# Generated by FakeRAM 2.0
VERSION 5.7 ;
BUSBITCHARS "[]" ;
PROPERTYDEFINITIONS
  MACRO width INTEGER ;
  MACRO depth INTEGER ;
  MACRO banks INTEGER ;
END PROPERTYDEFINITIONS
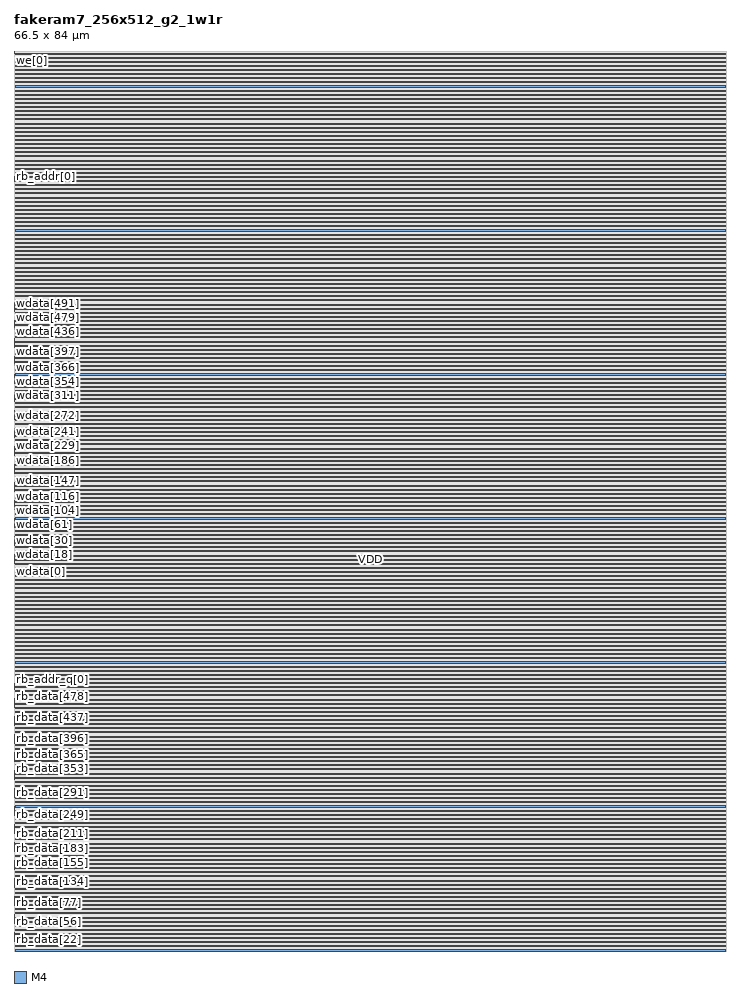
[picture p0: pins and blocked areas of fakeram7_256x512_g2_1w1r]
MACRO fakeram7_256x512_g2_1w1r
  PROPERTY width 512 ;
  PROPERTY depth 256 ;
  PROPERTY banks 1 ;
  FOREIGN fakeram7_256x512_g2_1w1r 0 0 ;
  SYMMETRY X Y R90 ;
  SIZE 66.5000 BY 84.0000 ;
  CLASS BLOCK ;
  PIN wdata[0]
    DIRECTION INPUT ;
    USE SIGNAL ;
    PORT
      LAYER M4 ;
      RECT 0.00000 36.14400 0.03600 36.16800 ;
    END
  END wdata[0]
  PIN wdata[1]
    DIRECTION INPUT ;
    USE SIGNAL ;
    PORT
      LAYER M4 ;
      RECT 0.00000 36.19200 0.03600 36.21600 ;
    END
  END wdata[1]
  PIN wdata[2]
    DIRECTION INPUT ;
    USE SIGNAL ;
    PORT
      LAYER M4 ;
      RECT 0.00000 36.24000 0.03600 36.26400 ;
    END
  END wdata[2]
  PIN wdata[3]
    DIRECTION INPUT ;
    USE SIGNAL ;
    PORT
      LAYER M4 ;
      RECT 0.00000 36.28800 0.03600 36.31200 ;
    END
  END wdata[3]
  PIN wdata[4]
    DIRECTION INPUT ;
    USE SIGNAL ;
    PORT
      LAYER M4 ;
      RECT 0.00000 36.33600 0.03600 36.36000 ;
    END
  END wdata[4]
  PIN wdata[5]
    DIRECTION INPUT ;
    USE SIGNAL ;
    PORT
      LAYER M4 ;
      RECT 0.00000 36.38400 0.03600 36.40800 ;
    END
  END wdata[5]
  PIN wdata[6]
    DIRECTION INPUT ;
    USE SIGNAL ;
    PORT
      LAYER M4 ;
      RECT 0.00000 36.43200 0.03600 36.45600 ;
    END
  END wdata[6]
  PIN wdata[7]
    DIRECTION INPUT ;
    USE SIGNAL ;
    PORT
      LAYER M4 ;
      RECT 0.00000 36.48000 0.03600 36.50400 ;
    END
  END wdata[7]
  PIN wdata[8]
    DIRECTION INPUT ;
    USE SIGNAL ;
    PORT
      LAYER M4 ;
      RECT 0.00000 36.52800 0.03600 36.55200 ;
    END
  END wdata[8]
  PIN wdata[9]
    DIRECTION INPUT ;
    USE SIGNAL ;
    PORT
      LAYER M4 ;
      RECT 0.00000 36.57600 0.03600 36.60000 ;
    END
  END wdata[9]
  PIN wdata[10]
    DIRECTION INPUT ;
    USE SIGNAL ;
    PORT
      LAYER M4 ;
      RECT 0.00000 36.62400 0.03600 36.64800 ;
    END
  END wdata[10]
  PIN wdata[11]
    DIRECTION INPUT ;
    USE SIGNAL ;
    PORT
      LAYER M4 ;
      RECT 0.00000 36.67200 0.03600 36.69600 ;
    END
  END wdata[11]
  PIN wdata[12]
    DIRECTION INPUT ;
    USE SIGNAL ;
    PORT
      LAYER M4 ;
      RECT 0.00000 36.72000 0.03600 36.74400 ;
    END
  END wdata[12]
  PIN wdata[13]
    DIRECTION INPUT ;
    USE SIGNAL ;
    PORT
      LAYER M4 ;
      RECT 0.00000 36.76800 0.03600 36.79200 ;
    END
  END wdata[13]
  PIN wdata[14]
    DIRECTION INPUT ;
    USE SIGNAL ;
    PORT
      LAYER M4 ;
      RECT 0.00000 36.81600 0.03600 36.84000 ;
    END
  END wdata[14]
  PIN wdata[15]
    DIRECTION INPUT ;
    USE SIGNAL ;
    PORT
      LAYER M4 ;
      RECT 0.00000 36.86400 0.03600 36.88800 ;
    END
  END wdata[15]
  PIN wdata[16]
    DIRECTION INPUT ;
    USE SIGNAL ;
    PORT
      LAYER M4 ;
      RECT 0.00000 36.91200 0.03600 36.93600 ;
    END
  END wdata[16]
  PIN wdata[17]
    DIRECTION INPUT ;
    USE SIGNAL ;
    PORT
      LAYER M4 ;
      RECT 0.00000 36.96000 0.03600 36.98400 ;
    END
  END wdata[17]
  PIN wdata[18]
    DIRECTION INPUT ;
    USE SIGNAL ;
    PORT
      LAYER M4 ;
      RECT 0.00000 37.00800 0.03600 37.03200 ;
    END
  END wdata[18]
  PIN wdata[19]
    DIRECTION INPUT ;
    USE SIGNAL ;
    PORT
      LAYER M4 ;
      RECT 0.00000 37.05600 0.03600 37.08000 ;
    END
  END wdata[19]
  PIN wdata[20]
    DIRECTION INPUT ;
    USE SIGNAL ;
    PORT
      LAYER M4 ;
      RECT 0.00000 37.10400 0.03600 37.12800 ;
    END
  END wdata[20]
  PIN wdata[21]
    DIRECTION INPUT ;
    USE SIGNAL ;
    PORT
      LAYER M4 ;
      RECT 0.00000 37.15200 0.03600 37.17600 ;
    END
  END wdata[21]
  PIN wdata[22]
    DIRECTION INPUT ;
    USE SIGNAL ;
    PORT
      LAYER M4 ;
      RECT 0.00000 37.20000 0.03600 37.22400 ;
    END
  END wdata[22]
  PIN wdata[23]
    DIRECTION INPUT ;
    USE SIGNAL ;
    PORT
      LAYER M4 ;
      RECT 0.00000 37.24800 0.03600 37.27200 ;
    END
  END wdata[23]
  PIN wdata[24]
    DIRECTION INPUT ;
    USE SIGNAL ;
    PORT
      LAYER M4 ;
      RECT 0.00000 37.29600 0.03600 37.32000 ;
    END
  END wdata[24]
  PIN wdata[25]
    DIRECTION INPUT ;
    USE SIGNAL ;
    PORT
      LAYER M4 ;
      RECT 0.00000 37.34400 0.03600 37.36800 ;
    END
  END wdata[25]
  PIN wdata[26]
    DIRECTION INPUT ;
    USE SIGNAL ;
    PORT
      LAYER M4 ;
      RECT 0.00000 37.39200 0.03600 37.41600 ;
    END
  END wdata[26]
  PIN wdata[27]
    DIRECTION INPUT ;
    USE SIGNAL ;
    PORT
      LAYER M4 ;
      RECT 0.00000 37.44000 0.03600 37.46400 ;
    END
  END wdata[27]
  PIN wdata[28]
    DIRECTION INPUT ;
    USE SIGNAL ;
    PORT
      LAYER M4 ;
      RECT 0.00000 37.48800 0.03600 37.51200 ;
    END
  END wdata[28]
  PIN wdata[29]
    DIRECTION INPUT ;
    USE SIGNAL ;
    PORT
      LAYER M4 ;
      RECT 0.00000 37.53600 0.03600 37.56000 ;
    END
  END wdata[29]
  PIN wdata[30]
    DIRECTION INPUT ;
    USE SIGNAL ;
    PORT
      LAYER M4 ;
      RECT 0.00000 37.58400 0.03600 37.60800 ;
    END
  END wdata[30]
  PIN wdata[31]
    DIRECTION INPUT ;
    USE SIGNAL ;
    PORT
      LAYER M4 ;
      RECT 0.00000 37.63200 0.03600 37.65600 ;
    END
  END wdata[31]
  PIN wdata[32]
    DIRECTION INPUT ;
    USE SIGNAL ;
    PORT
      LAYER M4 ;
      RECT 0.00000 37.68000 0.03600 37.70400 ;
    END
  END wdata[32]
  PIN wdata[33]
    DIRECTION INPUT ;
    USE SIGNAL ;
    PORT
      LAYER M4 ;
      RECT 0.00000 37.72800 0.03600 37.75200 ;
    END
  END wdata[33]
  PIN wdata[34]
    DIRECTION INPUT ;
    USE SIGNAL ;
    PORT
      LAYER M4 ;
      RECT 0.00000 37.77600 0.03600 37.80000 ;
    END
  END wdata[34]
  PIN wdata[35]
    DIRECTION INPUT ;
    USE SIGNAL ;
    PORT
      LAYER M4 ;
      RECT 0.00000 37.82400 0.03600 37.84800 ;
    END
  END wdata[35]
  PIN wdata[36]
    DIRECTION INPUT ;
    USE SIGNAL ;
    PORT
      LAYER M4 ;
      RECT 0.00000 37.87200 0.03600 37.89600 ;
    END
  END wdata[36]
  PIN wdata[37]
    DIRECTION INPUT ;
    USE SIGNAL ;
    PORT
      LAYER M4 ;
      RECT 0.00000 37.92000 0.03600 37.94400 ;
    END
  END wdata[37]
  PIN wdata[38]
    DIRECTION INPUT ;
    USE SIGNAL ;
    PORT
      LAYER M4 ;
      RECT 0.00000 37.96800 0.03600 37.99200 ;
    END
  END wdata[38]
  PIN wdata[39]
    DIRECTION INPUT ;
    USE SIGNAL ;
    PORT
      LAYER M4 ;
      RECT 0.00000 38.01600 0.03600 38.04000 ;
    END
  END wdata[39]
  PIN wdata[40]
    DIRECTION INPUT ;
    USE SIGNAL ;
    PORT
      LAYER M4 ;
      RECT 0.00000 38.06400 0.03600 38.08800 ;
    END
  END wdata[40]
  PIN wdata[41]
    DIRECTION INPUT ;
    USE SIGNAL ;
    PORT
      LAYER M4 ;
      RECT 0.00000 38.11200 0.03600 38.13600 ;
    END
  END wdata[41]
  PIN wdata[42]
    DIRECTION INPUT ;
    USE SIGNAL ;
    PORT
      LAYER M4 ;
      RECT 0.00000 38.16000 0.03600 38.18400 ;
    END
  END wdata[42]
  PIN wdata[43]
    DIRECTION INPUT ;
    USE SIGNAL ;
    PORT
      LAYER M4 ;
      RECT 0.00000 38.20800 0.03600 38.23200 ;
    END
  END wdata[43]
  PIN wdata[44]
    DIRECTION INPUT ;
    USE SIGNAL ;
    PORT
      LAYER M4 ;
      RECT 0.00000 38.25600 0.03600 38.28000 ;
    END
  END wdata[44]
  PIN wdata[45]
    DIRECTION INPUT ;
    USE SIGNAL ;
    PORT
      LAYER M4 ;
      RECT 0.00000 38.30400 0.03600 38.32800 ;
    END
  END wdata[45]
  PIN wdata[46]
    DIRECTION INPUT ;
    USE SIGNAL ;
    PORT
      LAYER M4 ;
      RECT 0.00000 38.35200 0.03600 38.37600 ;
    END
  END wdata[46]
  PIN wdata[47]
    DIRECTION INPUT ;
    USE SIGNAL ;
    PORT
      LAYER M4 ;
      RECT 0.00000 38.40000 0.03600 38.42400 ;
    END
  END wdata[47]
  PIN wdata[48]
    DIRECTION INPUT ;
    USE SIGNAL ;
    PORT
      LAYER M4 ;
      RECT 0.00000 38.44800 0.03600 38.47200 ;
    END
  END wdata[48]
  PIN wdata[49]
    DIRECTION INPUT ;
    USE SIGNAL ;
    PORT
      LAYER M4 ;
      RECT 0.00000 38.49600 0.03600 38.52000 ;
    END
  END wdata[49]
  PIN wdata[50]
    DIRECTION INPUT ;
    USE SIGNAL ;
    PORT
      LAYER M4 ;
      RECT 0.00000 38.54400 0.03600 38.56800 ;
    END
  END wdata[50]
  PIN wdata[51]
    DIRECTION INPUT ;
    USE SIGNAL ;
    PORT
      LAYER M4 ;
      RECT 0.00000 38.59200 0.03600 38.61600 ;
    END
  END wdata[51]
  PIN wdata[52]
    DIRECTION INPUT ;
    USE SIGNAL ;
    PORT
      LAYER M4 ;
      RECT 0.00000 38.64000 0.03600 38.66400 ;
    END
  END wdata[52]
  PIN wdata[53]
    DIRECTION INPUT ;
    USE SIGNAL ;
    PORT
      LAYER M4 ;
      RECT 0.00000 38.68800 0.03600 38.71200 ;
    END
  END wdata[53]
  PIN wdata[54]
    DIRECTION INPUT ;
    USE SIGNAL ;
    PORT
      LAYER M4 ;
      RECT 0.00000 38.73600 0.03600 38.76000 ;
    END
  END wdata[54]
  PIN wdata[55]
    DIRECTION INPUT ;
    USE SIGNAL ;
    PORT
      LAYER M4 ;
      RECT 0.00000 38.78400 0.03600 38.80800 ;
    END
  END wdata[55]
  PIN wdata[56]
    DIRECTION INPUT ;
    USE SIGNAL ;
    PORT
      LAYER M4 ;
      RECT 0.00000 38.83200 0.03600 38.85600 ;
    END
  END wdata[56]
  PIN wdata[57]
    DIRECTION INPUT ;
    USE SIGNAL ;
    PORT
      LAYER M4 ;
      RECT 0.00000 38.88000 0.03600 38.90400 ;
    END
  END wdata[57]
  PIN wdata[58]
    DIRECTION INPUT ;
    USE SIGNAL ;
    PORT
      LAYER M4 ;
      RECT 0.00000 38.92800 0.03600 38.95200 ;
    END
  END wdata[58]
  PIN wdata[59]
    DIRECTION INPUT ;
    USE SIGNAL ;
    PORT
      LAYER M4 ;
      RECT 0.00000 38.97600 0.03600 39.00000 ;
    END
  END wdata[59]
  PIN wdata[60]
    DIRECTION INPUT ;
    USE SIGNAL ;
    PORT
      LAYER M4 ;
      RECT 0.00000 39.02400 0.03600 39.04800 ;
    END
  END wdata[60]
  PIN wdata[61]
    DIRECTION INPUT ;
    USE SIGNAL ;
    PORT
      LAYER M4 ;
      RECT 0.00000 39.07200 0.03600 39.09600 ;
    END
  END wdata[61]
  PIN wdata[62]
    DIRECTION INPUT ;
    USE SIGNAL ;
    PORT
      LAYER M4 ;
      RECT 0.00000 39.12000 0.03600 39.14400 ;
    END
  END wdata[62]
  PIN wdata[63]
    DIRECTION INPUT ;
    USE SIGNAL ;
    PORT
      LAYER M4 ;
      RECT 0.00000 39.16800 0.03600 39.19200 ;
    END
  END wdata[63]
  PIN wdata[64]
    DIRECTION INPUT ;
    USE SIGNAL ;
    PORT
      LAYER M4 ;
      RECT 0.00000 39.21600 0.03600 39.24000 ;
    END
  END wdata[64]
  PIN wdata[65]
    DIRECTION INPUT ;
    USE SIGNAL ;
    PORT
      LAYER M4 ;
      RECT 0.00000 39.26400 0.03600 39.28800 ;
    END
  END wdata[65]
  PIN wdata[66]
    DIRECTION INPUT ;
    USE SIGNAL ;
    PORT
      LAYER M4 ;
      RECT 0.00000 39.31200 0.03600 39.33600 ;
    END
  END wdata[66]
  PIN wdata[67]
    DIRECTION INPUT ;
    USE SIGNAL ;
    PORT
      LAYER M4 ;
      RECT 0.00000 39.36000 0.03600 39.38400 ;
    END
  END wdata[67]
  PIN wdata[68]
    DIRECTION INPUT ;
    USE SIGNAL ;
    PORT
      LAYER M4 ;
      RECT 0.00000 39.40800 0.03600 39.43200 ;
    END
  END wdata[68]
  PIN wdata[69]
    DIRECTION INPUT ;
    USE SIGNAL ;
    PORT
      LAYER M4 ;
      RECT 0.00000 39.45600 0.03600 39.48000 ;
    END
  END wdata[69]
  PIN wdata[70]
    DIRECTION INPUT ;
    USE SIGNAL ;
    PORT
      LAYER M4 ;
      RECT 0.00000 39.50400 0.03600 39.52800 ;
    END
  END wdata[70]
  PIN wdata[71]
    DIRECTION INPUT ;
    USE SIGNAL ;
    PORT
      LAYER M4 ;
      RECT 0.00000 39.55200 0.03600 39.57600 ;
    END
  END wdata[71]
  PIN wdata[72]
    DIRECTION INPUT ;
    USE SIGNAL ;
    PORT
      LAYER M4 ;
      RECT 0.00000 39.60000 0.03600 39.62400 ;
    END
  END wdata[72]
  PIN wdata[73]
    DIRECTION INPUT ;
    USE SIGNAL ;
    PORT
      LAYER M4 ;
      RECT 0.00000 39.64800 0.03600 39.67200 ;
    END
  END wdata[73]
  PIN wdata[74]
    DIRECTION INPUT ;
    USE SIGNAL ;
    PORT
      LAYER M4 ;
      RECT 0.00000 39.69600 0.03600 39.72000 ;
    END
  END wdata[74]
  PIN wdata[75]
    DIRECTION INPUT ;
    USE SIGNAL ;
    PORT
      LAYER M4 ;
      RECT 0.00000 39.74400 0.03600 39.76800 ;
    END
  END wdata[75]
  PIN wdata[76]
    DIRECTION INPUT ;
    USE SIGNAL ;
    PORT
      LAYER M4 ;
      RECT 0.00000 39.79200 0.03600 39.81600 ;
    END
  END wdata[76]
  PIN wdata[77]
    DIRECTION INPUT ;
    USE SIGNAL ;
    PORT
      LAYER M4 ;
      RECT 0.00000 39.84000 0.03600 39.86400 ;
    END
  END wdata[77]
  PIN wdata[78]
    DIRECTION INPUT ;
    USE SIGNAL ;
    PORT
      LAYER M4 ;
      RECT 0.00000 39.88800 0.03600 39.91200 ;
    END
  END wdata[78]
  PIN wdata[79]
    DIRECTION INPUT ;
    USE SIGNAL ;
    PORT
      LAYER M4 ;
      RECT 0.00000 39.93600 0.03600 39.96000 ;
    END
  END wdata[79]
  PIN wdata[80]
    DIRECTION INPUT ;
    USE SIGNAL ;
    PORT
      LAYER M4 ;
      RECT 0.00000 39.98400 0.03600 40.00800 ;
    END
  END wdata[80]
  PIN wdata[81]
    DIRECTION INPUT ;
    USE SIGNAL ;
    PORT
      LAYER M4 ;
      RECT 0.00000 40.03200 0.03600 40.05600 ;
    END
  END wdata[81]
  PIN wdata[82]
    DIRECTION INPUT ;
    USE SIGNAL ;
    PORT
      LAYER M4 ;
      RECT 0.00000 40.08000 0.03600 40.10400 ;
    END
  END wdata[82]
  PIN wdata[83]
    DIRECTION INPUT ;
    USE SIGNAL ;
    PORT
      LAYER M4 ;
      RECT 0.00000 40.12800 0.03600 40.15200 ;
    END
  END wdata[83]
  PIN wdata[84]
    DIRECTION INPUT ;
    USE SIGNAL ;
    PORT
      LAYER M4 ;
      RECT 0.00000 40.17600 0.03600 40.20000 ;
    END
  END wdata[84]
  PIN wdata[85]
    DIRECTION INPUT ;
    USE SIGNAL ;
    PORT
      LAYER M4 ;
      RECT 0.00000 40.22400 0.03600 40.24800 ;
    END
  END wdata[85]
  PIN wdata[86]
    DIRECTION INPUT ;
    USE SIGNAL ;
    PORT
      LAYER M4 ;
      RECT 0.00000 40.27200 0.03600 40.29600 ;
    END
  END wdata[86]
  PIN wdata[87]
    DIRECTION INPUT ;
    USE SIGNAL ;
    PORT
      LAYER M4 ;
      RECT 0.00000 40.32000 0.03600 40.34400 ;
    END
  END wdata[87]
  PIN wdata[88]
    DIRECTION INPUT ;
    USE SIGNAL ;
    PORT
      LAYER M4 ;
      RECT 0.00000 40.36800 0.03600 40.39200 ;
    END
  END wdata[88]
  PIN wdata[89]
    DIRECTION INPUT ;
    USE SIGNAL ;
    PORT
      LAYER M4 ;
      RECT 0.00000 40.41600 0.03600 40.44000 ;
    END
  END wdata[89]
  PIN wdata[90]
    DIRECTION INPUT ;
    USE SIGNAL ;
    PORT
      LAYER M4 ;
      RECT 0.00000 40.46400 0.03600 40.48800 ;
    END
  END wdata[90]
  PIN wdata[91]
    DIRECTION INPUT ;
    USE SIGNAL ;
    PORT
      LAYER M4 ;
      RECT 0.00000 40.51200 0.03600 40.53600 ;
    END
  END wdata[91]
  PIN wdata[92]
    DIRECTION INPUT ;
    USE SIGNAL ;
    PORT
      LAYER M4 ;
      RECT 0.00000 40.56000 0.03600 40.58400 ;
    END
  END wdata[92]
  PIN wdata[93]
    DIRECTION INPUT ;
    USE SIGNAL ;
    PORT
      LAYER M4 ;
      RECT 0.00000 40.60800 0.03600 40.63200 ;
    END
  END wdata[93]
  PIN wdata[94]
    DIRECTION INPUT ;
    USE SIGNAL ;
    PORT
      LAYER M4 ;
      RECT 0.00000 40.65600 0.03600 40.68000 ;
    END
  END wdata[94]
  PIN wdata[95]
    DIRECTION INPUT ;
    USE SIGNAL ;
    PORT
      LAYER M4 ;
      RECT 0.00000 40.70400 0.03600 40.72800 ;
    END
  END wdata[95]
  PIN wdata[96]
    DIRECTION INPUT ;
    USE SIGNAL ;
    PORT
      LAYER M4 ;
      RECT 0.00000 40.75200 0.03600 40.77600 ;
    END
  END wdata[96]
  PIN wdata[97]
    DIRECTION INPUT ;
    USE SIGNAL ;
    PORT
      LAYER M4 ;
      RECT 0.00000 40.80000 0.03600 40.82400 ;
    END
  END wdata[97]
  PIN wdata[98]
    DIRECTION INPUT ;
    USE SIGNAL ;
    PORT
      LAYER M4 ;
      RECT 0.00000 40.84800 0.03600 40.87200 ;
    END
  END wdata[98]
  PIN wdata[99]
    DIRECTION INPUT ;
    USE SIGNAL ;
    PORT
      LAYER M4 ;
      RECT 0.00000 40.89600 0.03600 40.92000 ;
    END
  END wdata[99]
  PIN wdata[100]
    DIRECTION INPUT ;
    USE SIGNAL ;
    PORT
      LAYER M4 ;
      RECT 0.00000 40.94400 0.03600 40.96800 ;
    END
  END wdata[100]
  PIN wdata[101]
    DIRECTION INPUT ;
    USE SIGNAL ;
    PORT
      LAYER M4 ;
      RECT 0.00000 40.99200 0.03600 41.01600 ;
    END
  END wdata[101]
  PIN wdata[102]
    DIRECTION INPUT ;
    USE SIGNAL ;
    PORT
      LAYER M4 ;
      RECT 0.00000 41.04000 0.03600 41.06400 ;
    END
  END wdata[102]
  PIN wdata[103]
    DIRECTION INPUT ;
    USE SIGNAL ;
    PORT
      LAYER M4 ;
      RECT 0.00000 41.08800 0.03600 41.11200 ;
    END
  END wdata[103]
  PIN wdata[104]
    DIRECTION INPUT ;
    USE SIGNAL ;
    PORT
      LAYER M4 ;
      RECT 0.00000 41.13600 0.03600 41.16000 ;
    END
  END wdata[104]
  PIN wdata[105]
    DIRECTION INPUT ;
    USE SIGNAL ;
    PORT
      LAYER M4 ;
      RECT 0.00000 41.18400 0.03600 41.20800 ;
    END
  END wdata[105]
  PIN wdata[106]
    DIRECTION INPUT ;
    USE SIGNAL ;
    PORT
      LAYER M4 ;
      RECT 0.00000 41.23200 0.03600 41.25600 ;
    END
  END wdata[106]
  PIN wdata[107]
    DIRECTION INPUT ;
    USE SIGNAL ;
    PORT
      LAYER M4 ;
      RECT 0.00000 41.28000 0.03600 41.30400 ;
    END
  END wdata[107]
  PIN wdata[108]
    DIRECTION INPUT ;
    USE SIGNAL ;
    PORT
      LAYER M4 ;
      RECT 0.00000 41.32800 0.03600 41.35200 ;
    END
  END wdata[108]
  PIN wdata[109]
    DIRECTION INPUT ;
    USE SIGNAL ;
    PORT
      LAYER M4 ;
      RECT 0.00000 41.37600 0.03600 41.40000 ;
    END
  END wdata[109]
  PIN wdata[110]
    DIRECTION INPUT ;
    USE SIGNAL ;
    PORT
      LAYER M4 ;
      RECT 0.00000 41.42400 0.03600 41.44800 ;
    END
  END wdata[110]
  PIN wdata[111]
    DIRECTION INPUT ;
    USE SIGNAL ;
    PORT
      LAYER M4 ;
      RECT 0.00000 41.47200 0.03600 41.49600 ;
    END
  END wdata[111]
  PIN wdata[112]
    DIRECTION INPUT ;
    USE SIGNAL ;
    PORT
      LAYER M4 ;
      RECT 0.00000 41.52000 0.03600 41.54400 ;
    END
  END wdata[112]
  PIN wdata[113]
    DIRECTION INPUT ;
    USE SIGNAL ;
    PORT
      LAYER M4 ;
      RECT 0.00000 41.56800 0.03600 41.59200 ;
    END
  END wdata[113]
  PIN wdata[114]
    DIRECTION INPUT ;
    USE SIGNAL ;
    PORT
      LAYER M4 ;
      RECT 0.00000 41.61600 0.03600 41.64000 ;
    END
  END wdata[114]
  PIN wdata[115]
    DIRECTION INPUT ;
    USE SIGNAL ;
    PORT
      LAYER M4 ;
      RECT 0.00000 41.66400 0.03600 41.68800 ;
    END
  END wdata[115]
  PIN wdata[116]
    DIRECTION INPUT ;
    USE SIGNAL ;
    PORT
      LAYER M4 ;
      RECT 0.00000 41.71200 0.03600 41.73600 ;
    END
  END wdata[116]
  PIN wdata[117]
    DIRECTION INPUT ;
    USE SIGNAL ;
    PORT
      LAYER M4 ;
      RECT 0.00000 41.76000 0.03600 41.78400 ;
    END
  END wdata[117]
  PIN wdata[118]
    DIRECTION INPUT ;
    USE SIGNAL ;
    PORT
      LAYER M4 ;
      RECT 0.00000 41.80800 0.03600 41.83200 ;
    END
  END wdata[118]
  PIN wdata[119]
    DIRECTION INPUT ;
    USE SIGNAL ;
    PORT
      LAYER M4 ;
      RECT 0.00000 41.85600 0.03600 41.88000 ;
    END
  END wdata[119]
  PIN wdata[120]
    DIRECTION INPUT ;
    USE SIGNAL ;
    PORT
      LAYER M4 ;
      RECT 0.00000 41.90400 0.03600 41.92800 ;
    END
  END wdata[120]
  PIN wdata[121]
    DIRECTION INPUT ;
    USE SIGNAL ;
    PORT
      LAYER M4 ;
      RECT 0.00000 41.95200 0.03600 41.97600 ;
    END
  END wdata[121]
  PIN wdata[122]
    DIRECTION INPUT ;
    USE SIGNAL ;
    PORT
      LAYER M4 ;
      RECT 0.00000 42.00000 0.03600 42.02400 ;
    END
  END wdata[122]
  PIN wdata[123]
    DIRECTION INPUT ;
    USE SIGNAL ;
    PORT
      LAYER M4 ;
      RECT 0.00000 42.04800 0.03600 42.07200 ;
    END
  END wdata[123]
  PIN wdata[124]
    DIRECTION INPUT ;
    USE SIGNAL ;
    PORT
      LAYER M4 ;
      RECT 0.00000 42.09600 0.03600 42.12000 ;
    END
  END wdata[124]
  PIN wdata[125]
    DIRECTION INPUT ;
    USE SIGNAL ;
    PORT
      LAYER M4 ;
      RECT 0.00000 42.14400 0.03600 42.16800 ;
    END
  END wdata[125]
  PIN wdata[126]
    DIRECTION INPUT ;
    USE SIGNAL ;
    PORT
      LAYER M4 ;
      RECT 0.00000 42.19200 0.03600 42.21600 ;
    END
  END wdata[126]
  PIN wdata[127]
    DIRECTION INPUT ;
    USE SIGNAL ;
    PORT
      LAYER M4 ;
      RECT 0.00000 42.24000 0.03600 42.26400 ;
    END
  END wdata[127]
  PIN wdata[128]
    DIRECTION INPUT ;
    USE SIGNAL ;
    PORT
      LAYER M4 ;
      RECT 0.00000 42.28800 0.03600 42.31200 ;
    END
  END wdata[128]
  PIN wdata[129]
    DIRECTION INPUT ;
    USE SIGNAL ;
    PORT
      LAYER M4 ;
      RECT 0.00000 42.33600 0.03600 42.36000 ;
    END
  END wdata[129]
  PIN wdata[130]
    DIRECTION INPUT ;
    USE SIGNAL ;
    PORT
      LAYER M4 ;
      RECT 0.00000 42.38400 0.03600 42.40800 ;
    END
  END wdata[130]
  PIN wdata[131]
    DIRECTION INPUT ;
    USE SIGNAL ;
    PORT
      LAYER M4 ;
      RECT 0.00000 42.43200 0.03600 42.45600 ;
    END
  END wdata[131]
  PIN wdata[132]
    DIRECTION INPUT ;
    USE SIGNAL ;
    PORT
      LAYER M4 ;
      RECT 0.00000 42.48000 0.03600 42.50400 ;
    END
  END wdata[132]
  PIN wdata[133]
    DIRECTION INPUT ;
    USE SIGNAL ;
    PORT
      LAYER M4 ;
      RECT 0.00000 42.52800 0.03600 42.55200 ;
    END
  END wdata[133]
  PIN wdata[134]
    DIRECTION INPUT ;
    USE SIGNAL ;
    PORT
      LAYER M4 ;
      RECT 0.00000 42.57600 0.03600 42.60000 ;
    END
  END wdata[134]
  PIN wdata[135]
    DIRECTION INPUT ;
    USE SIGNAL ;
    PORT
      LAYER M4 ;
      RECT 0.00000 42.62400 0.03600 42.64800 ;
    END
  END wdata[135]
  PIN wdata[136]
    DIRECTION INPUT ;
    USE SIGNAL ;
    PORT
      LAYER M4 ;
      RECT 0.00000 42.67200 0.03600 42.69600 ;
    END
  END wdata[136]
  PIN wdata[137]
    DIRECTION INPUT ;
    USE SIGNAL ;
    PORT
      LAYER M4 ;
      RECT 0.00000 42.72000 0.03600 42.74400 ;
    END
  END wdata[137]
  PIN wdata[138]
    DIRECTION INPUT ;
    USE SIGNAL ;
    PORT
      LAYER M4 ;
      RECT 0.00000 42.76800 0.03600 42.79200 ;
    END
  END wdata[138]
  PIN wdata[139]
    DIRECTION INPUT ;
    USE SIGNAL ;
    PORT
      LAYER M4 ;
      RECT 0.00000 42.81600 0.03600 42.84000 ;
    END
  END wdata[139]
  PIN wdata[140]
    DIRECTION INPUT ;
    USE SIGNAL ;
    PORT
      LAYER M4 ;
      RECT 0.00000 42.86400 0.03600 42.88800 ;
    END
  END wdata[140]
  PIN wdata[141]
    DIRECTION INPUT ;
    USE SIGNAL ;
    PORT
      LAYER M4 ;
      RECT 0.00000 42.91200 0.03600 42.93600 ;
    END
  END wdata[141]
  PIN wdata[142]
    DIRECTION INPUT ;
    USE SIGNAL ;
    PORT
      LAYER M4 ;
      RECT 0.00000 42.96000 0.03600 42.98400 ;
    END
  END wdata[142]
  PIN wdata[143]
    DIRECTION INPUT ;
    USE SIGNAL ;
    PORT
      LAYER M4 ;
      RECT 0.00000 43.00800 0.03600 43.03200 ;
    END
  END wdata[143]
  PIN wdata[144]
    DIRECTION INPUT ;
    USE SIGNAL ;
    PORT
      LAYER M4 ;
      RECT 0.00000 43.05600 0.03600 43.08000 ;
    END
  END wdata[144]
  PIN wdata[145]
    DIRECTION INPUT ;
    USE SIGNAL ;
    PORT
      LAYER M4 ;
      RECT 0.00000 43.10400 0.03600 43.12800 ;
    END
  END wdata[145]
  PIN wdata[146]
    DIRECTION INPUT ;
    USE SIGNAL ;
    PORT
      LAYER M4 ;
      RECT 0.00000 43.15200 0.03600 43.17600 ;
    END
  END wdata[146]
  PIN wdata[147]
    DIRECTION INPUT ;
    USE SIGNAL ;
    PORT
      LAYER M4 ;
      RECT 0.00000 43.20000 0.03600 43.22400 ;
    END
  END wdata[147]
  PIN wdata[148]
    DIRECTION INPUT ;
    USE SIGNAL ;
    PORT
      LAYER M4 ;
      RECT 0.00000 43.24800 0.03600 43.27200 ;
    END
  END wdata[148]
  PIN wdata[149]
    DIRECTION INPUT ;
    USE SIGNAL ;
    PORT
      LAYER M4 ;
      RECT 0.00000 43.29600 0.03600 43.32000 ;
    END
  END wdata[149]
  PIN wdata[150]
    DIRECTION INPUT ;
    USE SIGNAL ;
    PORT
      LAYER M4 ;
      RECT 0.00000 43.34400 0.03600 43.36800 ;
    END
  END wdata[150]
  PIN wdata[151]
    DIRECTION INPUT ;
    USE SIGNAL ;
    PORT
      LAYER M4 ;
      RECT 0.00000 43.39200 0.03600 43.41600 ;
    END
  END wdata[151]
  PIN wdata[152]
    DIRECTION INPUT ;
    USE SIGNAL ;
    PORT
      LAYER M4 ;
      RECT 0.00000 43.44000 0.03600 43.46400 ;
    END
  END wdata[152]
  PIN wdata[153]
    DIRECTION INPUT ;
    USE SIGNAL ;
    PORT
      LAYER M4 ;
      RECT 0.00000 43.48800 0.03600 43.51200 ;
    END
  END wdata[153]
  PIN wdata[154]
    DIRECTION INPUT ;
    USE SIGNAL ;
    PORT
      LAYER M4 ;
      RECT 0.00000 43.53600 0.03600 43.56000 ;
    END
  END wdata[154]
  PIN wdata[155]
    DIRECTION INPUT ;
    USE SIGNAL ;
    PORT
      LAYER M4 ;
      RECT 0.00000 43.58400 0.03600 43.60800 ;
    END
  END wdata[155]
  PIN wdata[156]
    DIRECTION INPUT ;
    USE SIGNAL ;
    PORT
      LAYER M4 ;
      RECT 0.00000 43.63200 0.03600 43.65600 ;
    END
  END wdata[156]
  PIN wdata[157]
    DIRECTION INPUT ;
    USE SIGNAL ;
    PORT
      LAYER M4 ;
      RECT 0.00000 43.68000 0.03600 43.70400 ;
    END
  END wdata[157]
  PIN wdata[158]
    DIRECTION INPUT ;
    USE SIGNAL ;
    PORT
      LAYER M4 ;
      RECT 0.00000 43.72800 0.03600 43.75200 ;
    END
  END wdata[158]
  PIN wdata[159]
    DIRECTION INPUT ;
    USE SIGNAL ;
    PORT
      LAYER M4 ;
      RECT 0.00000 43.77600 0.03600 43.80000 ;
    END
  END wdata[159]
  PIN wdata[160]
    DIRECTION INPUT ;
    USE SIGNAL ;
    PORT
      LAYER M4 ;
      RECT 0.00000 43.82400 0.03600 43.84800 ;
    END
  END wdata[160]
  PIN wdata[161]
    DIRECTION INPUT ;
    USE SIGNAL ;
    PORT
      LAYER M4 ;
      RECT 0.00000 43.87200 0.03600 43.89600 ;
    END
  END wdata[161]
  PIN wdata[162]
    DIRECTION INPUT ;
    USE SIGNAL ;
    PORT
      LAYER M4 ;
      RECT 0.00000 43.92000 0.03600 43.94400 ;
    END
  END wdata[162]
  PIN wdata[163]
    DIRECTION INPUT ;
    USE SIGNAL ;
    PORT
      LAYER M4 ;
      RECT 0.00000 43.96800 0.03600 43.99200 ;
    END
  END wdata[163]
  PIN wdata[164]
    DIRECTION INPUT ;
    USE SIGNAL ;
    PORT
      LAYER M4 ;
      RECT 0.00000 44.01600 0.03600 44.04000 ;
    END
  END wdata[164]
  PIN wdata[165]
    DIRECTION INPUT ;
    USE SIGNAL ;
    PORT
      LAYER M4 ;
      RECT 0.00000 44.06400 0.03600 44.08800 ;
    END
  END wdata[165]
  PIN wdata[166]
    DIRECTION INPUT ;
    USE SIGNAL ;
    PORT
      LAYER M4 ;
      RECT 0.00000 44.11200 0.03600 44.13600 ;
    END
  END wdata[166]
  PIN wdata[167]
    DIRECTION INPUT ;
    USE SIGNAL ;
    PORT
      LAYER M4 ;
      RECT 0.00000 44.16000 0.03600 44.18400 ;
    END
  END wdata[167]
  PIN wdata[168]
    DIRECTION INPUT ;
    USE SIGNAL ;
    PORT
      LAYER M4 ;
      RECT 0.00000 44.20800 0.03600 44.23200 ;
    END
  END wdata[168]
  PIN wdata[169]
    DIRECTION INPUT ;
    USE SIGNAL ;
    PORT
      LAYER M4 ;
      RECT 0.00000 44.25600 0.03600 44.28000 ;
    END
  END wdata[169]
  PIN wdata[170]
    DIRECTION INPUT ;
    USE SIGNAL ;
    PORT
      LAYER M4 ;
      RECT 0.00000 44.30400 0.03600 44.32800 ;
    END
  END wdata[170]
  PIN wdata[171]
    DIRECTION INPUT ;
    USE SIGNAL ;
    PORT
      LAYER M4 ;
      RECT 0.00000 44.35200 0.03600 44.37600 ;
    END
  END wdata[171]
  PIN wdata[172]
    DIRECTION INPUT ;
    USE SIGNAL ;
    PORT
      LAYER M4 ;
      RECT 0.00000 44.40000 0.03600 44.42400 ;
    END
  END wdata[172]
  PIN wdata[173]
    DIRECTION INPUT ;
    USE SIGNAL ;
    PORT
      LAYER M4 ;
      RECT 0.00000 44.44800 0.03600 44.47200 ;
    END
  END wdata[173]
  PIN wdata[174]
    DIRECTION INPUT ;
    USE SIGNAL ;
    PORT
      LAYER M4 ;
      RECT 0.00000 44.49600 0.03600 44.52000 ;
    END
  END wdata[174]
  PIN wdata[175]
    DIRECTION INPUT ;
    USE SIGNAL ;
    PORT
      LAYER M4 ;
      RECT 0.00000 44.54400 0.03600 44.56800 ;
    END
  END wdata[175]
  PIN wdata[176]
    DIRECTION INPUT ;
    USE SIGNAL ;
    PORT
      LAYER M4 ;
      RECT 0.00000 44.59200 0.03600 44.61600 ;
    END
  END wdata[176]
  PIN wdata[177]
    DIRECTION INPUT ;
    USE SIGNAL ;
    PORT
      LAYER M4 ;
      RECT 0.00000 44.64000 0.03600 44.66400 ;
    END
  END wdata[177]
  PIN wdata[178]
    DIRECTION INPUT ;
    USE SIGNAL ;
    PORT
      LAYER M4 ;
      RECT 0.00000 44.68800 0.03600 44.71200 ;
    END
  END wdata[178]
  PIN wdata[179]
    DIRECTION INPUT ;
    USE SIGNAL ;
    PORT
      LAYER M4 ;
      RECT 0.00000 44.73600 0.03600 44.76000 ;
    END
  END wdata[179]
  PIN wdata[180]
    DIRECTION INPUT ;
    USE SIGNAL ;
    PORT
      LAYER M4 ;
      RECT 0.00000 44.78400 0.03600 44.80800 ;
    END
  END wdata[180]
  PIN wdata[181]
    DIRECTION INPUT ;
    USE SIGNAL ;
    PORT
      LAYER M4 ;
      RECT 0.00000 44.83200 0.03600 44.85600 ;
    END
  END wdata[181]
  PIN wdata[182]
    DIRECTION INPUT ;
    USE SIGNAL ;
    PORT
      LAYER M4 ;
      RECT 0.00000 44.88000 0.03600 44.90400 ;
    END
  END wdata[182]
  PIN wdata[183]
    DIRECTION INPUT ;
    USE SIGNAL ;
    PORT
      LAYER M4 ;
      RECT 0.00000 44.92800 0.03600 44.95200 ;
    END
  END wdata[183]
  PIN wdata[184]
    DIRECTION INPUT ;
    USE SIGNAL ;
    PORT
      LAYER M4 ;
      RECT 0.00000 44.97600 0.03600 45.00000 ;
    END
  END wdata[184]
  PIN wdata[185]
    DIRECTION INPUT ;
    USE SIGNAL ;
    PORT
      LAYER M4 ;
      RECT 0.00000 45.02400 0.03600 45.04800 ;
    END
  END wdata[185]
  PIN wdata[186]
    DIRECTION INPUT ;
    USE SIGNAL ;
    PORT
      LAYER M4 ;
      RECT 0.00000 45.07200 0.03600 45.09600 ;
    END
  END wdata[186]
  PIN wdata[187]
    DIRECTION INPUT ;
    USE SIGNAL ;
    PORT
      LAYER M4 ;
      RECT 0.00000 45.12000 0.03600 45.14400 ;
    END
  END wdata[187]
  PIN wdata[188]
    DIRECTION INPUT ;
    USE SIGNAL ;
    PORT
      LAYER M4 ;
      RECT 0.00000 45.16800 0.03600 45.19200 ;
    END
  END wdata[188]
  PIN wdata[189]
    DIRECTION INPUT ;
    USE SIGNAL ;
    PORT
      LAYER M4 ;
      RECT 0.00000 45.21600 0.03600 45.24000 ;
    END
  END wdata[189]
  PIN wdata[190]
    DIRECTION INPUT ;
    USE SIGNAL ;
    PORT
      LAYER M4 ;
      RECT 0.00000 45.26400 0.03600 45.28800 ;
    END
  END wdata[190]
  PIN wdata[191]
    DIRECTION INPUT ;
    USE SIGNAL ;
    PORT
      LAYER M4 ;
      RECT 0.00000 45.31200 0.03600 45.33600 ;
    END
  END wdata[191]
  PIN wdata[192]
    DIRECTION INPUT ;
    USE SIGNAL ;
    PORT
      LAYER M4 ;
      RECT 0.00000 45.36000 0.03600 45.38400 ;
    END
  END wdata[192]
  PIN wdata[193]
    DIRECTION INPUT ;
    USE SIGNAL ;
    PORT
      LAYER M4 ;
      RECT 0.00000 45.40800 0.03600 45.43200 ;
    END
  END wdata[193]
  PIN wdata[194]
    DIRECTION INPUT ;
    USE SIGNAL ;
    PORT
      LAYER M4 ;
      RECT 0.00000 45.45600 0.03600 45.48000 ;
    END
  END wdata[194]
  PIN wdata[195]
    DIRECTION INPUT ;
    USE SIGNAL ;
    PORT
      LAYER M4 ;
      RECT 0.00000 45.50400 0.03600 45.52800 ;
    END
  END wdata[195]
  PIN wdata[196]
    DIRECTION INPUT ;
    USE SIGNAL ;
    PORT
      LAYER M4 ;
      RECT 0.00000 45.55200 0.03600 45.57600 ;
    END
  END wdata[196]
  PIN wdata[197]
    DIRECTION INPUT ;
    USE SIGNAL ;
    PORT
      LAYER M4 ;
      RECT 0.00000 45.60000 0.03600 45.62400 ;
    END
  END wdata[197]
  PIN wdata[198]
    DIRECTION INPUT ;
    USE SIGNAL ;
    PORT
      LAYER M4 ;
      RECT 0.00000 45.64800 0.03600 45.67200 ;
    END
  END wdata[198]
  PIN wdata[199]
    DIRECTION INPUT ;
    USE SIGNAL ;
    PORT
      LAYER M4 ;
      RECT 0.00000 45.69600 0.03600 45.72000 ;
    END
  END wdata[199]
  PIN wdata[200]
    DIRECTION INPUT ;
    USE SIGNAL ;
    PORT
      LAYER M4 ;
      RECT 0.00000 45.74400 0.03600 45.76800 ;
    END
  END wdata[200]
  PIN wdata[201]
    DIRECTION INPUT ;
    USE SIGNAL ;
    PORT
      LAYER M4 ;
      RECT 0.00000 45.79200 0.03600 45.81600 ;
    END
  END wdata[201]
  PIN wdata[202]
    DIRECTION INPUT ;
    USE SIGNAL ;
    PORT
      LAYER M4 ;
      RECT 0.00000 45.84000 0.03600 45.86400 ;
    END
  END wdata[202]
  PIN wdata[203]
    DIRECTION INPUT ;
    USE SIGNAL ;
    PORT
      LAYER M4 ;
      RECT 0.00000 45.88800 0.03600 45.91200 ;
    END
  END wdata[203]
  PIN wdata[204]
    DIRECTION INPUT ;
    USE SIGNAL ;
    PORT
      LAYER M4 ;
      RECT 0.00000 45.93600 0.03600 45.96000 ;
    END
  END wdata[204]
  PIN wdata[205]
    DIRECTION INPUT ;
    USE SIGNAL ;
    PORT
      LAYER M4 ;
      RECT 0.00000 45.98400 0.03600 46.00800 ;
    END
  END wdata[205]
  PIN wdata[206]
    DIRECTION INPUT ;
    USE SIGNAL ;
    PORT
      LAYER M4 ;
      RECT 0.00000 46.03200 0.03600 46.05600 ;
    END
  END wdata[206]
  PIN wdata[207]
    DIRECTION INPUT ;
    USE SIGNAL ;
    PORT
      LAYER M4 ;
      RECT 0.00000 46.08000 0.03600 46.10400 ;
    END
  END wdata[207]
  PIN wdata[208]
    DIRECTION INPUT ;
    USE SIGNAL ;
    PORT
      LAYER M4 ;
      RECT 0.00000 46.12800 0.03600 46.15200 ;
    END
  END wdata[208]
  PIN wdata[209]
    DIRECTION INPUT ;
    USE SIGNAL ;
    PORT
      LAYER M4 ;
      RECT 0.00000 46.17600 0.03600 46.20000 ;
    END
  END wdata[209]
  PIN wdata[210]
    DIRECTION INPUT ;
    USE SIGNAL ;
    PORT
      LAYER M4 ;
      RECT 0.00000 46.22400 0.03600 46.24800 ;
    END
  END wdata[210]
  PIN wdata[211]
    DIRECTION INPUT ;
    USE SIGNAL ;
    PORT
      LAYER M4 ;
      RECT 0.00000 46.27200 0.03600 46.29600 ;
    END
  END wdata[211]
  PIN wdata[212]
    DIRECTION INPUT ;
    USE SIGNAL ;
    PORT
      LAYER M4 ;
      RECT 0.00000 46.32000 0.03600 46.34400 ;
    END
  END wdata[212]
  PIN wdata[213]
    DIRECTION INPUT ;
    USE SIGNAL ;
    PORT
      LAYER M4 ;
      RECT 0.00000 46.36800 0.03600 46.39200 ;
    END
  END wdata[213]
  PIN wdata[214]
    DIRECTION INPUT ;
    USE SIGNAL ;
    PORT
      LAYER M4 ;
      RECT 0.00000 46.41600 0.03600 46.44000 ;
    END
  END wdata[214]
  PIN wdata[215]
    DIRECTION INPUT ;
    USE SIGNAL ;
    PORT
      LAYER M4 ;
      RECT 0.00000 46.46400 0.03600 46.48800 ;
    END
  END wdata[215]
  PIN wdata[216]
    DIRECTION INPUT ;
    USE SIGNAL ;
    PORT
      LAYER M4 ;
      RECT 0.00000 46.51200 0.03600 46.53600 ;
    END
  END wdata[216]
  PIN wdata[217]
    DIRECTION INPUT ;
    USE SIGNAL ;
    PORT
      LAYER M4 ;
      RECT 0.00000 46.56000 0.03600 46.58400 ;
    END
  END wdata[217]
  PIN wdata[218]
    DIRECTION INPUT ;
    USE SIGNAL ;
    PORT
      LAYER M4 ;
      RECT 0.00000 46.60800 0.03600 46.63200 ;
    END
  END wdata[218]
  PIN wdata[219]
    DIRECTION INPUT ;
    USE SIGNAL ;
    PORT
      LAYER M4 ;
      RECT 0.00000 46.65600 0.03600 46.68000 ;
    END
  END wdata[219]
  PIN wdata[220]
    DIRECTION INPUT ;
    USE SIGNAL ;
    PORT
      LAYER M4 ;
      RECT 0.00000 46.70400 0.03600 46.72800 ;
    END
  END wdata[220]
  PIN wdata[221]
    DIRECTION INPUT ;
    USE SIGNAL ;
    PORT
      LAYER M4 ;
      RECT 0.00000 46.75200 0.03600 46.77600 ;
    END
  END wdata[221]
  PIN wdata[222]
    DIRECTION INPUT ;
    USE SIGNAL ;
    PORT
      LAYER M4 ;
      RECT 0.00000 46.80000 0.03600 46.82400 ;
    END
  END wdata[222]
  PIN wdata[223]
    DIRECTION INPUT ;
    USE SIGNAL ;
    PORT
      LAYER M4 ;
      RECT 0.00000 46.84800 0.03600 46.87200 ;
    END
  END wdata[223]
  PIN wdata[224]
    DIRECTION INPUT ;
    USE SIGNAL ;
    PORT
      LAYER M4 ;
      RECT 0.00000 46.89600 0.03600 46.92000 ;
    END
  END wdata[224]
  PIN wdata[225]
    DIRECTION INPUT ;
    USE SIGNAL ;
    PORT
      LAYER M4 ;
      RECT 0.00000 46.94400 0.03600 46.96800 ;
    END
  END wdata[225]
  PIN wdata[226]
    DIRECTION INPUT ;
    USE SIGNAL ;
    PORT
      LAYER M4 ;
      RECT 0.00000 46.99200 0.03600 47.01600 ;
    END
  END wdata[226]
  PIN wdata[227]
    DIRECTION INPUT ;
    USE SIGNAL ;
    PORT
      LAYER M4 ;
      RECT 0.00000 47.04000 0.03600 47.06400 ;
    END
  END wdata[227]
  PIN wdata[228]
    DIRECTION INPUT ;
    USE SIGNAL ;
    PORT
      LAYER M4 ;
      RECT 0.00000 47.08800 0.03600 47.11200 ;
    END
  END wdata[228]
  PIN wdata[229]
    DIRECTION INPUT ;
    USE SIGNAL ;
    PORT
      LAYER M4 ;
      RECT 0.00000 47.13600 0.03600 47.16000 ;
    END
  END wdata[229]
  PIN wdata[230]
    DIRECTION INPUT ;
    USE SIGNAL ;
    PORT
      LAYER M4 ;
      RECT 0.00000 47.18400 0.03600 47.20800 ;
    END
  END wdata[230]
  PIN wdata[231]
    DIRECTION INPUT ;
    USE SIGNAL ;
    PORT
      LAYER M4 ;
      RECT 0.00000 47.23200 0.03600 47.25600 ;
    END
  END wdata[231]
  PIN wdata[232]
    DIRECTION INPUT ;
    USE SIGNAL ;
    PORT
      LAYER M4 ;
      RECT 0.00000 47.28000 0.03600 47.30400 ;
    END
  END wdata[232]
  PIN wdata[233]
    DIRECTION INPUT ;
    USE SIGNAL ;
    PORT
      LAYER M4 ;
      RECT 0.00000 47.32800 0.03600 47.35200 ;
    END
  END wdata[233]
  PIN wdata[234]
    DIRECTION INPUT ;
    USE SIGNAL ;
    PORT
      LAYER M4 ;
      RECT 0.00000 47.37600 0.03600 47.40000 ;
    END
  END wdata[234]
  PIN wdata[235]
    DIRECTION INPUT ;
    USE SIGNAL ;
    PORT
      LAYER M4 ;
      RECT 0.00000 47.42400 0.03600 47.44800 ;
    END
  END wdata[235]
  PIN wdata[236]
    DIRECTION INPUT ;
    USE SIGNAL ;
    PORT
      LAYER M4 ;
      RECT 0.00000 47.47200 0.03600 47.49600 ;
    END
  END wdata[236]
  PIN wdata[237]
    DIRECTION INPUT ;
    USE SIGNAL ;
    PORT
      LAYER M4 ;
      RECT 0.00000 47.52000 0.03600 47.54400 ;
    END
  END wdata[237]
  PIN wdata[238]
    DIRECTION INPUT ;
    USE SIGNAL ;
    PORT
      LAYER M4 ;
      RECT 0.00000 47.56800 0.03600 47.59200 ;
    END
  END wdata[238]
  PIN wdata[239]
    DIRECTION INPUT ;
    USE SIGNAL ;
    PORT
      LAYER M4 ;
      RECT 0.00000 47.61600 0.03600 47.64000 ;
    END
  END wdata[239]
  PIN wdata[240]
    DIRECTION INPUT ;
    USE SIGNAL ;
    PORT
      LAYER M4 ;
      RECT 0.00000 47.66400 0.03600 47.68800 ;
    END
  END wdata[240]
  PIN wdata[241]
    DIRECTION INPUT ;
    USE SIGNAL ;
    PORT
      LAYER M4 ;
      RECT 0.00000 47.71200 0.03600 47.73600 ;
    END
  END wdata[241]
  PIN wdata[242]
    DIRECTION INPUT ;
    USE SIGNAL ;
    PORT
      LAYER M4 ;
      RECT 0.00000 47.76000 0.03600 47.78400 ;
    END
  END wdata[242]
  PIN wdata[243]
    DIRECTION INPUT ;
    USE SIGNAL ;
    PORT
      LAYER M4 ;
      RECT 0.00000 47.80800 0.03600 47.83200 ;
    END
  END wdata[243]
  PIN wdata[244]
    DIRECTION INPUT ;
    USE SIGNAL ;
    PORT
      LAYER M4 ;
      RECT 0.00000 47.85600 0.03600 47.88000 ;
    END
  END wdata[244]
  PIN wdata[245]
    DIRECTION INPUT ;
    USE SIGNAL ;
    PORT
      LAYER M4 ;
      RECT 0.00000 47.90400 0.03600 47.92800 ;
    END
  END wdata[245]
  PIN wdata[246]
    DIRECTION INPUT ;
    USE SIGNAL ;
    PORT
      LAYER M4 ;
      RECT 0.00000 47.95200 0.03600 47.97600 ;
    END
  END wdata[246]
  PIN wdata[247]
    DIRECTION INPUT ;
    USE SIGNAL ;
    PORT
      LAYER M4 ;
      RECT 0.00000 48.00000 0.03600 48.02400 ;
    END
  END wdata[247]
  PIN wdata[248]
    DIRECTION INPUT ;
    USE SIGNAL ;
    PORT
      LAYER M4 ;
      RECT 0.00000 48.04800 0.03600 48.07200 ;
    END
  END wdata[248]
  PIN wdata[249]
    DIRECTION INPUT ;
    USE SIGNAL ;
    PORT
      LAYER M4 ;
      RECT 0.00000 48.09600 0.03600 48.12000 ;
    END
  END wdata[249]
  PIN wdata[250]
    DIRECTION INPUT ;
    USE SIGNAL ;
    PORT
      LAYER M4 ;
      RECT 0.00000 48.14400 0.03600 48.16800 ;
    END
  END wdata[250]
  PIN wdata[251]
    DIRECTION INPUT ;
    USE SIGNAL ;
    PORT
      LAYER M4 ;
      RECT 0.00000 48.19200 0.03600 48.21600 ;
    END
  END wdata[251]
  PIN wdata[252]
    DIRECTION INPUT ;
    USE SIGNAL ;
    PORT
      LAYER M4 ;
      RECT 0.00000 48.24000 0.03600 48.26400 ;
    END
  END wdata[252]
  PIN wdata[253]
    DIRECTION INPUT ;
    USE SIGNAL ;
    PORT
      LAYER M4 ;
      RECT 0.00000 48.28800 0.03600 48.31200 ;
    END
  END wdata[253]
  PIN wdata[254]
    DIRECTION INPUT ;
    USE SIGNAL ;
    PORT
      LAYER M4 ;
      RECT 0.00000 48.33600 0.03600 48.36000 ;
    END
  END wdata[254]
  PIN wdata[255]
    DIRECTION INPUT ;
    USE SIGNAL ;
    PORT
      LAYER M4 ;
      RECT 0.00000 48.38400 0.03600 48.40800 ;
    END
  END wdata[255]
  PIN wdata[256]
    DIRECTION INPUT ;
    USE SIGNAL ;
    PORT
      LAYER M4 ;
      RECT 0.00000 48.43200 0.03600 48.45600 ;
    END
  END wdata[256]
  PIN wdata[257]
    DIRECTION INPUT ;
    USE SIGNAL ;
    PORT
      LAYER M4 ;
      RECT 0.00000 48.48000 0.03600 48.50400 ;
    END
  END wdata[257]
  PIN wdata[258]
    DIRECTION INPUT ;
    USE SIGNAL ;
    PORT
      LAYER M4 ;
      RECT 0.00000 48.52800 0.03600 48.55200 ;
    END
  END wdata[258]
  PIN wdata[259]
    DIRECTION INPUT ;
    USE SIGNAL ;
    PORT
      LAYER M4 ;
      RECT 0.00000 48.57600 0.03600 48.60000 ;
    END
  END wdata[259]
  PIN wdata[260]
    DIRECTION INPUT ;
    USE SIGNAL ;
    PORT
      LAYER M4 ;
      RECT 0.00000 48.62400 0.03600 48.64800 ;
    END
  END wdata[260]
  PIN wdata[261]
    DIRECTION INPUT ;
    USE SIGNAL ;
    PORT
      LAYER M4 ;
      RECT 0.00000 48.67200 0.03600 48.69600 ;
    END
  END wdata[261]
  PIN wdata[262]
    DIRECTION INPUT ;
    USE SIGNAL ;
    PORT
      LAYER M4 ;
      RECT 0.00000 48.72000 0.03600 48.74400 ;
    END
  END wdata[262]
  PIN wdata[263]
    DIRECTION INPUT ;
    USE SIGNAL ;
    PORT
      LAYER M4 ;
      RECT 0.00000 48.76800 0.03600 48.79200 ;
    END
  END wdata[263]
  PIN wdata[264]
    DIRECTION INPUT ;
    USE SIGNAL ;
    PORT
      LAYER M4 ;
      RECT 0.00000 48.81600 0.03600 48.84000 ;
    END
  END wdata[264]
  PIN wdata[265]
    DIRECTION INPUT ;
    USE SIGNAL ;
    PORT
      LAYER M4 ;
      RECT 0.00000 48.86400 0.03600 48.88800 ;
    END
  END wdata[265]
  PIN wdata[266]
    DIRECTION INPUT ;
    USE SIGNAL ;
    PORT
      LAYER M4 ;
      RECT 0.00000 48.91200 0.03600 48.93600 ;
    END
  END wdata[266]
  PIN wdata[267]
    DIRECTION INPUT ;
    USE SIGNAL ;
    PORT
      LAYER M4 ;
      RECT 0.00000 48.96000 0.03600 48.98400 ;
    END
  END wdata[267]
  PIN wdata[268]
    DIRECTION INPUT ;
    USE SIGNAL ;
    PORT
      LAYER M4 ;
      RECT 0.00000 49.00800 0.03600 49.03200 ;
    END
  END wdata[268]
  PIN wdata[269]
    DIRECTION INPUT ;
    USE SIGNAL ;
    PORT
      LAYER M4 ;
      RECT 0.00000 49.05600 0.03600 49.08000 ;
    END
  END wdata[269]
  PIN wdata[270]
    DIRECTION INPUT ;
    USE SIGNAL ;
    PORT
      LAYER M4 ;
      RECT 0.00000 49.10400 0.03600 49.12800 ;
    END
  END wdata[270]
  PIN wdata[271]
    DIRECTION INPUT ;
    USE SIGNAL ;
    PORT
      LAYER M4 ;
      RECT 0.00000 49.15200 0.03600 49.17600 ;
    END
  END wdata[271]
  PIN wdata[272]
    DIRECTION INPUT ;
    USE SIGNAL ;
    PORT
      LAYER M4 ;
      RECT 0.00000 49.20000 0.03600 49.22400 ;
    END
  END wdata[272]
  PIN wdata[273]
    DIRECTION INPUT ;
    USE SIGNAL ;
    PORT
      LAYER M4 ;
      RECT 0.00000 49.24800 0.03600 49.27200 ;
    END
  END wdata[273]
  PIN wdata[274]
    DIRECTION INPUT ;
    USE SIGNAL ;
    PORT
      LAYER M4 ;
      RECT 0.00000 49.29600 0.03600 49.32000 ;
    END
  END wdata[274]
  PIN wdata[275]
    DIRECTION INPUT ;
    USE SIGNAL ;
    PORT
      LAYER M4 ;
      RECT 0.00000 49.34400 0.03600 49.36800 ;
    END
  END wdata[275]
  PIN wdata[276]
    DIRECTION INPUT ;
    USE SIGNAL ;
    PORT
      LAYER M4 ;
      RECT 0.00000 49.39200 0.03600 49.41600 ;
    END
  END wdata[276]
  PIN wdata[277]
    DIRECTION INPUT ;
    USE SIGNAL ;
    PORT
      LAYER M4 ;
      RECT 0.00000 49.44000 0.03600 49.46400 ;
    END
  END wdata[277]
  PIN wdata[278]
    DIRECTION INPUT ;
    USE SIGNAL ;
    PORT
      LAYER M4 ;
      RECT 0.00000 49.48800 0.03600 49.51200 ;
    END
  END wdata[278]
  PIN wdata[279]
    DIRECTION INPUT ;
    USE SIGNAL ;
    PORT
      LAYER M4 ;
      RECT 0.00000 49.53600 0.03600 49.56000 ;
    END
  END wdata[279]
  PIN wdata[280]
    DIRECTION INPUT ;
    USE SIGNAL ;
    PORT
      LAYER M4 ;
      RECT 0.00000 49.58400 0.03600 49.60800 ;
    END
  END wdata[280]
  PIN wdata[281]
    DIRECTION INPUT ;
    USE SIGNAL ;
    PORT
      LAYER M4 ;
      RECT 0.00000 49.63200 0.03600 49.65600 ;
    END
  END wdata[281]
  PIN wdata[282]
    DIRECTION INPUT ;
    USE SIGNAL ;
    PORT
      LAYER M4 ;
      RECT 0.00000 49.68000 0.03600 49.70400 ;
    END
  END wdata[282]
  PIN wdata[283]
    DIRECTION INPUT ;
    USE SIGNAL ;
    PORT
      LAYER M4 ;
      RECT 0.00000 49.72800 0.03600 49.75200 ;
    END
  END wdata[283]
  PIN wdata[284]
    DIRECTION INPUT ;
    USE SIGNAL ;
    PORT
      LAYER M4 ;
      RECT 0.00000 49.77600 0.03600 49.80000 ;
    END
  END wdata[284]
  PIN wdata[285]
    DIRECTION INPUT ;
    USE SIGNAL ;
    PORT
      LAYER M4 ;
      RECT 0.00000 49.82400 0.03600 49.84800 ;
    END
  END wdata[285]
  PIN wdata[286]
    DIRECTION INPUT ;
    USE SIGNAL ;
    PORT
      LAYER M4 ;
      RECT 0.00000 49.87200 0.03600 49.89600 ;
    END
  END wdata[286]
  PIN wdata[287]
    DIRECTION INPUT ;
    USE SIGNAL ;
    PORT
      LAYER M4 ;
      RECT 0.00000 49.92000 0.03600 49.94400 ;
    END
  END wdata[287]
  PIN wdata[288]
    DIRECTION INPUT ;
    USE SIGNAL ;
    PORT
      LAYER M4 ;
      RECT 0.00000 49.96800 0.03600 49.99200 ;
    END
  END wdata[288]
  PIN wdata[289]
    DIRECTION INPUT ;
    USE SIGNAL ;
    PORT
      LAYER M4 ;
      RECT 0.00000 50.01600 0.03600 50.04000 ;
    END
  END wdata[289]
  PIN wdata[290]
    DIRECTION INPUT ;
    USE SIGNAL ;
    PORT
      LAYER M4 ;
      RECT 0.00000 50.06400 0.03600 50.08800 ;
    END
  END wdata[290]
  PIN wdata[291]
    DIRECTION INPUT ;
    USE SIGNAL ;
    PORT
      LAYER M4 ;
      RECT 0.00000 50.11200 0.03600 50.13600 ;
    END
  END wdata[291]
  PIN wdata[292]
    DIRECTION INPUT ;
    USE SIGNAL ;
    PORT
      LAYER M4 ;
      RECT 0.00000 50.16000 0.03600 50.18400 ;
    END
  END wdata[292]
  PIN wdata[293]
    DIRECTION INPUT ;
    USE SIGNAL ;
    PORT
      LAYER M4 ;
      RECT 0.00000 50.20800 0.03600 50.23200 ;
    END
  END wdata[293]
  PIN wdata[294]
    DIRECTION INPUT ;
    USE SIGNAL ;
    PORT
      LAYER M4 ;
      RECT 0.00000 50.25600 0.03600 50.28000 ;
    END
  END wdata[294]
  PIN wdata[295]
    DIRECTION INPUT ;
    USE SIGNAL ;
    PORT
      LAYER M4 ;
      RECT 0.00000 50.30400 0.03600 50.32800 ;
    END
  END wdata[295]
  PIN wdata[296]
    DIRECTION INPUT ;
    USE SIGNAL ;
    PORT
      LAYER M4 ;
      RECT 0.00000 50.35200 0.03600 50.37600 ;
    END
  END wdata[296]
  PIN wdata[297]
    DIRECTION INPUT ;
    USE SIGNAL ;
    PORT
      LAYER M4 ;
      RECT 0.00000 50.40000 0.03600 50.42400 ;
    END
  END wdata[297]
  PIN wdata[298]
    DIRECTION INPUT ;
    USE SIGNAL ;
    PORT
      LAYER M4 ;
      RECT 0.00000 50.44800 0.03600 50.47200 ;
    END
  END wdata[298]
  PIN wdata[299]
    DIRECTION INPUT ;
    USE SIGNAL ;
    PORT
      LAYER M4 ;
      RECT 0.00000 50.49600 0.03600 50.52000 ;
    END
  END wdata[299]
  PIN wdata[300]
    DIRECTION INPUT ;
    USE SIGNAL ;
    PORT
      LAYER M4 ;
      RECT 0.00000 50.54400 0.03600 50.56800 ;
    END
  END wdata[300]
  PIN wdata[301]
    DIRECTION INPUT ;
    USE SIGNAL ;
    PORT
      LAYER M4 ;
      RECT 0.00000 50.59200 0.03600 50.61600 ;
    END
  END wdata[301]
  PIN wdata[302]
    DIRECTION INPUT ;
    USE SIGNAL ;
    PORT
      LAYER M4 ;
      RECT 0.00000 50.64000 0.03600 50.66400 ;
    END
  END wdata[302]
  PIN wdata[303]
    DIRECTION INPUT ;
    USE SIGNAL ;
    PORT
      LAYER M4 ;
      RECT 0.00000 50.68800 0.03600 50.71200 ;
    END
  END wdata[303]
  PIN wdata[304]
    DIRECTION INPUT ;
    USE SIGNAL ;
    PORT
      LAYER M4 ;
      RECT 0.00000 50.73600 0.03600 50.76000 ;
    END
  END wdata[304]
  PIN wdata[305]
    DIRECTION INPUT ;
    USE SIGNAL ;
    PORT
      LAYER M4 ;
      RECT 0.00000 50.78400 0.03600 50.80800 ;
    END
  END wdata[305]
  PIN wdata[306]
    DIRECTION INPUT ;
    USE SIGNAL ;
    PORT
      LAYER M4 ;
      RECT 0.00000 50.83200 0.03600 50.85600 ;
    END
  END wdata[306]
  PIN wdata[307]
    DIRECTION INPUT ;
    USE SIGNAL ;
    PORT
      LAYER M4 ;
      RECT 0.00000 50.88000 0.03600 50.90400 ;
    END
  END wdata[307]
  PIN wdata[308]
    DIRECTION INPUT ;
    USE SIGNAL ;
    PORT
      LAYER M4 ;
      RECT 0.00000 50.92800 0.03600 50.95200 ;
    END
  END wdata[308]
  PIN wdata[309]
    DIRECTION INPUT ;
    USE SIGNAL ;
    PORT
      LAYER M4 ;
      RECT 0.00000 50.97600 0.03600 51.00000 ;
    END
  END wdata[309]
  PIN wdata[310]
    DIRECTION INPUT ;
    USE SIGNAL ;
    PORT
      LAYER M4 ;
      RECT 0.00000 51.02400 0.03600 51.04800 ;
    END
  END wdata[310]
  PIN wdata[311]
    DIRECTION INPUT ;
    USE SIGNAL ;
    PORT
      LAYER M4 ;
      RECT 0.00000 51.07200 0.03600 51.09600 ;
    END
  END wdata[311]
  PIN wdata[312]
    DIRECTION INPUT ;
    USE SIGNAL ;
    PORT
      LAYER M4 ;
      RECT 0.00000 51.12000 0.03600 51.14400 ;
    END
  END wdata[312]
  PIN wdata[313]
    DIRECTION INPUT ;
    USE SIGNAL ;
    PORT
      LAYER M4 ;
      RECT 0.00000 51.16800 0.03600 51.19200 ;
    END
  END wdata[313]
  PIN wdata[314]
    DIRECTION INPUT ;
    USE SIGNAL ;
    PORT
      LAYER M4 ;
      RECT 0.00000 51.21600 0.03600 51.24000 ;
    END
  END wdata[314]
  PIN wdata[315]
    DIRECTION INPUT ;
    USE SIGNAL ;
    PORT
      LAYER M4 ;
      RECT 0.00000 51.26400 0.03600 51.28800 ;
    END
  END wdata[315]
  PIN wdata[316]
    DIRECTION INPUT ;
    USE SIGNAL ;
    PORT
      LAYER M4 ;
      RECT 0.00000 51.31200 0.03600 51.33600 ;
    END
  END wdata[316]
  PIN wdata[317]
    DIRECTION INPUT ;
    USE SIGNAL ;
    PORT
      LAYER M4 ;
      RECT 0.00000 51.36000 0.03600 51.38400 ;
    END
  END wdata[317]
  PIN wdata[318]
    DIRECTION INPUT ;
    USE SIGNAL ;
    PORT
      LAYER M4 ;
      RECT 0.00000 51.40800 0.03600 51.43200 ;
    END
  END wdata[318]
  PIN wdata[319]
    DIRECTION INPUT ;
    USE SIGNAL ;
    PORT
      LAYER M4 ;
      RECT 0.00000 51.45600 0.03600 51.48000 ;
    END
  END wdata[319]
  PIN wdata[320]
    DIRECTION INPUT ;
    USE SIGNAL ;
    PORT
      LAYER M4 ;
      RECT 0.00000 51.50400 0.03600 51.52800 ;
    END
  END wdata[320]
  PIN wdata[321]
    DIRECTION INPUT ;
    USE SIGNAL ;
    PORT
      LAYER M4 ;
      RECT 0.00000 51.55200 0.03600 51.57600 ;
    END
  END wdata[321]
  PIN wdata[322]
    DIRECTION INPUT ;
    USE SIGNAL ;
    PORT
      LAYER M4 ;
      RECT 0.00000 51.60000 0.03600 51.62400 ;
    END
  END wdata[322]
  PIN wdata[323]
    DIRECTION INPUT ;
    USE SIGNAL ;
    PORT
      LAYER M4 ;
      RECT 0.00000 51.64800 0.03600 51.67200 ;
    END
  END wdata[323]
  PIN wdata[324]
    DIRECTION INPUT ;
    USE SIGNAL ;
    PORT
      LAYER M4 ;
      RECT 0.00000 51.69600 0.03600 51.72000 ;
    END
  END wdata[324]
  PIN wdata[325]
    DIRECTION INPUT ;
    USE SIGNAL ;
    PORT
      LAYER M4 ;
      RECT 0.00000 51.74400 0.03600 51.76800 ;
    END
  END wdata[325]
  PIN wdata[326]
    DIRECTION INPUT ;
    USE SIGNAL ;
    PORT
      LAYER M4 ;
      RECT 0.00000 51.79200 0.03600 51.81600 ;
    END
  END wdata[326]
  PIN wdata[327]
    DIRECTION INPUT ;
    USE SIGNAL ;
    PORT
      LAYER M4 ;
      RECT 0.00000 51.84000 0.03600 51.86400 ;
    END
  END wdata[327]
  PIN wdata[328]
    DIRECTION INPUT ;
    USE SIGNAL ;
    PORT
      LAYER M4 ;
      RECT 0.00000 51.88800 0.03600 51.91200 ;
    END
  END wdata[328]
  PIN wdata[329]
    DIRECTION INPUT ;
    USE SIGNAL ;
    PORT
      LAYER M4 ;
      RECT 0.00000 51.93600 0.03600 51.96000 ;
    END
  END wdata[329]
  PIN wdata[330]
    DIRECTION INPUT ;
    USE SIGNAL ;
    PORT
      LAYER M4 ;
      RECT 0.00000 51.98400 0.03600 52.00800 ;
    END
  END wdata[330]
  PIN wdata[331]
    DIRECTION INPUT ;
    USE SIGNAL ;
    PORT
      LAYER M4 ;
      RECT 0.00000 52.03200 0.03600 52.05600 ;
    END
  END wdata[331]
  PIN wdata[332]
    DIRECTION INPUT ;
    USE SIGNAL ;
    PORT
      LAYER M4 ;
      RECT 0.00000 52.08000 0.03600 52.10400 ;
    END
  END wdata[332]
  PIN wdata[333]
    DIRECTION INPUT ;
    USE SIGNAL ;
    PORT
      LAYER M4 ;
      RECT 0.00000 52.12800 0.03600 52.15200 ;
    END
  END wdata[333]
  PIN wdata[334]
    DIRECTION INPUT ;
    USE SIGNAL ;
    PORT
      LAYER M4 ;
      RECT 0.00000 52.17600 0.03600 52.20000 ;
    END
  END wdata[334]
  PIN wdata[335]
    DIRECTION INPUT ;
    USE SIGNAL ;
    PORT
      LAYER M4 ;
      RECT 0.00000 52.22400 0.03600 52.24800 ;
    END
  END wdata[335]
  PIN wdata[336]
    DIRECTION INPUT ;
    USE SIGNAL ;
    PORT
      LAYER M4 ;
      RECT 0.00000 52.27200 0.03600 52.29600 ;
    END
  END wdata[336]
  PIN wdata[337]
    DIRECTION INPUT ;
    USE SIGNAL ;
    PORT
      LAYER M4 ;
      RECT 0.00000 52.32000 0.03600 52.34400 ;
    END
  END wdata[337]
  PIN wdata[338]
    DIRECTION INPUT ;
    USE SIGNAL ;
    PORT
      LAYER M4 ;
      RECT 0.00000 52.36800 0.03600 52.39200 ;
    END
  END wdata[338]
  PIN wdata[339]
    DIRECTION INPUT ;
    USE SIGNAL ;
    PORT
      LAYER M4 ;
      RECT 0.00000 52.41600 0.03600 52.44000 ;
    END
  END wdata[339]
  PIN wdata[340]
    DIRECTION INPUT ;
    USE SIGNAL ;
    PORT
      LAYER M4 ;
      RECT 0.00000 52.46400 0.03600 52.48800 ;
    END
  END wdata[340]
  PIN wdata[341]
    DIRECTION INPUT ;
    USE SIGNAL ;
    PORT
      LAYER M4 ;
      RECT 0.00000 52.51200 0.03600 52.53600 ;
    END
  END wdata[341]
  PIN wdata[342]
    DIRECTION INPUT ;
    USE SIGNAL ;
    PORT
      LAYER M4 ;
      RECT 0.00000 52.56000 0.03600 52.58400 ;
    END
  END wdata[342]
  PIN wdata[343]
    DIRECTION INPUT ;
    USE SIGNAL ;
    PORT
      LAYER M4 ;
      RECT 0.00000 52.60800 0.03600 52.63200 ;
    END
  END wdata[343]
  PIN wdata[344]
    DIRECTION INPUT ;
    USE SIGNAL ;
    PORT
      LAYER M4 ;
      RECT 0.00000 52.65600 0.03600 52.68000 ;
    END
  END wdata[344]
  PIN wdata[345]
    DIRECTION INPUT ;
    USE SIGNAL ;
    PORT
      LAYER M4 ;
      RECT 0.00000 52.70400 0.03600 52.72800 ;
    END
  END wdata[345]
  PIN wdata[346]
    DIRECTION INPUT ;
    USE SIGNAL ;
    PORT
      LAYER M4 ;
      RECT 0.00000 52.75200 0.03600 52.77600 ;
    END
  END wdata[346]
  PIN wdata[347]
    DIRECTION INPUT ;
    USE SIGNAL ;
    PORT
      LAYER M4 ;
      RECT 0.00000 52.80000 0.03600 52.82400 ;
    END
  END wdata[347]
  PIN wdata[348]
    DIRECTION INPUT ;
    USE SIGNAL ;
    PORT
      LAYER M4 ;
      RECT 0.00000 52.84800 0.03600 52.87200 ;
    END
  END wdata[348]
  PIN wdata[349]
    DIRECTION INPUT ;
    USE SIGNAL ;
    PORT
      LAYER M4 ;
      RECT 0.00000 52.89600 0.03600 52.92000 ;
    END
  END wdata[349]
  PIN wdata[350]
    DIRECTION INPUT ;
    USE SIGNAL ;
    PORT
      LAYER M4 ;
      RECT 0.00000 52.94400 0.03600 52.96800 ;
    END
  END wdata[350]
  PIN wdata[351]
    DIRECTION INPUT ;
    USE SIGNAL ;
    PORT
      LAYER M4 ;
      RECT 0.00000 52.99200 0.03600 53.01600 ;
    END
  END wdata[351]
  PIN wdata[352]
    DIRECTION INPUT ;
    USE SIGNAL ;
    PORT
      LAYER M4 ;
      RECT 0.00000 53.04000 0.03600 53.06400 ;
    END
  END wdata[352]
  PIN wdata[353]
    DIRECTION INPUT ;
    USE SIGNAL ;
    PORT
      LAYER M4 ;
      RECT 0.00000 53.08800 0.03600 53.11200 ;
    END
  END wdata[353]
  PIN wdata[354]
    DIRECTION INPUT ;
    USE SIGNAL ;
    PORT
      LAYER M4 ;
      RECT 0.00000 53.13600 0.03600 53.16000 ;
    END
  END wdata[354]
  PIN wdata[355]
    DIRECTION INPUT ;
    USE SIGNAL ;
    PORT
      LAYER M4 ;
      RECT 0.00000 53.18400 0.03600 53.20800 ;
    END
  END wdata[355]
  PIN wdata[356]
    DIRECTION INPUT ;
    USE SIGNAL ;
    PORT
      LAYER M4 ;
      RECT 0.00000 53.23200 0.03600 53.25600 ;
    END
  END wdata[356]
  PIN wdata[357]
    DIRECTION INPUT ;
    USE SIGNAL ;
    PORT
      LAYER M4 ;
      RECT 0.00000 53.28000 0.03600 53.30400 ;
    END
  END wdata[357]
  PIN wdata[358]
    DIRECTION INPUT ;
    USE SIGNAL ;
    PORT
      LAYER M4 ;
      RECT 0.00000 53.32800 0.03600 53.35200 ;
    END
  END wdata[358]
  PIN wdata[359]
    DIRECTION INPUT ;
    USE SIGNAL ;
    PORT
      LAYER M4 ;
      RECT 0.00000 53.37600 0.03600 53.40000 ;
    END
  END wdata[359]
  PIN wdata[360]
    DIRECTION INPUT ;
    USE SIGNAL ;
    PORT
      LAYER M4 ;
      RECT 0.00000 53.42400 0.03600 53.44800 ;
    END
  END wdata[360]
  PIN wdata[361]
    DIRECTION INPUT ;
    USE SIGNAL ;
    PORT
      LAYER M4 ;
      RECT 0.00000 53.47200 0.03600 53.49600 ;
    END
  END wdata[361]
  PIN wdata[362]
    DIRECTION INPUT ;
    USE SIGNAL ;
    PORT
      LAYER M4 ;
      RECT 0.00000 53.52000 0.03600 53.54400 ;
    END
  END wdata[362]
  PIN wdata[363]
    DIRECTION INPUT ;
    USE SIGNAL ;
    PORT
      LAYER M4 ;
      RECT 0.00000 53.56800 0.03600 53.59200 ;
    END
  END wdata[363]
  PIN wdata[364]
    DIRECTION INPUT ;
    USE SIGNAL ;
    PORT
      LAYER M4 ;
      RECT 0.00000 53.61600 0.03600 53.64000 ;
    END
  END wdata[364]
  PIN wdata[365]
    DIRECTION INPUT ;
    USE SIGNAL ;
    PORT
      LAYER M4 ;
      RECT 0.00000 53.66400 0.03600 53.68800 ;
    END
  END wdata[365]
  PIN wdata[366]
    DIRECTION INPUT ;
    USE SIGNAL ;
    PORT
      LAYER M4 ;
      RECT 0.00000 53.71200 0.03600 53.73600 ;
    END
  END wdata[366]
  PIN wdata[367]
    DIRECTION INPUT ;
    USE SIGNAL ;
    PORT
      LAYER M4 ;
      RECT 0.00000 53.76000 0.03600 53.78400 ;
    END
  END wdata[367]
  PIN wdata[368]
    DIRECTION INPUT ;
    USE SIGNAL ;
    PORT
      LAYER M4 ;
      RECT 0.00000 53.80800 0.03600 53.83200 ;
    END
  END wdata[368]
  PIN wdata[369]
    DIRECTION INPUT ;
    USE SIGNAL ;
    PORT
      LAYER M4 ;
      RECT 0.00000 53.85600 0.03600 53.88000 ;
    END
  END wdata[369]
  PIN wdata[370]
    DIRECTION INPUT ;
    USE SIGNAL ;
    PORT
      LAYER M4 ;
      RECT 0.00000 53.90400 0.03600 53.92800 ;
    END
  END wdata[370]
  PIN wdata[371]
    DIRECTION INPUT ;
    USE SIGNAL ;
    PORT
      LAYER M4 ;
      RECT 0.00000 53.95200 0.03600 53.97600 ;
    END
  END wdata[371]
  PIN wdata[372]
    DIRECTION INPUT ;
    USE SIGNAL ;
    PORT
      LAYER M4 ;
      RECT 0.00000 54.00000 0.03600 54.02400 ;
    END
  END wdata[372]
  PIN wdata[373]
    DIRECTION INPUT ;
    USE SIGNAL ;
    PORT
      LAYER M4 ;
      RECT 0.00000 54.04800 0.03600 54.07200 ;
    END
  END wdata[373]
  PIN wdata[374]
    DIRECTION INPUT ;
    USE SIGNAL ;
    PORT
      LAYER M4 ;
      RECT 0.00000 54.09600 0.03600 54.12000 ;
    END
  END wdata[374]
  PIN wdata[375]
    DIRECTION INPUT ;
    USE SIGNAL ;
    PORT
      LAYER M4 ;
      RECT 0.00000 54.14400 0.03600 54.16800 ;
    END
  END wdata[375]
  PIN wdata[376]
    DIRECTION INPUT ;
    USE SIGNAL ;
    PORT
      LAYER M4 ;
      RECT 0.00000 54.19200 0.03600 54.21600 ;
    END
  END wdata[376]
  PIN wdata[377]
    DIRECTION INPUT ;
    USE SIGNAL ;
    PORT
      LAYER M4 ;
      RECT 0.00000 54.24000 0.03600 54.26400 ;
    END
  END wdata[377]
  PIN wdata[378]
    DIRECTION INPUT ;
    USE SIGNAL ;
    PORT
      LAYER M4 ;
      RECT 0.00000 54.28800 0.03600 54.31200 ;
    END
  END wdata[378]
  PIN wdata[379]
    DIRECTION INPUT ;
    USE SIGNAL ;
    PORT
      LAYER M4 ;
      RECT 0.00000 54.33600 0.03600 54.36000 ;
    END
  END wdata[379]
  PIN wdata[380]
    DIRECTION INPUT ;
    USE SIGNAL ;
    PORT
      LAYER M4 ;
      RECT 0.00000 54.38400 0.03600 54.40800 ;
    END
  END wdata[380]
  PIN wdata[381]
    DIRECTION INPUT ;
    USE SIGNAL ;
    PORT
      LAYER M4 ;
      RECT 0.00000 54.43200 0.03600 54.45600 ;
    END
  END wdata[381]
  PIN wdata[382]
    DIRECTION INPUT ;
    USE SIGNAL ;
    PORT
      LAYER M4 ;
      RECT 0.00000 54.48000 0.03600 54.50400 ;
    END
  END wdata[382]
  PIN wdata[383]
    DIRECTION INPUT ;
    USE SIGNAL ;
    PORT
      LAYER M4 ;
      RECT 0.00000 54.52800 0.03600 54.55200 ;
    END
  END wdata[383]
  PIN wdata[384]
    DIRECTION INPUT ;
    USE SIGNAL ;
    PORT
      LAYER M4 ;
      RECT 0.00000 54.57600 0.03600 54.60000 ;
    END
  END wdata[384]
  PIN wdata[385]
    DIRECTION INPUT ;
    USE SIGNAL ;
    PORT
      LAYER M4 ;
      RECT 0.00000 54.62400 0.03600 54.64800 ;
    END
  END wdata[385]
  PIN wdata[386]
    DIRECTION INPUT ;
    USE SIGNAL ;
    PORT
      LAYER M4 ;
      RECT 0.00000 54.67200 0.03600 54.69600 ;
    END
  END wdata[386]
  PIN wdata[387]
    DIRECTION INPUT ;
    USE SIGNAL ;
    PORT
      LAYER M4 ;
      RECT 0.00000 54.72000 0.03600 54.74400 ;
    END
  END wdata[387]
  PIN wdata[388]
    DIRECTION INPUT ;
    USE SIGNAL ;
    PORT
      LAYER M4 ;
      RECT 0.00000 54.76800 0.03600 54.79200 ;
    END
  END wdata[388]
  PIN wdata[389]
    DIRECTION INPUT ;
    USE SIGNAL ;
    PORT
      LAYER M4 ;
      RECT 0.00000 54.81600 0.03600 54.84000 ;
    END
  END wdata[389]
  PIN wdata[390]
    DIRECTION INPUT ;
    USE SIGNAL ;
    PORT
      LAYER M4 ;
      RECT 0.00000 54.86400 0.03600 54.88800 ;
    END
  END wdata[390]
  PIN wdata[391]
    DIRECTION INPUT ;
    USE SIGNAL ;
    PORT
      LAYER M4 ;
      RECT 0.00000 54.91200 0.03600 54.93600 ;
    END
  END wdata[391]
  PIN wdata[392]
    DIRECTION INPUT ;
    USE SIGNAL ;
    PORT
      LAYER M4 ;
      RECT 0.00000 54.96000 0.03600 54.98400 ;
    END
  END wdata[392]
  PIN wdata[393]
    DIRECTION INPUT ;
    USE SIGNAL ;
    PORT
      LAYER M4 ;
      RECT 0.00000 55.00800 0.03600 55.03200 ;
    END
  END wdata[393]
  PIN wdata[394]
    DIRECTION INPUT ;
    USE SIGNAL ;
    PORT
      LAYER M4 ;
      RECT 0.00000 55.05600 0.03600 55.08000 ;
    END
  END wdata[394]
  PIN wdata[395]
    DIRECTION INPUT ;
    USE SIGNAL ;
    PORT
      LAYER M4 ;
      RECT 0.00000 55.10400 0.03600 55.12800 ;
    END
  END wdata[395]
  PIN wdata[396]
    DIRECTION INPUT ;
    USE SIGNAL ;
    PORT
      LAYER M4 ;
      RECT 0.00000 55.15200 0.03600 55.17600 ;
    END
  END wdata[396]
  PIN wdata[397]
    DIRECTION INPUT ;
    USE SIGNAL ;
    PORT
      LAYER M4 ;
      RECT 0.00000 55.20000 0.03600 55.22400 ;
    END
  END wdata[397]
  PIN wdata[398]
    DIRECTION INPUT ;
    USE SIGNAL ;
    PORT
      LAYER M4 ;
      RECT 0.00000 55.24800 0.03600 55.27200 ;
    END
  END wdata[398]
  PIN wdata[399]
    DIRECTION INPUT ;
    USE SIGNAL ;
    PORT
      LAYER M4 ;
      RECT 0.00000 55.29600 0.03600 55.32000 ;
    END
  END wdata[399]
  PIN wdata[400]
    DIRECTION INPUT ;
    USE SIGNAL ;
    PORT
      LAYER M4 ;
      RECT 0.00000 55.34400 0.03600 55.36800 ;
    END
  END wdata[400]
  PIN wdata[401]
    DIRECTION INPUT ;
    USE SIGNAL ;
    PORT
      LAYER M4 ;
      RECT 0.00000 55.39200 0.03600 55.41600 ;
    END
  END wdata[401]
  PIN wdata[402]
    DIRECTION INPUT ;
    USE SIGNAL ;
    PORT
      LAYER M4 ;
      RECT 0.00000 55.44000 0.03600 55.46400 ;
    END
  END wdata[402]
  PIN wdata[403]
    DIRECTION INPUT ;
    USE SIGNAL ;
    PORT
      LAYER M4 ;
      RECT 0.00000 55.48800 0.03600 55.51200 ;
    END
  END wdata[403]
  PIN wdata[404]
    DIRECTION INPUT ;
    USE SIGNAL ;
    PORT
      LAYER M4 ;
      RECT 0.00000 55.53600 0.03600 55.56000 ;
    END
  END wdata[404]
  PIN wdata[405]
    DIRECTION INPUT ;
    USE SIGNAL ;
    PORT
      LAYER M4 ;
      RECT 0.00000 55.58400 0.03600 55.60800 ;
    END
  END wdata[405]
  PIN wdata[406]
    DIRECTION INPUT ;
    USE SIGNAL ;
    PORT
      LAYER M4 ;
      RECT 0.00000 55.63200 0.03600 55.65600 ;
    END
  END wdata[406]
  PIN wdata[407]
    DIRECTION INPUT ;
    USE SIGNAL ;
    PORT
      LAYER M4 ;
      RECT 0.00000 55.68000 0.03600 55.70400 ;
    END
  END wdata[407]
  PIN wdata[408]
    DIRECTION INPUT ;
    USE SIGNAL ;
    PORT
      LAYER M4 ;
      RECT 0.00000 55.72800 0.03600 55.75200 ;
    END
  END wdata[408]
  PIN wdata[409]
    DIRECTION INPUT ;
    USE SIGNAL ;
    PORT
      LAYER M4 ;
      RECT 0.00000 55.77600 0.03600 55.80000 ;
    END
  END wdata[409]
  PIN wdata[410]
    DIRECTION INPUT ;
    USE SIGNAL ;
    PORT
      LAYER M4 ;
      RECT 0.00000 55.82400 0.03600 55.84800 ;
    END
  END wdata[410]
  PIN wdata[411]
    DIRECTION INPUT ;
    USE SIGNAL ;
    PORT
      LAYER M4 ;
      RECT 0.00000 55.87200 0.03600 55.89600 ;
    END
  END wdata[411]
  PIN wdata[412]
    DIRECTION INPUT ;
    USE SIGNAL ;
    PORT
      LAYER M4 ;
      RECT 0.00000 55.92000 0.03600 55.94400 ;
    END
  END wdata[412]
  PIN wdata[413]
    DIRECTION INPUT ;
    USE SIGNAL ;
    PORT
      LAYER M4 ;
      RECT 0.00000 55.96800 0.03600 55.99200 ;
    END
  END wdata[413]
  PIN wdata[414]
    DIRECTION INPUT ;
    USE SIGNAL ;
    PORT
      LAYER M4 ;
      RECT 0.00000 56.01600 0.03600 56.04000 ;
    END
  END wdata[414]
  PIN wdata[415]
    DIRECTION INPUT ;
    USE SIGNAL ;
    PORT
      LAYER M4 ;
      RECT 0.00000 56.06400 0.03600 56.08800 ;
    END
  END wdata[415]
  PIN wdata[416]
    DIRECTION INPUT ;
    USE SIGNAL ;
    PORT
      LAYER M4 ;
      RECT 0.00000 56.11200 0.03600 56.13600 ;
    END
  END wdata[416]
  PIN wdata[417]
    DIRECTION INPUT ;
    USE SIGNAL ;
    PORT
      LAYER M4 ;
      RECT 0.00000 56.16000 0.03600 56.18400 ;
    END
  END wdata[417]
  PIN wdata[418]
    DIRECTION INPUT ;
    USE SIGNAL ;
    PORT
      LAYER M4 ;
      RECT 0.00000 56.20800 0.03600 56.23200 ;
    END
  END wdata[418]
  PIN wdata[419]
    DIRECTION INPUT ;
    USE SIGNAL ;
    PORT
      LAYER M4 ;
      RECT 0.00000 56.25600 0.03600 56.28000 ;
    END
  END wdata[419]
  PIN wdata[420]
    DIRECTION INPUT ;
    USE SIGNAL ;
    PORT
      LAYER M4 ;
      RECT 0.00000 56.30400 0.03600 56.32800 ;
    END
  END wdata[420]
  PIN wdata[421]
    DIRECTION INPUT ;
    USE SIGNAL ;
    PORT
      LAYER M4 ;
      RECT 0.00000 56.35200 0.03600 56.37600 ;
    END
  END wdata[421]
  PIN wdata[422]
    DIRECTION INPUT ;
    USE SIGNAL ;
    PORT
      LAYER M4 ;
      RECT 0.00000 56.40000 0.03600 56.42400 ;
    END
  END wdata[422]
  PIN wdata[423]
    DIRECTION INPUT ;
    USE SIGNAL ;
    PORT
      LAYER M4 ;
      RECT 0.00000 56.44800 0.03600 56.47200 ;
    END
  END wdata[423]
  PIN wdata[424]
    DIRECTION INPUT ;
    USE SIGNAL ;
    PORT
      LAYER M4 ;
      RECT 0.00000 56.49600 0.03600 56.52000 ;
    END
  END wdata[424]
  PIN wdata[425]
    DIRECTION INPUT ;
    USE SIGNAL ;
    PORT
      LAYER M4 ;
      RECT 0.00000 56.54400 0.03600 56.56800 ;
    END
  END wdata[425]
  PIN wdata[426]
    DIRECTION INPUT ;
    USE SIGNAL ;
    PORT
      LAYER M4 ;
      RECT 0.00000 56.59200 0.03600 56.61600 ;
    END
  END wdata[426]
  PIN wdata[427]
    DIRECTION INPUT ;
    USE SIGNAL ;
    PORT
      LAYER M4 ;
      RECT 0.00000 56.64000 0.03600 56.66400 ;
    END
  END wdata[427]
  PIN wdata[428]
    DIRECTION INPUT ;
    USE SIGNAL ;
    PORT
      LAYER M4 ;
      RECT 0.00000 56.68800 0.03600 56.71200 ;
    END
  END wdata[428]
  PIN wdata[429]
    DIRECTION INPUT ;
    USE SIGNAL ;
    PORT
      LAYER M4 ;
      RECT 0.00000 56.73600 0.03600 56.76000 ;
    END
  END wdata[429]
  PIN wdata[430]
    DIRECTION INPUT ;
    USE SIGNAL ;
    PORT
      LAYER M4 ;
      RECT 0.00000 56.78400 0.03600 56.80800 ;
    END
  END wdata[430]
  PIN wdata[431]
    DIRECTION INPUT ;
    USE SIGNAL ;
    PORT
      LAYER M4 ;
      RECT 0.00000 56.83200 0.03600 56.85600 ;
    END
  END wdata[431]
  PIN wdata[432]
    DIRECTION INPUT ;
    USE SIGNAL ;
    PORT
      LAYER M4 ;
      RECT 0.00000 56.88000 0.03600 56.90400 ;
    END
  END wdata[432]
  PIN wdata[433]
    DIRECTION INPUT ;
    USE SIGNAL ;
    PORT
      LAYER M4 ;
      RECT 0.00000 56.92800 0.03600 56.95200 ;
    END
  END wdata[433]
  PIN wdata[434]
    DIRECTION INPUT ;
    USE SIGNAL ;
    PORT
      LAYER M4 ;
      RECT 0.00000 56.97600 0.03600 57.00000 ;
    END
  END wdata[434]
  PIN wdata[435]
    DIRECTION INPUT ;
    USE SIGNAL ;
    PORT
      LAYER M4 ;
      RECT 0.00000 57.02400 0.03600 57.04800 ;
    END
  END wdata[435]
  PIN wdata[436]
    DIRECTION INPUT ;
    USE SIGNAL ;
    PORT
      LAYER M4 ;
      RECT 0.00000 57.07200 0.03600 57.09600 ;
    END
  END wdata[436]
  PIN wdata[437]
    DIRECTION INPUT ;
    USE SIGNAL ;
    PORT
      LAYER M4 ;
      RECT 0.00000 57.12000 0.03600 57.14400 ;
    END
  END wdata[437]
  PIN wdata[438]
    DIRECTION INPUT ;
    USE SIGNAL ;
    PORT
      LAYER M4 ;
      RECT 0.00000 57.16800 0.03600 57.19200 ;
    END
  END wdata[438]
  PIN wdata[439]
    DIRECTION INPUT ;
    USE SIGNAL ;
    PORT
      LAYER M4 ;
      RECT 0.00000 57.21600 0.03600 57.24000 ;
    END
  END wdata[439]
  PIN wdata[440]
    DIRECTION INPUT ;
    USE SIGNAL ;
    PORT
      LAYER M4 ;
      RECT 0.00000 57.26400 0.03600 57.28800 ;
    END
  END wdata[440]
  PIN wdata[441]
    DIRECTION INPUT ;
    USE SIGNAL ;
    PORT
      LAYER M4 ;
      RECT 0.00000 57.31200 0.03600 57.33600 ;
    END
  END wdata[441]
  PIN wdata[442]
    DIRECTION INPUT ;
    USE SIGNAL ;
    PORT
      LAYER M4 ;
      RECT 0.00000 57.36000 0.03600 57.38400 ;
    END
  END wdata[442]
  PIN wdata[443]
    DIRECTION INPUT ;
    USE SIGNAL ;
    PORT
      LAYER M4 ;
      RECT 0.00000 57.40800 0.03600 57.43200 ;
    END
  END wdata[443]
  PIN wdata[444]
    DIRECTION INPUT ;
    USE SIGNAL ;
    PORT
      LAYER M4 ;
      RECT 0.00000 57.45600 0.03600 57.48000 ;
    END
  END wdata[444]
  PIN wdata[445]
    DIRECTION INPUT ;
    USE SIGNAL ;
    PORT
      LAYER M4 ;
      RECT 0.00000 57.50400 0.03600 57.52800 ;
    END
  END wdata[445]
  PIN wdata[446]
    DIRECTION INPUT ;
    USE SIGNAL ;
    PORT
      LAYER M4 ;
      RECT 0.00000 57.55200 0.03600 57.57600 ;
    END
  END wdata[446]
  PIN wdata[447]
    DIRECTION INPUT ;
    USE SIGNAL ;
    PORT
      LAYER M4 ;
      RECT 0.00000 57.60000 0.03600 57.62400 ;
    END
  END wdata[447]
  PIN wdata[448]
    DIRECTION INPUT ;
    USE SIGNAL ;
    PORT
      LAYER M4 ;
      RECT 0.00000 57.64800 0.03600 57.67200 ;
    END
  END wdata[448]
  PIN wdata[449]
    DIRECTION INPUT ;
    USE SIGNAL ;
    PORT
      LAYER M4 ;
      RECT 0.00000 57.69600 0.03600 57.72000 ;
    END
  END wdata[449]
  PIN wdata[450]
    DIRECTION INPUT ;
    USE SIGNAL ;
    PORT
      LAYER M4 ;
      RECT 0.00000 57.74400 0.03600 57.76800 ;
    END
  END wdata[450]
  PIN wdata[451]
    DIRECTION INPUT ;
    USE SIGNAL ;
    PORT
      LAYER M4 ;
      RECT 0.00000 57.79200 0.03600 57.81600 ;
    END
  END wdata[451]
  PIN wdata[452]
    DIRECTION INPUT ;
    USE SIGNAL ;
    PORT
      LAYER M4 ;
      RECT 0.00000 57.84000 0.03600 57.86400 ;
    END
  END wdata[452]
  PIN wdata[453]
    DIRECTION INPUT ;
    USE SIGNAL ;
    PORT
      LAYER M4 ;
      RECT 0.00000 57.88800 0.03600 57.91200 ;
    END
  END wdata[453]
  PIN wdata[454]
    DIRECTION INPUT ;
    USE SIGNAL ;
    PORT
      LAYER M4 ;
      RECT 0.00000 57.93600 0.03600 57.96000 ;
    END
  END wdata[454]
  PIN wdata[455]
    DIRECTION INPUT ;
    USE SIGNAL ;
    PORT
      LAYER M4 ;
      RECT 0.00000 57.98400 0.03600 58.00800 ;
    END
  END wdata[455]
  PIN wdata[456]
    DIRECTION INPUT ;
    USE SIGNAL ;
    PORT
      LAYER M4 ;
      RECT 0.00000 58.03200 0.03600 58.05600 ;
    END
  END wdata[456]
  PIN wdata[457]
    DIRECTION INPUT ;
    USE SIGNAL ;
    PORT
      LAYER M4 ;
      RECT 0.00000 58.08000 0.03600 58.10400 ;
    END
  END wdata[457]
  PIN wdata[458]
    DIRECTION INPUT ;
    USE SIGNAL ;
    PORT
      LAYER M4 ;
      RECT 0.00000 58.12800 0.03600 58.15200 ;
    END
  END wdata[458]
  PIN wdata[459]
    DIRECTION INPUT ;
    USE SIGNAL ;
    PORT
      LAYER M4 ;
      RECT 0.00000 58.17600 0.03600 58.20000 ;
    END
  END wdata[459]
  PIN wdata[460]
    DIRECTION INPUT ;
    USE SIGNAL ;
    PORT
      LAYER M4 ;
      RECT 0.00000 58.22400 0.03600 58.24800 ;
    END
  END wdata[460]
  PIN wdata[461]
    DIRECTION INPUT ;
    USE SIGNAL ;
    PORT
      LAYER M4 ;
      RECT 0.00000 58.27200 0.03600 58.29600 ;
    END
  END wdata[461]
  PIN wdata[462]
    DIRECTION INPUT ;
    USE SIGNAL ;
    PORT
      LAYER M4 ;
      RECT 0.00000 58.32000 0.03600 58.34400 ;
    END
  END wdata[462]
  PIN wdata[463]
    DIRECTION INPUT ;
    USE SIGNAL ;
    PORT
      LAYER M4 ;
      RECT 0.00000 58.36800 0.03600 58.39200 ;
    END
  END wdata[463]
  PIN wdata[464]
    DIRECTION INPUT ;
    USE SIGNAL ;
    PORT
      LAYER M4 ;
      RECT 0.00000 58.41600 0.03600 58.44000 ;
    END
  END wdata[464]
  PIN wdata[465]
    DIRECTION INPUT ;
    USE SIGNAL ;
    PORT
      LAYER M4 ;
      RECT 0.00000 58.46400 0.03600 58.48800 ;
    END
  END wdata[465]
  PIN wdata[466]
    DIRECTION INPUT ;
    USE SIGNAL ;
    PORT
      LAYER M4 ;
      RECT 0.00000 58.51200 0.03600 58.53600 ;
    END
  END wdata[466]
  PIN wdata[467]
    DIRECTION INPUT ;
    USE SIGNAL ;
    PORT
      LAYER M4 ;
      RECT 0.00000 58.56000 0.03600 58.58400 ;
    END
  END wdata[467]
  PIN wdata[468]
    DIRECTION INPUT ;
    USE SIGNAL ;
    PORT
      LAYER M4 ;
      RECT 0.00000 58.60800 0.03600 58.63200 ;
    END
  END wdata[468]
  PIN wdata[469]
    DIRECTION INPUT ;
    USE SIGNAL ;
    PORT
      LAYER M4 ;
      RECT 0.00000 58.65600 0.03600 58.68000 ;
    END
  END wdata[469]
  PIN wdata[470]
    DIRECTION INPUT ;
    USE SIGNAL ;
    PORT
      LAYER M4 ;
      RECT 0.00000 58.70400 0.03600 58.72800 ;
    END
  END wdata[470]
  PIN wdata[471]
    DIRECTION INPUT ;
    USE SIGNAL ;
    PORT
      LAYER M4 ;
      RECT 0.00000 58.75200 0.03600 58.77600 ;
    END
  END wdata[471]
  PIN wdata[472]
    DIRECTION INPUT ;
    USE SIGNAL ;
    PORT
      LAYER M4 ;
      RECT 0.00000 58.80000 0.03600 58.82400 ;
    END
  END wdata[472]
  PIN wdata[473]
    DIRECTION INPUT ;
    USE SIGNAL ;
    PORT
      LAYER M4 ;
      RECT 0.00000 58.84800 0.03600 58.87200 ;
    END
  END wdata[473]
  PIN wdata[474]
    DIRECTION INPUT ;
    USE SIGNAL ;
    PORT
      LAYER M4 ;
      RECT 0.00000 58.89600 0.03600 58.92000 ;
    END
  END wdata[474]
  PIN wdata[475]
    DIRECTION INPUT ;
    USE SIGNAL ;
    PORT
      LAYER M4 ;
      RECT 0.00000 58.94400 0.03600 58.96800 ;
    END
  END wdata[475]
  PIN wdata[476]
    DIRECTION INPUT ;
    USE SIGNAL ;
    PORT
      LAYER M4 ;
      RECT 0.00000 58.99200 0.03600 59.01600 ;
    END
  END wdata[476]
  PIN wdata[477]
    DIRECTION INPUT ;
    USE SIGNAL ;
    PORT
      LAYER M4 ;
      RECT 0.00000 59.04000 0.03600 59.06400 ;
    END
  END wdata[477]
  PIN wdata[478]
    DIRECTION INPUT ;
    USE SIGNAL ;
    PORT
      LAYER M4 ;
      RECT 0.00000 59.08800 0.03600 59.11200 ;
    END
  END wdata[478]
  PIN wdata[479]
    DIRECTION INPUT ;
    USE SIGNAL ;
    PORT
      LAYER M4 ;
      RECT 0.00000 59.13600 0.03600 59.16000 ;
    END
  END wdata[479]
  PIN wdata[480]
    DIRECTION INPUT ;
    USE SIGNAL ;
    PORT
      LAYER M4 ;
      RECT 0.00000 59.18400 0.03600 59.20800 ;
    END
  END wdata[480]
  PIN wdata[481]
    DIRECTION INPUT ;
    USE SIGNAL ;
    PORT
      LAYER M4 ;
      RECT 0.00000 59.23200 0.03600 59.25600 ;
    END
  END wdata[481]
  PIN wdata[482]
    DIRECTION INPUT ;
    USE SIGNAL ;
    PORT
      LAYER M4 ;
      RECT 0.00000 59.28000 0.03600 59.30400 ;
    END
  END wdata[482]
  PIN wdata[483]
    DIRECTION INPUT ;
    USE SIGNAL ;
    PORT
      LAYER M4 ;
      RECT 0.00000 59.32800 0.03600 59.35200 ;
    END
  END wdata[483]
  PIN wdata[484]
    DIRECTION INPUT ;
    USE SIGNAL ;
    PORT
      LAYER M4 ;
      RECT 0.00000 59.37600 0.03600 59.40000 ;
    END
  END wdata[484]
  PIN wdata[485]
    DIRECTION INPUT ;
    USE SIGNAL ;
    PORT
      LAYER M4 ;
      RECT 0.00000 59.42400 0.03600 59.44800 ;
    END
  END wdata[485]
  PIN wdata[486]
    DIRECTION INPUT ;
    USE SIGNAL ;
    PORT
      LAYER M4 ;
      RECT 0.00000 59.47200 0.03600 59.49600 ;
    END
  END wdata[486]
  PIN wdata[487]
    DIRECTION INPUT ;
    USE SIGNAL ;
    PORT
      LAYER M4 ;
      RECT 0.00000 59.52000 0.03600 59.54400 ;
    END
  END wdata[487]
  PIN wdata[488]
    DIRECTION INPUT ;
    USE SIGNAL ;
    PORT
      LAYER M4 ;
      RECT 0.00000 59.56800 0.03600 59.59200 ;
    END
  END wdata[488]
  PIN wdata[489]
    DIRECTION INPUT ;
    USE SIGNAL ;
    PORT
      LAYER M4 ;
      RECT 0.00000 59.61600 0.03600 59.64000 ;
    END
  END wdata[489]
  PIN wdata[490]
    DIRECTION INPUT ;
    USE SIGNAL ;
    PORT
      LAYER M4 ;
      RECT 0.00000 59.66400 0.03600 59.68800 ;
    END
  END wdata[490]
  PIN wdata[491]
    DIRECTION INPUT ;
    USE SIGNAL ;
    PORT
      LAYER M4 ;
      RECT 0.00000 59.71200 0.03600 59.73600 ;
    END
  END wdata[491]
  PIN wdata[492]
    DIRECTION INPUT ;
    USE SIGNAL ;
    PORT
      LAYER M4 ;
      RECT 0.00000 59.76000 0.03600 59.78400 ;
    END
  END wdata[492]
  PIN wdata[493]
    DIRECTION INPUT ;
    USE SIGNAL ;
    PORT
      LAYER M4 ;
      RECT 0.00000 59.80800 0.03600 59.83200 ;
    END
  END wdata[493]
  PIN wdata[494]
    DIRECTION INPUT ;
    USE SIGNAL ;
    PORT
      LAYER M4 ;
      RECT 0.00000 59.85600 0.03600 59.88000 ;
    END
  END wdata[494]
  PIN wdata[495]
    DIRECTION INPUT ;
    USE SIGNAL ;
    PORT
      LAYER M4 ;
      RECT 0.00000 59.90400 0.03600 59.92800 ;
    END
  END wdata[495]
  PIN wdata[496]
    DIRECTION INPUT ;
    USE SIGNAL ;
    PORT
      LAYER M4 ;
      RECT 0.00000 59.95200 0.03600 59.97600 ;
    END
  END wdata[496]
  PIN wdata[497]
    DIRECTION INPUT ;
    USE SIGNAL ;
    PORT
      LAYER M4 ;
      RECT 0.00000 60.00000 0.03600 60.02400 ;
    END
  END wdata[497]
  PIN wdata[498]
    DIRECTION INPUT ;
    USE SIGNAL ;
    PORT
      LAYER M4 ;
      RECT 0.00000 60.04800 0.03600 60.07200 ;
    END
  END wdata[498]
  PIN wdata[499]
    DIRECTION INPUT ;
    USE SIGNAL ;
    PORT
      LAYER M4 ;
      RECT 0.00000 60.09600 0.03600 60.12000 ;
    END
  END wdata[499]
  PIN wdata[500]
    DIRECTION INPUT ;
    USE SIGNAL ;
    PORT
      LAYER M4 ;
      RECT 0.00000 60.14400 0.03600 60.16800 ;
    END
  END wdata[500]
  PIN wdata[501]
    DIRECTION INPUT ;
    USE SIGNAL ;
    PORT
      LAYER M4 ;
      RECT 0.00000 60.19200 0.03600 60.21600 ;
    END
  END wdata[501]
  PIN wdata[502]
    DIRECTION INPUT ;
    USE SIGNAL ;
    PORT
      LAYER M4 ;
      RECT 0.00000 60.24000 0.03600 60.26400 ;
    END
  END wdata[502]
  PIN wdata[503]
    DIRECTION INPUT ;
    USE SIGNAL ;
    PORT
      LAYER M4 ;
      RECT 0.00000 60.28800 0.03600 60.31200 ;
    END
  END wdata[503]
  PIN wdata[504]
    DIRECTION INPUT ;
    USE SIGNAL ;
    PORT
      LAYER M4 ;
      RECT 0.00000 60.33600 0.03600 60.36000 ;
    END
  END wdata[504]
  PIN wdata[505]
    DIRECTION INPUT ;
    USE SIGNAL ;
    PORT
      LAYER M4 ;
      RECT 0.00000 60.38400 0.03600 60.40800 ;
    END
  END wdata[505]
  PIN wdata[506]
    DIRECTION INPUT ;
    USE SIGNAL ;
    PORT
      LAYER M4 ;
      RECT 0.00000 60.43200 0.03600 60.45600 ;
    END
  END wdata[506]
  PIN wdata[507]
    DIRECTION INPUT ;
    USE SIGNAL ;
    PORT
      LAYER M4 ;
      RECT 0.00000 60.48000 0.03600 60.50400 ;
    END
  END wdata[507]
  PIN wdata[508]
    DIRECTION INPUT ;
    USE SIGNAL ;
    PORT
      LAYER M4 ;
      RECT 0.00000 60.52800 0.03600 60.55200 ;
    END
  END wdata[508]
  PIN wdata[509]
    DIRECTION INPUT ;
    USE SIGNAL ;
    PORT
      LAYER M4 ;
      RECT 0.00000 60.57600 0.03600 60.60000 ;
    END
  END wdata[509]
  PIN wdata[510]
    DIRECTION INPUT ;
    USE SIGNAL ;
    PORT
      LAYER M4 ;
      RECT 0.00000 60.62400 0.03600 60.64800 ;
    END
  END wdata[510]
  PIN wdata[511]
    DIRECTION INPUT ;
    USE SIGNAL ;
    PORT
      LAYER M4 ;
      RECT 0.00000 60.67200 0.03600 60.69600 ;
    END
  END wdata[511]
  PIN waddr[0]
    DIRECTION INPUT ;
    USE SIGNAL ;
    PORT
      LAYER M4 ;
      RECT 0.00000 71.85600 0.03600 71.88000 ;
    END
  END waddr[0]
  PIN waddr[1]
    DIRECTION INPUT ;
    USE SIGNAL ;
    PORT
      LAYER M4 ;
      RECT 0.00000 71.90400 0.03600 71.92800 ;
    END
  END waddr[1]
  PIN waddr[2]
    DIRECTION INPUT ;
    USE SIGNAL ;
    PORT
      LAYER M4 ;
      RECT 0.00000 71.95200 0.03600 71.97600 ;
    END
  END waddr[2]
  PIN waddr[3]
    DIRECTION INPUT ;
    USE SIGNAL ;
    PORT
      LAYER M4 ;
      RECT 0.00000 72.00000 0.03600 72.02400 ;
    END
  END waddr[3]
  PIN waddr[4]
    DIRECTION INPUT ;
    USE SIGNAL ;
    PORT
      LAYER M4 ;
      RECT 0.00000 72.04800 0.03600 72.07200 ;
    END
  END waddr[4]
  PIN waddr[5]
    DIRECTION INPUT ;
    USE SIGNAL ;
    PORT
      LAYER M4 ;
      RECT 0.00000 72.09600 0.03600 72.12000 ;
    END
  END waddr[5]
  PIN waddr[6]
    DIRECTION INPUT ;
    USE SIGNAL ;
    PORT
      LAYER M4 ;
      RECT 0.00000 72.14400 0.03600 72.16800 ;
    END
  END waddr[6]
  PIN waddr[7]
    DIRECTION INPUT ;
    USE SIGNAL ;
    PORT
      LAYER M4 ;
      RECT 0.00000 72.19200 0.03600 72.21600 ;
    END
  END waddr[7]
  PIN rb_data[0]
    DIRECTION OUTPUT ;
    USE SIGNAL ;
    PORT
      LAYER M4 ;
      RECT 0.00000 0.04800 0.03600 0.07200 ;
    END
  END rb_data[0]
  PIN rb_data[1]
    DIRECTION OUTPUT ;
    USE SIGNAL ;
    PORT
      LAYER M4 ;
      RECT 0.00000 0.09600 0.03600 0.12000 ;
    END
  END rb_data[1]
  PIN rb_data[2]
    DIRECTION OUTPUT ;
    USE SIGNAL ;
    PORT
      LAYER M4 ;
      RECT 0.00000 0.14400 0.03600 0.16800 ;
    END
  END rb_data[2]
  PIN rb_data[3]
    DIRECTION OUTPUT ;
    USE SIGNAL ;
    PORT
      LAYER M4 ;
      RECT 0.00000 0.19200 0.03600 0.21600 ;
    END
  END rb_data[3]
  PIN rb_data[4]
    DIRECTION OUTPUT ;
    USE SIGNAL ;
    PORT
      LAYER M4 ;
      RECT 0.00000 0.24000 0.03600 0.26400 ;
    END
  END rb_data[4]
  PIN rb_data[5]
    DIRECTION OUTPUT ;
    USE SIGNAL ;
    PORT
      LAYER M4 ;
      RECT 0.00000 0.28800 0.03600 0.31200 ;
    END
  END rb_data[5]
  PIN rb_data[6]
    DIRECTION OUTPUT ;
    USE SIGNAL ;
    PORT
      LAYER M4 ;
      RECT 0.00000 0.33600 0.03600 0.36000 ;
    END
  END rb_data[6]
  PIN rb_data[7]
    DIRECTION OUTPUT ;
    USE SIGNAL ;
    PORT
      LAYER M4 ;
      RECT 0.00000 0.38400 0.03600 0.40800 ;
    END
  END rb_data[7]
  PIN rb_data[8]
    DIRECTION OUTPUT ;
    USE SIGNAL ;
    PORT
      LAYER M4 ;
      RECT 0.00000 0.43200 0.03600 0.45600 ;
    END
  END rb_data[8]
  PIN rb_data[9]
    DIRECTION OUTPUT ;
    USE SIGNAL ;
    PORT
      LAYER M4 ;
      RECT 0.00000 0.48000 0.03600 0.50400 ;
    END
  END rb_data[9]
  PIN rb_data[10]
    DIRECTION OUTPUT ;
    USE SIGNAL ;
    PORT
      LAYER M4 ;
      RECT 0.00000 0.52800 0.03600 0.55200 ;
    END
  END rb_data[10]
  PIN rb_data[11]
    DIRECTION OUTPUT ;
    USE SIGNAL ;
    PORT
      LAYER M4 ;
      RECT 0.00000 0.57600 0.03600 0.60000 ;
    END
  END rb_data[11]
  PIN rb_data[12]
    DIRECTION OUTPUT ;
    USE SIGNAL ;
    PORT
      LAYER M4 ;
      RECT 0.00000 0.62400 0.03600 0.64800 ;
    END
  END rb_data[12]
  PIN rb_data[13]
    DIRECTION OUTPUT ;
    USE SIGNAL ;
    PORT
      LAYER M4 ;
      RECT 0.00000 0.67200 0.03600 0.69600 ;
    END
  END rb_data[13]
  PIN rb_data[14]
    DIRECTION OUTPUT ;
    USE SIGNAL ;
    PORT
      LAYER M4 ;
      RECT 0.00000 0.72000 0.03600 0.74400 ;
    END
  END rb_data[14]
  PIN rb_data[15]
    DIRECTION OUTPUT ;
    USE SIGNAL ;
    PORT
      LAYER M4 ;
      RECT 0.00000 0.76800 0.03600 0.79200 ;
    END
  END rb_data[15]
  PIN rb_data[16]
    DIRECTION OUTPUT ;
    USE SIGNAL ;
    PORT
      LAYER M4 ;
      RECT 0.00000 0.81600 0.03600 0.84000 ;
    END
  END rb_data[16]
  PIN rb_data[17]
    DIRECTION OUTPUT ;
    USE SIGNAL ;
    PORT
      LAYER M4 ;
      RECT 0.00000 0.86400 0.03600 0.88800 ;
    END
  END rb_data[17]
  PIN rb_data[18]
    DIRECTION OUTPUT ;
    USE SIGNAL ;
    PORT
      LAYER M4 ;
      RECT 0.00000 0.91200 0.03600 0.93600 ;
    END
  END rb_data[18]
  PIN rb_data[19]
    DIRECTION OUTPUT ;
    USE SIGNAL ;
    PORT
      LAYER M4 ;
      RECT 0.00000 0.96000 0.03600 0.98400 ;
    END
  END rb_data[19]
  PIN rb_data[20]
    DIRECTION OUTPUT ;
    USE SIGNAL ;
    PORT
      LAYER M4 ;
      RECT 0.00000 1.00800 0.03600 1.03200 ;
    END
  END rb_data[20]
  PIN rb_data[21]
    DIRECTION OUTPUT ;
    USE SIGNAL ;
    PORT
      LAYER M4 ;
      RECT 0.00000 1.05600 0.03600 1.08000 ;
    END
  END rb_data[21]
  PIN rb_data[22]
    DIRECTION OUTPUT ;
    USE SIGNAL ;
    PORT
      LAYER M4 ;
      RECT 0.00000 1.10400 0.03600 1.12800 ;
    END
  END rb_data[22]
  PIN rb_data[23]
    DIRECTION OUTPUT ;
    USE SIGNAL ;
    PORT
      LAYER M4 ;
      RECT 0.00000 1.15200 0.03600 1.17600 ;
    END
  END rb_data[23]
  PIN rb_data[24]
    DIRECTION OUTPUT ;
    USE SIGNAL ;
    PORT
      LAYER M4 ;
      RECT 0.00000 1.20000 0.03600 1.22400 ;
    END
  END rb_data[24]
  PIN rb_data[25]
    DIRECTION OUTPUT ;
    USE SIGNAL ;
    PORT
      LAYER M4 ;
      RECT 0.00000 1.24800 0.03600 1.27200 ;
    END
  END rb_data[25]
  PIN rb_data[26]
    DIRECTION OUTPUT ;
    USE SIGNAL ;
    PORT
      LAYER M4 ;
      RECT 0.00000 1.29600 0.03600 1.32000 ;
    END
  END rb_data[26]
  PIN rb_data[27]
    DIRECTION OUTPUT ;
    USE SIGNAL ;
    PORT
      LAYER M4 ;
      RECT 0.00000 1.34400 0.03600 1.36800 ;
    END
  END rb_data[27]
  PIN rb_data[28]
    DIRECTION OUTPUT ;
    USE SIGNAL ;
    PORT
      LAYER M4 ;
      RECT 0.00000 1.39200 0.03600 1.41600 ;
    END
  END rb_data[28]
  PIN rb_data[29]
    DIRECTION OUTPUT ;
    USE SIGNAL ;
    PORT
      LAYER M4 ;
      RECT 0.00000 1.44000 0.03600 1.46400 ;
    END
  END rb_data[29]
  PIN rb_data[30]
    DIRECTION OUTPUT ;
    USE SIGNAL ;
    PORT
      LAYER M4 ;
      RECT 0.00000 1.48800 0.03600 1.51200 ;
    END
  END rb_data[30]
  PIN rb_data[31]
    DIRECTION OUTPUT ;
    USE SIGNAL ;
    PORT
      LAYER M4 ;
      RECT 0.00000 1.53600 0.03600 1.56000 ;
    END
  END rb_data[31]
  PIN rb_data[32]
    DIRECTION OUTPUT ;
    USE SIGNAL ;
    PORT
      LAYER M4 ;
      RECT 0.00000 1.58400 0.03600 1.60800 ;
    END
  END rb_data[32]
  PIN rb_data[33]
    DIRECTION OUTPUT ;
    USE SIGNAL ;
    PORT
      LAYER M4 ;
      RECT 0.00000 1.63200 0.03600 1.65600 ;
    END
  END rb_data[33]
  PIN rb_data[34]
    DIRECTION OUTPUT ;
    USE SIGNAL ;
    PORT
      LAYER M4 ;
      RECT 0.00000 1.68000 0.03600 1.70400 ;
    END
  END rb_data[34]
  PIN rb_data[35]
    DIRECTION OUTPUT ;
    USE SIGNAL ;
    PORT
      LAYER M4 ;
      RECT 0.00000 1.72800 0.03600 1.75200 ;
    END
  END rb_data[35]
  PIN rb_data[36]
    DIRECTION OUTPUT ;
    USE SIGNAL ;
    PORT
      LAYER M4 ;
      RECT 0.00000 1.77600 0.03600 1.80000 ;
    END
  END rb_data[36]
  PIN rb_data[37]
    DIRECTION OUTPUT ;
    USE SIGNAL ;
    PORT
      LAYER M4 ;
      RECT 0.00000 1.82400 0.03600 1.84800 ;
    END
  END rb_data[37]
  PIN rb_data[38]
    DIRECTION OUTPUT ;
    USE SIGNAL ;
    PORT
      LAYER M4 ;
      RECT 0.00000 1.87200 0.03600 1.89600 ;
    END
  END rb_data[38]
  PIN rb_data[39]
    DIRECTION OUTPUT ;
    USE SIGNAL ;
    PORT
      LAYER M4 ;
      RECT 0.00000 1.92000 0.03600 1.94400 ;
    END
  END rb_data[39]
  PIN rb_data[40]
    DIRECTION OUTPUT ;
    USE SIGNAL ;
    PORT
      LAYER M4 ;
      RECT 0.00000 1.96800 0.03600 1.99200 ;
    END
  END rb_data[40]
  PIN rb_data[41]
    DIRECTION OUTPUT ;
    USE SIGNAL ;
    PORT
      LAYER M4 ;
      RECT 0.00000 2.01600 0.03600 2.04000 ;
    END
  END rb_data[41]
  PIN rb_data[42]
    DIRECTION OUTPUT ;
    USE SIGNAL ;
    PORT
      LAYER M4 ;
      RECT 0.00000 2.06400 0.03600 2.08800 ;
    END
  END rb_data[42]
  PIN rb_data[43]
    DIRECTION OUTPUT ;
    USE SIGNAL ;
    PORT
      LAYER M4 ;
      RECT 0.00000 2.11200 0.03600 2.13600 ;
    END
  END rb_data[43]
  PIN rb_data[44]
    DIRECTION OUTPUT ;
    USE SIGNAL ;
    PORT
      LAYER M4 ;
      RECT 0.00000 2.16000 0.03600 2.18400 ;
    END
  END rb_data[44]
  PIN rb_data[45]
    DIRECTION OUTPUT ;
    USE SIGNAL ;
    PORT
      LAYER M4 ;
      RECT 0.00000 2.20800 0.03600 2.23200 ;
    END
  END rb_data[45]
  PIN rb_data[46]
    DIRECTION OUTPUT ;
    USE SIGNAL ;
    PORT
      LAYER M4 ;
      RECT 0.00000 2.25600 0.03600 2.28000 ;
    END
  END rb_data[46]
  PIN rb_data[47]
    DIRECTION OUTPUT ;
    USE SIGNAL ;
    PORT
      LAYER M4 ;
      RECT 0.00000 2.30400 0.03600 2.32800 ;
    END
  END rb_data[47]
  PIN rb_data[48]
    DIRECTION OUTPUT ;
    USE SIGNAL ;
    PORT
      LAYER M4 ;
      RECT 0.00000 2.35200 0.03600 2.37600 ;
    END
  END rb_data[48]
  PIN rb_data[49]
    DIRECTION OUTPUT ;
    USE SIGNAL ;
    PORT
      LAYER M4 ;
      RECT 0.00000 2.40000 0.03600 2.42400 ;
    END
  END rb_data[49]
  PIN rb_data[50]
    DIRECTION OUTPUT ;
    USE SIGNAL ;
    PORT
      LAYER M4 ;
      RECT 0.00000 2.44800 0.03600 2.47200 ;
    END
  END rb_data[50]
  PIN rb_data[51]
    DIRECTION OUTPUT ;
    USE SIGNAL ;
    PORT
      LAYER M4 ;
      RECT 0.00000 2.49600 0.03600 2.52000 ;
    END
  END rb_data[51]
  PIN rb_data[52]
    DIRECTION OUTPUT ;
    USE SIGNAL ;
    PORT
      LAYER M4 ;
      RECT 0.00000 2.54400 0.03600 2.56800 ;
    END
  END rb_data[52]
  PIN rb_data[53]
    DIRECTION OUTPUT ;
    USE SIGNAL ;
    PORT
      LAYER M4 ;
      RECT 0.00000 2.59200 0.03600 2.61600 ;
    END
  END rb_data[53]
  PIN rb_data[54]
    DIRECTION OUTPUT ;
    USE SIGNAL ;
    PORT
      LAYER M4 ;
      RECT 0.00000 2.64000 0.03600 2.66400 ;
    END
  END rb_data[54]
  PIN rb_data[55]
    DIRECTION OUTPUT ;
    USE SIGNAL ;
    PORT
      LAYER M4 ;
      RECT 0.00000 2.68800 0.03600 2.71200 ;
    END
  END rb_data[55]
  PIN rb_data[56]
    DIRECTION OUTPUT ;
    USE SIGNAL ;
    PORT
      LAYER M4 ;
      RECT 0.00000 2.73600 0.03600 2.76000 ;
    END
  END rb_data[56]
  PIN rb_data[57]
    DIRECTION OUTPUT ;
    USE SIGNAL ;
    PORT
      LAYER M4 ;
      RECT 0.00000 2.78400 0.03600 2.80800 ;
    END
  END rb_data[57]
  PIN rb_data[58]
    DIRECTION OUTPUT ;
    USE SIGNAL ;
    PORT
      LAYER M4 ;
      RECT 0.00000 2.83200 0.03600 2.85600 ;
    END
  END rb_data[58]
  PIN rb_data[59]
    DIRECTION OUTPUT ;
    USE SIGNAL ;
    PORT
      LAYER M4 ;
      RECT 0.00000 2.88000 0.03600 2.90400 ;
    END
  END rb_data[59]
  PIN rb_data[60]
    DIRECTION OUTPUT ;
    USE SIGNAL ;
    PORT
      LAYER M4 ;
      RECT 0.00000 2.92800 0.03600 2.95200 ;
    END
  END rb_data[60]
  PIN rb_data[61]
    DIRECTION OUTPUT ;
    USE SIGNAL ;
    PORT
      LAYER M4 ;
      RECT 0.00000 2.97600 0.03600 3.00000 ;
    END
  END rb_data[61]
  PIN rb_data[62]
    DIRECTION OUTPUT ;
    USE SIGNAL ;
    PORT
      LAYER M4 ;
      RECT 0.00000 3.02400 0.03600 3.04800 ;
    END
  END rb_data[62]
  PIN rb_data[63]
    DIRECTION OUTPUT ;
    USE SIGNAL ;
    PORT
      LAYER M4 ;
      RECT 0.00000 3.07200 0.03600 3.09600 ;
    END
  END rb_data[63]
  PIN rb_data[64]
    DIRECTION OUTPUT ;
    USE SIGNAL ;
    PORT
      LAYER M4 ;
      RECT 0.00000 3.12000 0.03600 3.14400 ;
    END
  END rb_data[64]
  PIN rb_data[65]
    DIRECTION OUTPUT ;
    USE SIGNAL ;
    PORT
      LAYER M4 ;
      RECT 0.00000 3.16800 0.03600 3.19200 ;
    END
  END rb_data[65]
  PIN rb_data[66]
    DIRECTION OUTPUT ;
    USE SIGNAL ;
    PORT
      LAYER M4 ;
      RECT 0.00000 3.21600 0.03600 3.24000 ;
    END
  END rb_data[66]
  PIN rb_data[67]
    DIRECTION OUTPUT ;
    USE SIGNAL ;
    PORT
      LAYER M4 ;
      RECT 0.00000 3.26400 0.03600 3.28800 ;
    END
  END rb_data[67]
  PIN rb_data[68]
    DIRECTION OUTPUT ;
    USE SIGNAL ;
    PORT
      LAYER M4 ;
      RECT 0.00000 3.31200 0.03600 3.33600 ;
    END
  END rb_data[68]
  PIN rb_data[69]
    DIRECTION OUTPUT ;
    USE SIGNAL ;
    PORT
      LAYER M4 ;
      RECT 0.00000 3.36000 0.03600 3.38400 ;
    END
  END rb_data[69]
  PIN rb_data[70]
    DIRECTION OUTPUT ;
    USE SIGNAL ;
    PORT
      LAYER M4 ;
      RECT 0.00000 3.40800 0.03600 3.43200 ;
    END
  END rb_data[70]
  PIN rb_data[71]
    DIRECTION OUTPUT ;
    USE SIGNAL ;
    PORT
      LAYER M4 ;
      RECT 0.00000 3.45600 0.03600 3.48000 ;
    END
  END rb_data[71]
  PIN rb_data[72]
    DIRECTION OUTPUT ;
    USE SIGNAL ;
    PORT
      LAYER M4 ;
      RECT 0.00000 3.50400 0.03600 3.52800 ;
    END
  END rb_data[72]
  PIN rb_data[73]
    DIRECTION OUTPUT ;
    USE SIGNAL ;
    PORT
      LAYER M4 ;
      RECT 0.00000 3.55200 0.03600 3.57600 ;
    END
  END rb_data[73]
  PIN rb_data[74]
    DIRECTION OUTPUT ;
    USE SIGNAL ;
    PORT
      LAYER M4 ;
      RECT 0.00000 3.60000 0.03600 3.62400 ;
    END
  END rb_data[74]
  PIN rb_data[75]
    DIRECTION OUTPUT ;
    USE SIGNAL ;
    PORT
      LAYER M4 ;
      RECT 0.00000 3.64800 0.03600 3.67200 ;
    END
  END rb_data[75]
  PIN rb_data[76]
    DIRECTION OUTPUT ;
    USE SIGNAL ;
    PORT
      LAYER M4 ;
      RECT 0.00000 3.69600 0.03600 3.72000 ;
    END
  END rb_data[76]
  PIN rb_data[77]
    DIRECTION OUTPUT ;
    USE SIGNAL ;
    PORT
      LAYER M4 ;
      RECT 0.00000 3.74400 0.03600 3.76800 ;
    END
  END rb_data[77]
  PIN rb_data[78]
    DIRECTION OUTPUT ;
    USE SIGNAL ;
    PORT
      LAYER M4 ;
      RECT 0.00000 3.79200 0.03600 3.81600 ;
    END
  END rb_data[78]
  PIN rb_data[79]
    DIRECTION OUTPUT ;
    USE SIGNAL ;
    PORT
      LAYER M4 ;
      RECT 0.00000 3.84000 0.03600 3.86400 ;
    END
  END rb_data[79]
  PIN rb_data[80]
    DIRECTION OUTPUT ;
    USE SIGNAL ;
    PORT
      LAYER M4 ;
      RECT 0.00000 3.88800 0.03600 3.91200 ;
    END
  END rb_data[80]
  PIN rb_data[81]
    DIRECTION OUTPUT ;
    USE SIGNAL ;
    PORT
      LAYER M4 ;
      RECT 0.00000 3.93600 0.03600 3.96000 ;
    END
  END rb_data[81]
  PIN rb_data[82]
    DIRECTION OUTPUT ;
    USE SIGNAL ;
    PORT
      LAYER M4 ;
      RECT 0.00000 3.98400 0.03600 4.00800 ;
    END
  END rb_data[82]
  PIN rb_data[83]
    DIRECTION OUTPUT ;
    USE SIGNAL ;
    PORT
      LAYER M4 ;
      RECT 0.00000 4.03200 0.03600 4.05600 ;
    END
  END rb_data[83]
  PIN rb_data[84]
    DIRECTION OUTPUT ;
    USE SIGNAL ;
    PORT
      LAYER M4 ;
      RECT 0.00000 4.08000 0.03600 4.10400 ;
    END
  END rb_data[84]
  PIN rb_data[85]
    DIRECTION OUTPUT ;
    USE SIGNAL ;
    PORT
      LAYER M4 ;
      RECT 0.00000 4.12800 0.03600 4.15200 ;
    END
  END rb_data[85]
  PIN rb_data[86]
    DIRECTION OUTPUT ;
    USE SIGNAL ;
    PORT
      LAYER M4 ;
      RECT 0.00000 4.17600 0.03600 4.20000 ;
    END
  END rb_data[86]
  PIN rb_data[87]
    DIRECTION OUTPUT ;
    USE SIGNAL ;
    PORT
      LAYER M4 ;
      RECT 0.00000 4.22400 0.03600 4.24800 ;
    END
  END rb_data[87]
  PIN rb_data[88]
    DIRECTION OUTPUT ;
    USE SIGNAL ;
    PORT
      LAYER M4 ;
      RECT 0.00000 4.27200 0.03600 4.29600 ;
    END
  END rb_data[88]
  PIN rb_data[89]
    DIRECTION OUTPUT ;
    USE SIGNAL ;
    PORT
      LAYER M4 ;
      RECT 0.00000 4.32000 0.03600 4.34400 ;
    END
  END rb_data[89]
  PIN rb_data[90]
    DIRECTION OUTPUT ;
    USE SIGNAL ;
    PORT
      LAYER M4 ;
      RECT 0.00000 4.36800 0.03600 4.39200 ;
    END
  END rb_data[90]
  PIN rb_data[91]
    DIRECTION OUTPUT ;
    USE SIGNAL ;
    PORT
      LAYER M4 ;
      RECT 0.00000 4.41600 0.03600 4.44000 ;
    END
  END rb_data[91]
  PIN rb_data[92]
    DIRECTION OUTPUT ;
    USE SIGNAL ;
    PORT
      LAYER M4 ;
      RECT 0.00000 4.46400 0.03600 4.48800 ;
    END
  END rb_data[92]
  PIN rb_data[93]
    DIRECTION OUTPUT ;
    USE SIGNAL ;
    PORT
      LAYER M4 ;
      RECT 0.00000 4.51200 0.03600 4.53600 ;
    END
  END rb_data[93]
  PIN rb_data[94]
    DIRECTION OUTPUT ;
    USE SIGNAL ;
    PORT
      LAYER M4 ;
      RECT 0.00000 4.56000 0.03600 4.58400 ;
    END
  END rb_data[94]
  PIN rb_data[95]
    DIRECTION OUTPUT ;
    USE SIGNAL ;
    PORT
      LAYER M4 ;
      RECT 0.00000 4.60800 0.03600 4.63200 ;
    END
  END rb_data[95]
  PIN rb_data[96]
    DIRECTION OUTPUT ;
    USE SIGNAL ;
    PORT
      LAYER M4 ;
      RECT 0.00000 4.65600 0.03600 4.68000 ;
    END
  END rb_data[96]
  PIN rb_data[97]
    DIRECTION OUTPUT ;
    USE SIGNAL ;
    PORT
      LAYER M4 ;
      RECT 0.00000 4.70400 0.03600 4.72800 ;
    END
  END rb_data[97]
  PIN rb_data[98]
    DIRECTION OUTPUT ;
    USE SIGNAL ;
    PORT
      LAYER M4 ;
      RECT 0.00000 4.75200 0.03600 4.77600 ;
    END
  END rb_data[98]
  PIN rb_data[99]
    DIRECTION OUTPUT ;
    USE SIGNAL ;
    PORT
      LAYER M4 ;
      RECT 0.00000 4.80000 0.03600 4.82400 ;
    END
  END rb_data[99]
  PIN rb_data[100]
    DIRECTION OUTPUT ;
    USE SIGNAL ;
    PORT
      LAYER M4 ;
      RECT 0.00000 4.84800 0.03600 4.87200 ;
    END
  END rb_data[100]
  PIN rb_data[101]
    DIRECTION OUTPUT ;
    USE SIGNAL ;
    PORT
      LAYER M4 ;
      RECT 0.00000 4.89600 0.03600 4.92000 ;
    END
  END rb_data[101]
  PIN rb_data[102]
    DIRECTION OUTPUT ;
    USE SIGNAL ;
    PORT
      LAYER M4 ;
      RECT 0.00000 4.94400 0.03600 4.96800 ;
    END
  END rb_data[102]
  PIN rb_data[103]
    DIRECTION OUTPUT ;
    USE SIGNAL ;
    PORT
      LAYER M4 ;
      RECT 0.00000 4.99200 0.03600 5.01600 ;
    END
  END rb_data[103]
  PIN rb_data[104]
    DIRECTION OUTPUT ;
    USE SIGNAL ;
    PORT
      LAYER M4 ;
      RECT 0.00000 5.04000 0.03600 5.06400 ;
    END
  END rb_data[104]
  PIN rb_data[105]
    DIRECTION OUTPUT ;
    USE SIGNAL ;
    PORT
      LAYER M4 ;
      RECT 0.00000 5.08800 0.03600 5.11200 ;
    END
  END rb_data[105]
  PIN rb_data[106]
    DIRECTION OUTPUT ;
    USE SIGNAL ;
    PORT
      LAYER M4 ;
      RECT 0.00000 5.13600 0.03600 5.16000 ;
    END
  END rb_data[106]
  PIN rb_data[107]
    DIRECTION OUTPUT ;
    USE SIGNAL ;
    PORT
      LAYER M4 ;
      RECT 0.00000 5.18400 0.03600 5.20800 ;
    END
  END rb_data[107]
  PIN rb_data[108]
    DIRECTION OUTPUT ;
    USE SIGNAL ;
    PORT
      LAYER M4 ;
      RECT 0.00000 5.23200 0.03600 5.25600 ;
    END
  END rb_data[108]
  PIN rb_data[109]
    DIRECTION OUTPUT ;
    USE SIGNAL ;
    PORT
      LAYER M4 ;
      RECT 0.00000 5.28000 0.03600 5.30400 ;
    END
  END rb_data[109]
  PIN rb_data[110]
    DIRECTION OUTPUT ;
    USE SIGNAL ;
    PORT
      LAYER M4 ;
      RECT 0.00000 5.32800 0.03600 5.35200 ;
    END
  END rb_data[110]
  PIN rb_data[111]
    DIRECTION OUTPUT ;
    USE SIGNAL ;
    PORT
      LAYER M4 ;
      RECT 0.00000 5.37600 0.03600 5.40000 ;
    END
  END rb_data[111]
  PIN rb_data[112]
    DIRECTION OUTPUT ;
    USE SIGNAL ;
    PORT
      LAYER M4 ;
      RECT 0.00000 5.42400 0.03600 5.44800 ;
    END
  END rb_data[112]
  PIN rb_data[113]
    DIRECTION OUTPUT ;
    USE SIGNAL ;
    PORT
      LAYER M4 ;
      RECT 0.00000 5.47200 0.03600 5.49600 ;
    END
  END rb_data[113]
  PIN rb_data[114]
    DIRECTION OUTPUT ;
    USE SIGNAL ;
    PORT
      LAYER M4 ;
      RECT 0.00000 5.52000 0.03600 5.54400 ;
    END
  END rb_data[114]
  PIN rb_data[115]
    DIRECTION OUTPUT ;
    USE SIGNAL ;
    PORT
      LAYER M4 ;
      RECT 0.00000 5.56800 0.03600 5.59200 ;
    END
  END rb_data[115]
  PIN rb_data[116]
    DIRECTION OUTPUT ;
    USE SIGNAL ;
    PORT
      LAYER M4 ;
      RECT 0.00000 5.61600 0.03600 5.64000 ;
    END
  END rb_data[116]
  PIN rb_data[117]
    DIRECTION OUTPUT ;
    USE SIGNAL ;
    PORT
      LAYER M4 ;
      RECT 0.00000 5.66400 0.03600 5.68800 ;
    END
  END rb_data[117]
  PIN rb_data[118]
    DIRECTION OUTPUT ;
    USE SIGNAL ;
    PORT
      LAYER M4 ;
      RECT 0.00000 5.71200 0.03600 5.73600 ;
    END
  END rb_data[118]
  PIN rb_data[119]
    DIRECTION OUTPUT ;
    USE SIGNAL ;
    PORT
      LAYER M4 ;
      RECT 0.00000 5.76000 0.03600 5.78400 ;
    END
  END rb_data[119]
  PIN rb_data[120]
    DIRECTION OUTPUT ;
    USE SIGNAL ;
    PORT
      LAYER M4 ;
      RECT 0.00000 5.80800 0.03600 5.83200 ;
    END
  END rb_data[120]
  PIN rb_data[121]
    DIRECTION OUTPUT ;
    USE SIGNAL ;
    PORT
      LAYER M4 ;
      RECT 0.00000 5.85600 0.03600 5.88000 ;
    END
  END rb_data[121]
  PIN rb_data[122]
    DIRECTION OUTPUT ;
    USE SIGNAL ;
    PORT
      LAYER M4 ;
      RECT 0.00000 5.90400 0.03600 5.92800 ;
    END
  END rb_data[122]
  PIN rb_data[123]
    DIRECTION OUTPUT ;
    USE SIGNAL ;
    PORT
      LAYER M4 ;
      RECT 0.00000 5.95200 0.03600 5.97600 ;
    END
  END rb_data[123]
  PIN rb_data[124]
    DIRECTION OUTPUT ;
    USE SIGNAL ;
    PORT
      LAYER M4 ;
      RECT 0.00000 6.00000 0.03600 6.02400 ;
    END
  END rb_data[124]
  PIN rb_data[125]
    DIRECTION OUTPUT ;
    USE SIGNAL ;
    PORT
      LAYER M4 ;
      RECT 0.00000 6.04800 0.03600 6.07200 ;
    END
  END rb_data[125]
  PIN rb_data[126]
    DIRECTION OUTPUT ;
    USE SIGNAL ;
    PORT
      LAYER M4 ;
      RECT 0.00000 6.09600 0.03600 6.12000 ;
    END
  END rb_data[126]
  PIN rb_data[127]
    DIRECTION OUTPUT ;
    USE SIGNAL ;
    PORT
      LAYER M4 ;
      RECT 0.00000 6.14400 0.03600 6.16800 ;
    END
  END rb_data[127]
  PIN rb_data[128]
    DIRECTION OUTPUT ;
    USE SIGNAL ;
    PORT
      LAYER M4 ;
      RECT 0.00000 6.19200 0.03600 6.21600 ;
    END
  END rb_data[128]
  PIN rb_data[129]
    DIRECTION OUTPUT ;
    USE SIGNAL ;
    PORT
      LAYER M4 ;
      RECT 0.00000 6.24000 0.03600 6.26400 ;
    END
  END rb_data[129]
  PIN rb_data[130]
    DIRECTION OUTPUT ;
    USE SIGNAL ;
    PORT
      LAYER M4 ;
      RECT 0.00000 6.28800 0.03600 6.31200 ;
    END
  END rb_data[130]
  PIN rb_data[131]
    DIRECTION OUTPUT ;
    USE SIGNAL ;
    PORT
      LAYER M4 ;
      RECT 0.00000 6.33600 0.03600 6.36000 ;
    END
  END rb_data[131]
  PIN rb_data[132]
    DIRECTION OUTPUT ;
    USE SIGNAL ;
    PORT
      LAYER M4 ;
      RECT 0.00000 6.38400 0.03600 6.40800 ;
    END
  END rb_data[132]
  PIN rb_data[133]
    DIRECTION OUTPUT ;
    USE SIGNAL ;
    PORT
      LAYER M4 ;
      RECT 0.00000 6.43200 0.03600 6.45600 ;
    END
  END rb_data[133]
  PIN rb_data[134]
    DIRECTION OUTPUT ;
    USE SIGNAL ;
    PORT
      LAYER M4 ;
      RECT 0.00000 6.48000 0.03600 6.50400 ;
    END
  END rb_data[134]
  PIN rb_data[135]
    DIRECTION OUTPUT ;
    USE SIGNAL ;
    PORT
      LAYER M4 ;
      RECT 0.00000 6.52800 0.03600 6.55200 ;
    END
  END rb_data[135]
  PIN rb_data[136]
    DIRECTION OUTPUT ;
    USE SIGNAL ;
    PORT
      LAYER M4 ;
      RECT 0.00000 6.57600 0.03600 6.60000 ;
    END
  END rb_data[136]
  PIN rb_data[137]
    DIRECTION OUTPUT ;
    USE SIGNAL ;
    PORT
      LAYER M4 ;
      RECT 0.00000 6.62400 0.03600 6.64800 ;
    END
  END rb_data[137]
  PIN rb_data[138]
    DIRECTION OUTPUT ;
    USE SIGNAL ;
    PORT
      LAYER M4 ;
      RECT 0.00000 6.67200 0.03600 6.69600 ;
    END
  END rb_data[138]
  PIN rb_data[139]
    DIRECTION OUTPUT ;
    USE SIGNAL ;
    PORT
      LAYER M4 ;
      RECT 0.00000 6.72000 0.03600 6.74400 ;
    END
  END rb_data[139]
  PIN rb_data[140]
    DIRECTION OUTPUT ;
    USE SIGNAL ;
    PORT
      LAYER M4 ;
      RECT 0.00000 6.76800 0.03600 6.79200 ;
    END
  END rb_data[140]
  PIN rb_data[141]
    DIRECTION OUTPUT ;
    USE SIGNAL ;
    PORT
      LAYER M4 ;
      RECT 0.00000 6.81600 0.03600 6.84000 ;
    END
  END rb_data[141]
  PIN rb_data[142]
    DIRECTION OUTPUT ;
    USE SIGNAL ;
    PORT
      LAYER M4 ;
      RECT 0.00000 6.86400 0.03600 6.88800 ;
    END
  END rb_data[142]
  PIN rb_data[143]
    DIRECTION OUTPUT ;
    USE SIGNAL ;
    PORT
      LAYER M4 ;
      RECT 0.00000 6.91200 0.03600 6.93600 ;
    END
  END rb_data[143]
  PIN rb_data[144]
    DIRECTION OUTPUT ;
    USE SIGNAL ;
    PORT
      LAYER M4 ;
      RECT 0.00000 6.96000 0.03600 6.98400 ;
    END
  END rb_data[144]
  PIN rb_data[145]
    DIRECTION OUTPUT ;
    USE SIGNAL ;
    PORT
      LAYER M4 ;
      RECT 0.00000 7.00800 0.03600 7.03200 ;
    END
  END rb_data[145]
  PIN rb_data[146]
    DIRECTION OUTPUT ;
    USE SIGNAL ;
    PORT
      LAYER M4 ;
      RECT 0.00000 7.05600 0.03600 7.08000 ;
    END
  END rb_data[146]
  PIN rb_data[147]
    DIRECTION OUTPUT ;
    USE SIGNAL ;
    PORT
      LAYER M4 ;
      RECT 0.00000 7.10400 0.03600 7.12800 ;
    END
  END rb_data[147]
  PIN rb_data[148]
    DIRECTION OUTPUT ;
    USE SIGNAL ;
    PORT
      LAYER M4 ;
      RECT 0.00000 7.15200 0.03600 7.17600 ;
    END
  END rb_data[148]
  PIN rb_data[149]
    DIRECTION OUTPUT ;
    USE SIGNAL ;
    PORT
      LAYER M4 ;
      RECT 0.00000 7.20000 0.03600 7.22400 ;
    END
  END rb_data[149]
  PIN rb_data[150]
    DIRECTION OUTPUT ;
    USE SIGNAL ;
    PORT
      LAYER M4 ;
      RECT 0.00000 7.24800 0.03600 7.27200 ;
    END
  END rb_data[150]
  PIN rb_data[151]
    DIRECTION OUTPUT ;
    USE SIGNAL ;
    PORT
      LAYER M4 ;
      RECT 0.00000 7.29600 0.03600 7.32000 ;
    END
  END rb_data[151]
  PIN rb_data[152]
    DIRECTION OUTPUT ;
    USE SIGNAL ;
    PORT
      LAYER M4 ;
      RECT 0.00000 7.34400 0.03600 7.36800 ;
    END
  END rb_data[152]
  PIN rb_data[153]
    DIRECTION OUTPUT ;
    USE SIGNAL ;
    PORT
      LAYER M4 ;
      RECT 0.00000 7.39200 0.03600 7.41600 ;
    END
  END rb_data[153]
  PIN rb_data[154]
    DIRECTION OUTPUT ;
    USE SIGNAL ;
    PORT
      LAYER M4 ;
      RECT 0.00000 7.44000 0.03600 7.46400 ;
    END
  END rb_data[154]
  PIN rb_data[155]
    DIRECTION OUTPUT ;
    USE SIGNAL ;
    PORT
      LAYER M4 ;
      RECT 0.00000 7.48800 0.03600 7.51200 ;
    END
  END rb_data[155]
  PIN rb_data[156]
    DIRECTION OUTPUT ;
    USE SIGNAL ;
    PORT
      LAYER M4 ;
      RECT 0.00000 7.53600 0.03600 7.56000 ;
    END
  END rb_data[156]
  PIN rb_data[157]
    DIRECTION OUTPUT ;
    USE SIGNAL ;
    PORT
      LAYER M4 ;
      RECT 0.00000 7.58400 0.03600 7.60800 ;
    END
  END rb_data[157]
  PIN rb_data[158]
    DIRECTION OUTPUT ;
    USE SIGNAL ;
    PORT
      LAYER M4 ;
      RECT 0.00000 7.63200 0.03600 7.65600 ;
    END
  END rb_data[158]
  PIN rb_data[159]
    DIRECTION OUTPUT ;
    USE SIGNAL ;
    PORT
      LAYER M4 ;
      RECT 0.00000 7.68000 0.03600 7.70400 ;
    END
  END rb_data[159]
  PIN rb_data[160]
    DIRECTION OUTPUT ;
    USE SIGNAL ;
    PORT
      LAYER M4 ;
      RECT 0.00000 7.72800 0.03600 7.75200 ;
    END
  END rb_data[160]
  PIN rb_data[161]
    DIRECTION OUTPUT ;
    USE SIGNAL ;
    PORT
      LAYER M4 ;
      RECT 0.00000 7.77600 0.03600 7.80000 ;
    END
  END rb_data[161]
  PIN rb_data[162]
    DIRECTION OUTPUT ;
    USE SIGNAL ;
    PORT
      LAYER M4 ;
      RECT 0.00000 7.82400 0.03600 7.84800 ;
    END
  END rb_data[162]
  PIN rb_data[163]
    DIRECTION OUTPUT ;
    USE SIGNAL ;
    PORT
      LAYER M4 ;
      RECT 0.00000 7.87200 0.03600 7.89600 ;
    END
  END rb_data[163]
  PIN rb_data[164]
    DIRECTION OUTPUT ;
    USE SIGNAL ;
    PORT
      LAYER M4 ;
      RECT 0.00000 7.92000 0.03600 7.94400 ;
    END
  END rb_data[164]
  PIN rb_data[165]
    DIRECTION OUTPUT ;
    USE SIGNAL ;
    PORT
      LAYER M4 ;
      RECT 0.00000 7.96800 0.03600 7.99200 ;
    END
  END rb_data[165]
  PIN rb_data[166]
    DIRECTION OUTPUT ;
    USE SIGNAL ;
    PORT
      LAYER M4 ;
      RECT 0.00000 8.01600 0.03600 8.04000 ;
    END
  END rb_data[166]
  PIN rb_data[167]
    DIRECTION OUTPUT ;
    USE SIGNAL ;
    PORT
      LAYER M4 ;
      RECT 0.00000 8.06400 0.03600 8.08800 ;
    END
  END rb_data[167]
  PIN rb_data[168]
    DIRECTION OUTPUT ;
    USE SIGNAL ;
    PORT
      LAYER M4 ;
      RECT 0.00000 8.11200 0.03600 8.13600 ;
    END
  END rb_data[168]
  PIN rb_data[169]
    DIRECTION OUTPUT ;
    USE SIGNAL ;
    PORT
      LAYER M4 ;
      RECT 0.00000 8.16000 0.03600 8.18400 ;
    END
  END rb_data[169]
  PIN rb_data[170]
    DIRECTION OUTPUT ;
    USE SIGNAL ;
    PORT
      LAYER M4 ;
      RECT 0.00000 8.20800 0.03600 8.23200 ;
    END
  END rb_data[170]
  PIN rb_data[171]
    DIRECTION OUTPUT ;
    USE SIGNAL ;
    PORT
      LAYER M4 ;
      RECT 0.00000 8.25600 0.03600 8.28000 ;
    END
  END rb_data[171]
  PIN rb_data[172]
    DIRECTION OUTPUT ;
    USE SIGNAL ;
    PORT
      LAYER M4 ;
      RECT 0.00000 8.30400 0.03600 8.32800 ;
    END
  END rb_data[172]
  PIN rb_data[173]
    DIRECTION OUTPUT ;
    USE SIGNAL ;
    PORT
      LAYER M4 ;
      RECT 0.00000 8.35200 0.03600 8.37600 ;
    END
  END rb_data[173]
  PIN rb_data[174]
    DIRECTION OUTPUT ;
    USE SIGNAL ;
    PORT
      LAYER M4 ;
      RECT 0.00000 8.40000 0.03600 8.42400 ;
    END
  END rb_data[174]
  PIN rb_data[175]
    DIRECTION OUTPUT ;
    USE SIGNAL ;
    PORT
      LAYER M4 ;
      RECT 0.00000 8.44800 0.03600 8.47200 ;
    END
  END rb_data[175]
  PIN rb_data[176]
    DIRECTION OUTPUT ;
    USE SIGNAL ;
    PORT
      LAYER M4 ;
      RECT 0.00000 8.49600 0.03600 8.52000 ;
    END
  END rb_data[176]
  PIN rb_data[177]
    DIRECTION OUTPUT ;
    USE SIGNAL ;
    PORT
      LAYER M4 ;
      RECT 0.00000 8.54400 0.03600 8.56800 ;
    END
  END rb_data[177]
  PIN rb_data[178]
    DIRECTION OUTPUT ;
    USE SIGNAL ;
    PORT
      LAYER M4 ;
      RECT 0.00000 8.59200 0.03600 8.61600 ;
    END
  END rb_data[178]
  PIN rb_data[179]
    DIRECTION OUTPUT ;
    USE SIGNAL ;
    PORT
      LAYER M4 ;
      RECT 0.00000 8.64000 0.03600 8.66400 ;
    END
  END rb_data[179]
  PIN rb_data[180]
    DIRECTION OUTPUT ;
    USE SIGNAL ;
    PORT
      LAYER M4 ;
      RECT 0.00000 8.68800 0.03600 8.71200 ;
    END
  END rb_data[180]
  PIN rb_data[181]
    DIRECTION OUTPUT ;
    USE SIGNAL ;
    PORT
      LAYER M4 ;
      RECT 0.00000 8.73600 0.03600 8.76000 ;
    END
  END rb_data[181]
  PIN rb_data[182]
    DIRECTION OUTPUT ;
    USE SIGNAL ;
    PORT
      LAYER M4 ;
      RECT 0.00000 8.78400 0.03600 8.80800 ;
    END
  END rb_data[182]
  PIN rb_data[183]
    DIRECTION OUTPUT ;
    USE SIGNAL ;
    PORT
      LAYER M4 ;
      RECT 0.00000 8.83200 0.03600 8.85600 ;
    END
  END rb_data[183]
  PIN rb_data[184]
    DIRECTION OUTPUT ;
    USE SIGNAL ;
    PORT
      LAYER M4 ;
      RECT 0.00000 8.88000 0.03600 8.90400 ;
    END
  END rb_data[184]
  PIN rb_data[185]
    DIRECTION OUTPUT ;
    USE SIGNAL ;
    PORT
      LAYER M4 ;
      RECT 0.00000 8.92800 0.03600 8.95200 ;
    END
  END rb_data[185]
  PIN rb_data[186]
    DIRECTION OUTPUT ;
    USE SIGNAL ;
    PORT
      LAYER M4 ;
      RECT 0.00000 8.97600 0.03600 9.00000 ;
    END
  END rb_data[186]
  PIN rb_data[187]
    DIRECTION OUTPUT ;
    USE SIGNAL ;
    PORT
      LAYER M4 ;
      RECT 0.00000 9.02400 0.03600 9.04800 ;
    END
  END rb_data[187]
  PIN rb_data[188]
    DIRECTION OUTPUT ;
    USE SIGNAL ;
    PORT
      LAYER M4 ;
      RECT 0.00000 9.07200 0.03600 9.09600 ;
    END
  END rb_data[188]
  PIN rb_data[189]
    DIRECTION OUTPUT ;
    USE SIGNAL ;
    PORT
      LAYER M4 ;
      RECT 0.00000 9.12000 0.03600 9.14400 ;
    END
  END rb_data[189]
  PIN rb_data[190]
    DIRECTION OUTPUT ;
    USE SIGNAL ;
    PORT
      LAYER M4 ;
      RECT 0.00000 9.16800 0.03600 9.19200 ;
    END
  END rb_data[190]
  PIN rb_data[191]
    DIRECTION OUTPUT ;
    USE SIGNAL ;
    PORT
      LAYER M4 ;
      RECT 0.00000 9.21600 0.03600 9.24000 ;
    END
  END rb_data[191]
  PIN rb_data[192]
    DIRECTION OUTPUT ;
    USE SIGNAL ;
    PORT
      LAYER M4 ;
      RECT 0.00000 9.26400 0.03600 9.28800 ;
    END
  END rb_data[192]
  PIN rb_data[193]
    DIRECTION OUTPUT ;
    USE SIGNAL ;
    PORT
      LAYER M4 ;
      RECT 0.00000 9.31200 0.03600 9.33600 ;
    END
  END rb_data[193]
  PIN rb_data[194]
    DIRECTION OUTPUT ;
    USE SIGNAL ;
    PORT
      LAYER M4 ;
      RECT 0.00000 9.36000 0.03600 9.38400 ;
    END
  END rb_data[194]
  PIN rb_data[195]
    DIRECTION OUTPUT ;
    USE SIGNAL ;
    PORT
      LAYER M4 ;
      RECT 0.00000 9.40800 0.03600 9.43200 ;
    END
  END rb_data[195]
  PIN rb_data[196]
    DIRECTION OUTPUT ;
    USE SIGNAL ;
    PORT
      LAYER M4 ;
      RECT 0.00000 9.45600 0.03600 9.48000 ;
    END
  END rb_data[196]
  PIN rb_data[197]
    DIRECTION OUTPUT ;
    USE SIGNAL ;
    PORT
      LAYER M4 ;
      RECT 0.00000 9.50400 0.03600 9.52800 ;
    END
  END rb_data[197]
  PIN rb_data[198]
    DIRECTION OUTPUT ;
    USE SIGNAL ;
    PORT
      LAYER M4 ;
      RECT 0.00000 9.55200 0.03600 9.57600 ;
    END
  END rb_data[198]
  PIN rb_data[199]
    DIRECTION OUTPUT ;
    USE SIGNAL ;
    PORT
      LAYER M4 ;
      RECT 0.00000 9.60000 0.03600 9.62400 ;
    END
  END rb_data[199]
  PIN rb_data[200]
    DIRECTION OUTPUT ;
    USE SIGNAL ;
    PORT
      LAYER M4 ;
      RECT 0.00000 9.64800 0.03600 9.67200 ;
    END
  END rb_data[200]
  PIN rb_data[201]
    DIRECTION OUTPUT ;
    USE SIGNAL ;
    PORT
      LAYER M4 ;
      RECT 0.00000 9.69600 0.03600 9.72000 ;
    END
  END rb_data[201]
  PIN rb_data[202]
    DIRECTION OUTPUT ;
    USE SIGNAL ;
    PORT
      LAYER M4 ;
      RECT 0.00000 9.74400 0.03600 9.76800 ;
    END
  END rb_data[202]
  PIN rb_data[203]
    DIRECTION OUTPUT ;
    USE SIGNAL ;
    PORT
      LAYER M4 ;
      RECT 0.00000 9.79200 0.03600 9.81600 ;
    END
  END rb_data[203]
  PIN rb_data[204]
    DIRECTION OUTPUT ;
    USE SIGNAL ;
    PORT
      LAYER M4 ;
      RECT 0.00000 9.84000 0.03600 9.86400 ;
    END
  END rb_data[204]
  PIN rb_data[205]
    DIRECTION OUTPUT ;
    USE SIGNAL ;
    PORT
      LAYER M4 ;
      RECT 0.00000 9.88800 0.03600 9.91200 ;
    END
  END rb_data[205]
  PIN rb_data[206]
    DIRECTION OUTPUT ;
    USE SIGNAL ;
    PORT
      LAYER M4 ;
      RECT 0.00000 9.93600 0.03600 9.96000 ;
    END
  END rb_data[206]
  PIN rb_data[207]
    DIRECTION OUTPUT ;
    USE SIGNAL ;
    PORT
      LAYER M4 ;
      RECT 0.00000 9.98400 0.03600 10.00800 ;
    END
  END rb_data[207]
  PIN rb_data[208]
    DIRECTION OUTPUT ;
    USE SIGNAL ;
    PORT
      LAYER M4 ;
      RECT 0.00000 10.03200 0.03600 10.05600 ;
    END
  END rb_data[208]
  PIN rb_data[209]
    DIRECTION OUTPUT ;
    USE SIGNAL ;
    PORT
      LAYER M4 ;
      RECT 0.00000 10.08000 0.03600 10.10400 ;
    END
  END rb_data[209]
  PIN rb_data[210]
    DIRECTION OUTPUT ;
    USE SIGNAL ;
    PORT
      LAYER M4 ;
      RECT 0.00000 10.12800 0.03600 10.15200 ;
    END
  END rb_data[210]
  PIN rb_data[211]
    DIRECTION OUTPUT ;
    USE SIGNAL ;
    PORT
      LAYER M4 ;
      RECT 0.00000 10.17600 0.03600 10.20000 ;
    END
  END rb_data[211]
  PIN rb_data[212]
    DIRECTION OUTPUT ;
    USE SIGNAL ;
    PORT
      LAYER M4 ;
      RECT 0.00000 10.22400 0.03600 10.24800 ;
    END
  END rb_data[212]
  PIN rb_data[213]
    DIRECTION OUTPUT ;
    USE SIGNAL ;
    PORT
      LAYER M4 ;
      RECT 0.00000 10.27200 0.03600 10.29600 ;
    END
  END rb_data[213]
  PIN rb_data[214]
    DIRECTION OUTPUT ;
    USE SIGNAL ;
    PORT
      LAYER M4 ;
      RECT 0.00000 10.32000 0.03600 10.34400 ;
    END
  END rb_data[214]
  PIN rb_data[215]
    DIRECTION OUTPUT ;
    USE SIGNAL ;
    PORT
      LAYER M4 ;
      RECT 0.00000 10.36800 0.03600 10.39200 ;
    END
  END rb_data[215]
  PIN rb_data[216]
    DIRECTION OUTPUT ;
    USE SIGNAL ;
    PORT
      LAYER M4 ;
      RECT 0.00000 10.41600 0.03600 10.44000 ;
    END
  END rb_data[216]
  PIN rb_data[217]
    DIRECTION OUTPUT ;
    USE SIGNAL ;
    PORT
      LAYER M4 ;
      RECT 0.00000 10.46400 0.03600 10.48800 ;
    END
  END rb_data[217]
  PIN rb_data[218]
    DIRECTION OUTPUT ;
    USE SIGNAL ;
    PORT
      LAYER M4 ;
      RECT 0.00000 10.51200 0.03600 10.53600 ;
    END
  END rb_data[218]
  PIN rb_data[219]
    DIRECTION OUTPUT ;
    USE SIGNAL ;
    PORT
      LAYER M4 ;
      RECT 0.00000 10.56000 0.03600 10.58400 ;
    END
  END rb_data[219]
  PIN rb_data[220]
    DIRECTION OUTPUT ;
    USE SIGNAL ;
    PORT
      LAYER M4 ;
      RECT 0.00000 10.60800 0.03600 10.63200 ;
    END
  END rb_data[220]
  PIN rb_data[221]
    DIRECTION OUTPUT ;
    USE SIGNAL ;
    PORT
      LAYER M4 ;
      RECT 0.00000 10.65600 0.03600 10.68000 ;
    END
  END rb_data[221]
  PIN rb_data[222]
    DIRECTION OUTPUT ;
    USE SIGNAL ;
    PORT
      LAYER M4 ;
      RECT 0.00000 10.70400 0.03600 10.72800 ;
    END
  END rb_data[222]
  PIN rb_data[223]
    DIRECTION OUTPUT ;
    USE SIGNAL ;
    PORT
      LAYER M4 ;
      RECT 0.00000 10.75200 0.03600 10.77600 ;
    END
  END rb_data[223]
  PIN rb_data[224]
    DIRECTION OUTPUT ;
    USE SIGNAL ;
    PORT
      LAYER M4 ;
      RECT 0.00000 10.80000 0.03600 10.82400 ;
    END
  END rb_data[224]
  PIN rb_data[225]
    DIRECTION OUTPUT ;
    USE SIGNAL ;
    PORT
      LAYER M4 ;
      RECT 0.00000 10.84800 0.03600 10.87200 ;
    END
  END rb_data[225]
  PIN rb_data[226]
    DIRECTION OUTPUT ;
    USE SIGNAL ;
    PORT
      LAYER M4 ;
      RECT 0.00000 10.89600 0.03600 10.92000 ;
    END
  END rb_data[226]
  PIN rb_data[227]
    DIRECTION OUTPUT ;
    USE SIGNAL ;
    PORT
      LAYER M4 ;
      RECT 0.00000 10.94400 0.03600 10.96800 ;
    END
  END rb_data[227]
  PIN rb_data[228]
    DIRECTION OUTPUT ;
    USE SIGNAL ;
    PORT
      LAYER M4 ;
      RECT 0.00000 10.99200 0.03600 11.01600 ;
    END
  END rb_data[228]
  PIN rb_data[229]
    DIRECTION OUTPUT ;
    USE SIGNAL ;
    PORT
      LAYER M4 ;
      RECT 0.00000 11.04000 0.03600 11.06400 ;
    END
  END rb_data[229]
  PIN rb_data[230]
    DIRECTION OUTPUT ;
    USE SIGNAL ;
    PORT
      LAYER M4 ;
      RECT 0.00000 11.08800 0.03600 11.11200 ;
    END
  END rb_data[230]
  PIN rb_data[231]
    DIRECTION OUTPUT ;
    USE SIGNAL ;
    PORT
      LAYER M4 ;
      RECT 0.00000 11.13600 0.03600 11.16000 ;
    END
  END rb_data[231]
  PIN rb_data[232]
    DIRECTION OUTPUT ;
    USE SIGNAL ;
    PORT
      LAYER M4 ;
      RECT 0.00000 11.18400 0.03600 11.20800 ;
    END
  END rb_data[232]
  PIN rb_data[233]
    DIRECTION OUTPUT ;
    USE SIGNAL ;
    PORT
      LAYER M4 ;
      RECT 0.00000 11.23200 0.03600 11.25600 ;
    END
  END rb_data[233]
  PIN rb_data[234]
    DIRECTION OUTPUT ;
    USE SIGNAL ;
    PORT
      LAYER M4 ;
      RECT 0.00000 11.28000 0.03600 11.30400 ;
    END
  END rb_data[234]
  PIN rb_data[235]
    DIRECTION OUTPUT ;
    USE SIGNAL ;
    PORT
      LAYER M4 ;
      RECT 0.00000 11.32800 0.03600 11.35200 ;
    END
  END rb_data[235]
  PIN rb_data[236]
    DIRECTION OUTPUT ;
    USE SIGNAL ;
    PORT
      LAYER M4 ;
      RECT 0.00000 11.37600 0.03600 11.40000 ;
    END
  END rb_data[236]
  PIN rb_data[237]
    DIRECTION OUTPUT ;
    USE SIGNAL ;
    PORT
      LAYER M4 ;
      RECT 0.00000 11.42400 0.03600 11.44800 ;
    END
  END rb_data[237]
  PIN rb_data[238]
    DIRECTION OUTPUT ;
    USE SIGNAL ;
    PORT
      LAYER M4 ;
      RECT 0.00000 11.47200 0.03600 11.49600 ;
    END
  END rb_data[238]
  PIN rb_data[239]
    DIRECTION OUTPUT ;
    USE SIGNAL ;
    PORT
      LAYER M4 ;
      RECT 0.00000 11.52000 0.03600 11.54400 ;
    END
  END rb_data[239]
  PIN rb_data[240]
    DIRECTION OUTPUT ;
    USE SIGNAL ;
    PORT
      LAYER M4 ;
      RECT 0.00000 11.56800 0.03600 11.59200 ;
    END
  END rb_data[240]
  PIN rb_data[241]
    DIRECTION OUTPUT ;
    USE SIGNAL ;
    PORT
      LAYER M4 ;
      RECT 0.00000 11.61600 0.03600 11.64000 ;
    END
  END rb_data[241]
  PIN rb_data[242]
    DIRECTION OUTPUT ;
    USE SIGNAL ;
    PORT
      LAYER M4 ;
      RECT 0.00000 11.66400 0.03600 11.68800 ;
    END
  END rb_data[242]
  PIN rb_data[243]
    DIRECTION OUTPUT ;
    USE SIGNAL ;
    PORT
      LAYER M4 ;
      RECT 0.00000 11.71200 0.03600 11.73600 ;
    END
  END rb_data[243]
  PIN rb_data[244]
    DIRECTION OUTPUT ;
    USE SIGNAL ;
    PORT
      LAYER M4 ;
      RECT 0.00000 11.76000 0.03600 11.78400 ;
    END
  END rb_data[244]
  PIN rb_data[245]
    DIRECTION OUTPUT ;
    USE SIGNAL ;
    PORT
      LAYER M4 ;
      RECT 0.00000 11.80800 0.03600 11.83200 ;
    END
  END rb_data[245]
  PIN rb_data[246]
    DIRECTION OUTPUT ;
    USE SIGNAL ;
    PORT
      LAYER M4 ;
      RECT 0.00000 11.85600 0.03600 11.88000 ;
    END
  END rb_data[246]
  PIN rb_data[247]
    DIRECTION OUTPUT ;
    USE SIGNAL ;
    PORT
      LAYER M4 ;
      RECT 0.00000 11.90400 0.03600 11.92800 ;
    END
  END rb_data[247]
  PIN rb_data[248]
    DIRECTION OUTPUT ;
    USE SIGNAL ;
    PORT
      LAYER M4 ;
      RECT 0.00000 11.95200 0.03600 11.97600 ;
    END
  END rb_data[248]
  PIN rb_data[249]
    DIRECTION OUTPUT ;
    USE SIGNAL ;
    PORT
      LAYER M4 ;
      RECT 0.00000 12.00000 0.03600 12.02400 ;
    END
  END rb_data[249]
  PIN rb_data[250]
    DIRECTION OUTPUT ;
    USE SIGNAL ;
    PORT
      LAYER M4 ;
      RECT 0.00000 12.04800 0.03600 12.07200 ;
    END
  END rb_data[250]
  PIN rb_data[251]
    DIRECTION OUTPUT ;
    USE SIGNAL ;
    PORT
      LAYER M4 ;
      RECT 0.00000 12.09600 0.03600 12.12000 ;
    END
  END rb_data[251]
  PIN rb_data[252]
    DIRECTION OUTPUT ;
    USE SIGNAL ;
    PORT
      LAYER M4 ;
      RECT 0.00000 12.14400 0.03600 12.16800 ;
    END
  END rb_data[252]
  PIN rb_data[253]
    DIRECTION OUTPUT ;
    USE SIGNAL ;
    PORT
      LAYER M4 ;
      RECT 0.00000 12.19200 0.03600 12.21600 ;
    END
  END rb_data[253]
  PIN rb_data[254]
    DIRECTION OUTPUT ;
    USE SIGNAL ;
    PORT
      LAYER M4 ;
      RECT 0.00000 12.24000 0.03600 12.26400 ;
    END
  END rb_data[254]
  PIN rb_data[255]
    DIRECTION OUTPUT ;
    USE SIGNAL ;
    PORT
      LAYER M4 ;
      RECT 0.00000 12.28800 0.03600 12.31200 ;
    END
  END rb_data[255]
  PIN rb_data[256]
    DIRECTION OUTPUT ;
    USE SIGNAL ;
    PORT
      LAYER M4 ;
      RECT 0.00000 12.33600 0.03600 12.36000 ;
    END
  END rb_data[256]
  PIN rb_data[257]
    DIRECTION OUTPUT ;
    USE SIGNAL ;
    PORT
      LAYER M4 ;
      RECT 0.00000 12.38400 0.03600 12.40800 ;
    END
  END rb_data[257]
  PIN rb_data[258]
    DIRECTION OUTPUT ;
    USE SIGNAL ;
    PORT
      LAYER M4 ;
      RECT 0.00000 12.43200 0.03600 12.45600 ;
    END
  END rb_data[258]
  PIN rb_data[259]
    DIRECTION OUTPUT ;
    USE SIGNAL ;
    PORT
      LAYER M4 ;
      RECT 0.00000 12.48000 0.03600 12.50400 ;
    END
  END rb_data[259]
  PIN rb_data[260]
    DIRECTION OUTPUT ;
    USE SIGNAL ;
    PORT
      LAYER M4 ;
      RECT 0.00000 12.52800 0.03600 12.55200 ;
    END
  END rb_data[260]
  PIN rb_data[261]
    DIRECTION OUTPUT ;
    USE SIGNAL ;
    PORT
      LAYER M4 ;
      RECT 0.00000 12.57600 0.03600 12.60000 ;
    END
  END rb_data[261]
  PIN rb_data[262]
    DIRECTION OUTPUT ;
    USE SIGNAL ;
    PORT
      LAYER M4 ;
      RECT 0.00000 12.62400 0.03600 12.64800 ;
    END
  END rb_data[262]
  PIN rb_data[263]
    DIRECTION OUTPUT ;
    USE SIGNAL ;
    PORT
      LAYER M4 ;
      RECT 0.00000 12.67200 0.03600 12.69600 ;
    END
  END rb_data[263]
  PIN rb_data[264]
    DIRECTION OUTPUT ;
    USE SIGNAL ;
    PORT
      LAYER M4 ;
      RECT 0.00000 12.72000 0.03600 12.74400 ;
    END
  END rb_data[264]
  PIN rb_data[265]
    DIRECTION OUTPUT ;
    USE SIGNAL ;
    PORT
      LAYER M4 ;
      RECT 0.00000 12.76800 0.03600 12.79200 ;
    END
  END rb_data[265]
  PIN rb_data[266]
    DIRECTION OUTPUT ;
    USE SIGNAL ;
    PORT
      LAYER M4 ;
      RECT 0.00000 12.81600 0.03600 12.84000 ;
    END
  END rb_data[266]
  PIN rb_data[267]
    DIRECTION OUTPUT ;
    USE SIGNAL ;
    PORT
      LAYER M4 ;
      RECT 0.00000 12.86400 0.03600 12.88800 ;
    END
  END rb_data[267]
  PIN rb_data[268]
    DIRECTION OUTPUT ;
    USE SIGNAL ;
    PORT
      LAYER M4 ;
      RECT 0.00000 12.91200 0.03600 12.93600 ;
    END
  END rb_data[268]
  PIN rb_data[269]
    DIRECTION OUTPUT ;
    USE SIGNAL ;
    PORT
      LAYER M4 ;
      RECT 0.00000 12.96000 0.03600 12.98400 ;
    END
  END rb_data[269]
  PIN rb_data[270]
    DIRECTION OUTPUT ;
    USE SIGNAL ;
    PORT
      LAYER M4 ;
      RECT 0.00000 13.00800 0.03600 13.03200 ;
    END
  END rb_data[270]
  PIN rb_data[271]
    DIRECTION OUTPUT ;
    USE SIGNAL ;
    PORT
      LAYER M4 ;
      RECT 0.00000 13.05600 0.03600 13.08000 ;
    END
  END rb_data[271]
  PIN rb_data[272]
    DIRECTION OUTPUT ;
    USE SIGNAL ;
    PORT
      LAYER M4 ;
      RECT 0.00000 13.10400 0.03600 13.12800 ;
    END
  END rb_data[272]
  PIN rb_data[273]
    DIRECTION OUTPUT ;
    USE SIGNAL ;
    PORT
      LAYER M4 ;
      RECT 0.00000 13.15200 0.03600 13.17600 ;
    END
  END rb_data[273]
  PIN rb_data[274]
    DIRECTION OUTPUT ;
    USE SIGNAL ;
    PORT
      LAYER M4 ;
      RECT 0.00000 13.20000 0.03600 13.22400 ;
    END
  END rb_data[274]
  PIN rb_data[275]
    DIRECTION OUTPUT ;
    USE SIGNAL ;
    PORT
      LAYER M4 ;
      RECT 0.00000 13.24800 0.03600 13.27200 ;
    END
  END rb_data[275]
  PIN rb_data[276]
    DIRECTION OUTPUT ;
    USE SIGNAL ;
    PORT
      LAYER M4 ;
      RECT 0.00000 13.29600 0.03600 13.32000 ;
    END
  END rb_data[276]
  PIN rb_data[277]
    DIRECTION OUTPUT ;
    USE SIGNAL ;
    PORT
      LAYER M4 ;
      RECT 0.00000 13.34400 0.03600 13.36800 ;
    END
  END rb_data[277]
  PIN rb_data[278]
    DIRECTION OUTPUT ;
    USE SIGNAL ;
    PORT
      LAYER M4 ;
      RECT 0.00000 13.39200 0.03600 13.41600 ;
    END
  END rb_data[278]
  PIN rb_data[279]
    DIRECTION OUTPUT ;
    USE SIGNAL ;
    PORT
      LAYER M4 ;
      RECT 0.00000 13.44000 0.03600 13.46400 ;
    END
  END rb_data[279]
  PIN rb_data[280]
    DIRECTION OUTPUT ;
    USE SIGNAL ;
    PORT
      LAYER M4 ;
      RECT 0.00000 13.48800 0.03600 13.51200 ;
    END
  END rb_data[280]
  PIN rb_data[281]
    DIRECTION OUTPUT ;
    USE SIGNAL ;
    PORT
      LAYER M4 ;
      RECT 0.00000 13.53600 0.03600 13.56000 ;
    END
  END rb_data[281]
  PIN rb_data[282]
    DIRECTION OUTPUT ;
    USE SIGNAL ;
    PORT
      LAYER M4 ;
      RECT 0.00000 13.58400 0.03600 13.60800 ;
    END
  END rb_data[282]
  PIN rb_data[283]
    DIRECTION OUTPUT ;
    USE SIGNAL ;
    PORT
      LAYER M4 ;
      RECT 0.00000 13.63200 0.03600 13.65600 ;
    END
  END rb_data[283]
  PIN rb_data[284]
    DIRECTION OUTPUT ;
    USE SIGNAL ;
    PORT
      LAYER M4 ;
      RECT 0.00000 13.68000 0.03600 13.70400 ;
    END
  END rb_data[284]
  PIN rb_data[285]
    DIRECTION OUTPUT ;
    USE SIGNAL ;
    PORT
      LAYER M4 ;
      RECT 0.00000 13.72800 0.03600 13.75200 ;
    END
  END rb_data[285]
  PIN rb_data[286]
    DIRECTION OUTPUT ;
    USE SIGNAL ;
    PORT
      LAYER M4 ;
      RECT 0.00000 13.77600 0.03600 13.80000 ;
    END
  END rb_data[286]
  PIN rb_data[287]
    DIRECTION OUTPUT ;
    USE SIGNAL ;
    PORT
      LAYER M4 ;
      RECT 0.00000 13.82400 0.03600 13.84800 ;
    END
  END rb_data[287]
  PIN rb_data[288]
    DIRECTION OUTPUT ;
    USE SIGNAL ;
    PORT
      LAYER M4 ;
      RECT 0.00000 13.87200 0.03600 13.89600 ;
    END
  END rb_data[288]
  PIN rb_data[289]
    DIRECTION OUTPUT ;
    USE SIGNAL ;
    PORT
      LAYER M4 ;
      RECT 0.00000 13.92000 0.03600 13.94400 ;
    END
  END rb_data[289]
  PIN rb_data[290]
    DIRECTION OUTPUT ;
    USE SIGNAL ;
    PORT
      LAYER M4 ;
      RECT 0.00000 13.96800 0.03600 13.99200 ;
    END
  END rb_data[290]
  PIN rb_data[291]
    DIRECTION OUTPUT ;
    USE SIGNAL ;
    PORT
      LAYER M4 ;
      RECT 0.00000 14.01600 0.03600 14.04000 ;
    END
  END rb_data[291]
  PIN rb_data[292]
    DIRECTION OUTPUT ;
    USE SIGNAL ;
    PORT
      LAYER M4 ;
      RECT 0.00000 14.06400 0.03600 14.08800 ;
    END
  END rb_data[292]
  PIN rb_data[293]
    DIRECTION OUTPUT ;
    USE SIGNAL ;
    PORT
      LAYER M4 ;
      RECT 0.00000 14.11200 0.03600 14.13600 ;
    END
  END rb_data[293]
  PIN rb_data[294]
    DIRECTION OUTPUT ;
    USE SIGNAL ;
    PORT
      LAYER M4 ;
      RECT 0.00000 14.16000 0.03600 14.18400 ;
    END
  END rb_data[294]
  PIN rb_data[295]
    DIRECTION OUTPUT ;
    USE SIGNAL ;
    PORT
      LAYER M4 ;
      RECT 0.00000 14.20800 0.03600 14.23200 ;
    END
  END rb_data[295]
  PIN rb_data[296]
    DIRECTION OUTPUT ;
    USE SIGNAL ;
    PORT
      LAYER M4 ;
      RECT 0.00000 14.25600 0.03600 14.28000 ;
    END
  END rb_data[296]
  PIN rb_data[297]
    DIRECTION OUTPUT ;
    USE SIGNAL ;
    PORT
      LAYER M4 ;
      RECT 0.00000 14.30400 0.03600 14.32800 ;
    END
  END rb_data[297]
  PIN rb_data[298]
    DIRECTION OUTPUT ;
    USE SIGNAL ;
    PORT
      LAYER M4 ;
      RECT 0.00000 14.35200 0.03600 14.37600 ;
    END
  END rb_data[298]
  PIN rb_data[299]
    DIRECTION OUTPUT ;
    USE SIGNAL ;
    PORT
      LAYER M4 ;
      RECT 0.00000 14.40000 0.03600 14.42400 ;
    END
  END rb_data[299]
  PIN rb_data[300]
    DIRECTION OUTPUT ;
    USE SIGNAL ;
    PORT
      LAYER M4 ;
      RECT 0.00000 14.44800 0.03600 14.47200 ;
    END
  END rb_data[300]
  PIN rb_data[301]
    DIRECTION OUTPUT ;
    USE SIGNAL ;
    PORT
      LAYER M4 ;
      RECT 0.00000 14.49600 0.03600 14.52000 ;
    END
  END rb_data[301]
  PIN rb_data[302]
    DIRECTION OUTPUT ;
    USE SIGNAL ;
    PORT
      LAYER M4 ;
      RECT 0.00000 14.54400 0.03600 14.56800 ;
    END
  END rb_data[302]
  PIN rb_data[303]
    DIRECTION OUTPUT ;
    USE SIGNAL ;
    PORT
      LAYER M4 ;
      RECT 0.00000 14.59200 0.03600 14.61600 ;
    END
  END rb_data[303]
  PIN rb_data[304]
    DIRECTION OUTPUT ;
    USE SIGNAL ;
    PORT
      LAYER M4 ;
      RECT 0.00000 14.64000 0.03600 14.66400 ;
    END
  END rb_data[304]
  PIN rb_data[305]
    DIRECTION OUTPUT ;
    USE SIGNAL ;
    PORT
      LAYER M4 ;
      RECT 0.00000 14.68800 0.03600 14.71200 ;
    END
  END rb_data[305]
  PIN rb_data[306]
    DIRECTION OUTPUT ;
    USE SIGNAL ;
    PORT
      LAYER M4 ;
      RECT 0.00000 14.73600 0.03600 14.76000 ;
    END
  END rb_data[306]
  PIN rb_data[307]
    DIRECTION OUTPUT ;
    USE SIGNAL ;
    PORT
      LAYER M4 ;
      RECT 0.00000 14.78400 0.03600 14.80800 ;
    END
  END rb_data[307]
  PIN rb_data[308]
    DIRECTION OUTPUT ;
    USE SIGNAL ;
    PORT
      LAYER M4 ;
      RECT 0.00000 14.83200 0.03600 14.85600 ;
    END
  END rb_data[308]
  PIN rb_data[309]
    DIRECTION OUTPUT ;
    USE SIGNAL ;
    PORT
      LAYER M4 ;
      RECT 0.00000 14.88000 0.03600 14.90400 ;
    END
  END rb_data[309]
  PIN rb_data[310]
    DIRECTION OUTPUT ;
    USE SIGNAL ;
    PORT
      LAYER M4 ;
      RECT 0.00000 14.92800 0.03600 14.95200 ;
    END
  END rb_data[310]
  PIN rb_data[311]
    DIRECTION OUTPUT ;
    USE SIGNAL ;
    PORT
      LAYER M4 ;
      RECT 0.00000 14.97600 0.03600 15.00000 ;
    END
  END rb_data[311]
  PIN rb_data[312]
    DIRECTION OUTPUT ;
    USE SIGNAL ;
    PORT
      LAYER M4 ;
      RECT 0.00000 15.02400 0.03600 15.04800 ;
    END
  END rb_data[312]
  PIN rb_data[313]
    DIRECTION OUTPUT ;
    USE SIGNAL ;
    PORT
      LAYER M4 ;
      RECT 0.00000 15.07200 0.03600 15.09600 ;
    END
  END rb_data[313]
  PIN rb_data[314]
    DIRECTION OUTPUT ;
    USE SIGNAL ;
    PORT
      LAYER M4 ;
      RECT 0.00000 15.12000 0.03600 15.14400 ;
    END
  END rb_data[314]
  PIN rb_data[315]
    DIRECTION OUTPUT ;
    USE SIGNAL ;
    PORT
      LAYER M4 ;
      RECT 0.00000 15.16800 0.03600 15.19200 ;
    END
  END rb_data[315]
  PIN rb_data[316]
    DIRECTION OUTPUT ;
    USE SIGNAL ;
    PORT
      LAYER M4 ;
      RECT 0.00000 15.21600 0.03600 15.24000 ;
    END
  END rb_data[316]
  PIN rb_data[317]
    DIRECTION OUTPUT ;
    USE SIGNAL ;
    PORT
      LAYER M4 ;
      RECT 0.00000 15.26400 0.03600 15.28800 ;
    END
  END rb_data[317]
  PIN rb_data[318]
    DIRECTION OUTPUT ;
    USE SIGNAL ;
    PORT
      LAYER M4 ;
      RECT 0.00000 15.31200 0.03600 15.33600 ;
    END
  END rb_data[318]
  PIN rb_data[319]
    DIRECTION OUTPUT ;
    USE SIGNAL ;
    PORT
      LAYER M4 ;
      RECT 0.00000 15.36000 0.03600 15.38400 ;
    END
  END rb_data[319]
  PIN rb_data[320]
    DIRECTION OUTPUT ;
    USE SIGNAL ;
    PORT
      LAYER M4 ;
      RECT 0.00000 15.40800 0.03600 15.43200 ;
    END
  END rb_data[320]
  PIN rb_data[321]
    DIRECTION OUTPUT ;
    USE SIGNAL ;
    PORT
      LAYER M4 ;
      RECT 0.00000 15.45600 0.03600 15.48000 ;
    END
  END rb_data[321]
  PIN rb_data[322]
    DIRECTION OUTPUT ;
    USE SIGNAL ;
    PORT
      LAYER M4 ;
      RECT 0.00000 15.50400 0.03600 15.52800 ;
    END
  END rb_data[322]
  PIN rb_data[323]
    DIRECTION OUTPUT ;
    USE SIGNAL ;
    PORT
      LAYER M4 ;
      RECT 0.00000 15.55200 0.03600 15.57600 ;
    END
  END rb_data[323]
  PIN rb_data[324]
    DIRECTION OUTPUT ;
    USE SIGNAL ;
    PORT
      LAYER M4 ;
      RECT 0.00000 15.60000 0.03600 15.62400 ;
    END
  END rb_data[324]
  PIN rb_data[325]
    DIRECTION OUTPUT ;
    USE SIGNAL ;
    PORT
      LAYER M4 ;
      RECT 0.00000 15.64800 0.03600 15.67200 ;
    END
  END rb_data[325]
  PIN rb_data[326]
    DIRECTION OUTPUT ;
    USE SIGNAL ;
    PORT
      LAYER M4 ;
      RECT 0.00000 15.69600 0.03600 15.72000 ;
    END
  END rb_data[326]
  PIN rb_data[327]
    DIRECTION OUTPUT ;
    USE SIGNAL ;
    PORT
      LAYER M4 ;
      RECT 0.00000 15.74400 0.03600 15.76800 ;
    END
  END rb_data[327]
  PIN rb_data[328]
    DIRECTION OUTPUT ;
    USE SIGNAL ;
    PORT
      LAYER M4 ;
      RECT 0.00000 15.79200 0.03600 15.81600 ;
    END
  END rb_data[328]
  PIN rb_data[329]
    DIRECTION OUTPUT ;
    USE SIGNAL ;
    PORT
      LAYER M4 ;
      RECT 0.00000 15.84000 0.03600 15.86400 ;
    END
  END rb_data[329]
  PIN rb_data[330]
    DIRECTION OUTPUT ;
    USE SIGNAL ;
    PORT
      LAYER M4 ;
      RECT 0.00000 15.88800 0.03600 15.91200 ;
    END
  END rb_data[330]
  PIN rb_data[331]
    DIRECTION OUTPUT ;
    USE SIGNAL ;
    PORT
      LAYER M4 ;
      RECT 0.00000 15.93600 0.03600 15.96000 ;
    END
  END rb_data[331]
  PIN rb_data[332]
    DIRECTION OUTPUT ;
    USE SIGNAL ;
    PORT
      LAYER M4 ;
      RECT 0.00000 15.98400 0.03600 16.00800 ;
    END
  END rb_data[332]
  PIN rb_data[333]
    DIRECTION OUTPUT ;
    USE SIGNAL ;
    PORT
      LAYER M4 ;
      RECT 0.00000 16.03200 0.03600 16.05600 ;
    END
  END rb_data[333]
  PIN rb_data[334]
    DIRECTION OUTPUT ;
    USE SIGNAL ;
    PORT
      LAYER M4 ;
      RECT 0.00000 16.08000 0.03600 16.10400 ;
    END
  END rb_data[334]
  PIN rb_data[335]
    DIRECTION OUTPUT ;
    USE SIGNAL ;
    PORT
      LAYER M4 ;
      RECT 0.00000 16.12800 0.03600 16.15200 ;
    END
  END rb_data[335]
  PIN rb_data[336]
    DIRECTION OUTPUT ;
    USE SIGNAL ;
    PORT
      LAYER M4 ;
      RECT 0.00000 16.17600 0.03600 16.20000 ;
    END
  END rb_data[336]
  PIN rb_data[337]
    DIRECTION OUTPUT ;
    USE SIGNAL ;
    PORT
      LAYER M4 ;
      RECT 0.00000 16.22400 0.03600 16.24800 ;
    END
  END rb_data[337]
  PIN rb_data[338]
    DIRECTION OUTPUT ;
    USE SIGNAL ;
    PORT
      LAYER M4 ;
      RECT 0.00000 16.27200 0.03600 16.29600 ;
    END
  END rb_data[338]
  PIN rb_data[339]
    DIRECTION OUTPUT ;
    USE SIGNAL ;
    PORT
      LAYER M4 ;
      RECT 0.00000 16.32000 0.03600 16.34400 ;
    END
  END rb_data[339]
  PIN rb_data[340]
    DIRECTION OUTPUT ;
    USE SIGNAL ;
    PORT
      LAYER M4 ;
      RECT 0.00000 16.36800 0.03600 16.39200 ;
    END
  END rb_data[340]
  PIN rb_data[341]
    DIRECTION OUTPUT ;
    USE SIGNAL ;
    PORT
      LAYER M4 ;
      RECT 0.00000 16.41600 0.03600 16.44000 ;
    END
  END rb_data[341]
  PIN rb_data[342]
    DIRECTION OUTPUT ;
    USE SIGNAL ;
    PORT
      LAYER M4 ;
      RECT 0.00000 16.46400 0.03600 16.48800 ;
    END
  END rb_data[342]
  PIN rb_data[343]
    DIRECTION OUTPUT ;
    USE SIGNAL ;
    PORT
      LAYER M4 ;
      RECT 0.00000 16.51200 0.03600 16.53600 ;
    END
  END rb_data[343]
  PIN rb_data[344]
    DIRECTION OUTPUT ;
    USE SIGNAL ;
    PORT
      LAYER M4 ;
      RECT 0.00000 16.56000 0.03600 16.58400 ;
    END
  END rb_data[344]
  PIN rb_data[345]
    DIRECTION OUTPUT ;
    USE SIGNAL ;
    PORT
      LAYER M4 ;
      RECT 0.00000 16.60800 0.03600 16.63200 ;
    END
  END rb_data[345]
  PIN rb_data[346]
    DIRECTION OUTPUT ;
    USE SIGNAL ;
    PORT
      LAYER M4 ;
      RECT 0.00000 16.65600 0.03600 16.68000 ;
    END
  END rb_data[346]
  PIN rb_data[347]
    DIRECTION OUTPUT ;
    USE SIGNAL ;
    PORT
      LAYER M4 ;
      RECT 0.00000 16.70400 0.03600 16.72800 ;
    END
  END rb_data[347]
  PIN rb_data[348]
    DIRECTION OUTPUT ;
    USE SIGNAL ;
    PORT
      LAYER M4 ;
      RECT 0.00000 16.75200 0.03600 16.77600 ;
    END
  END rb_data[348]
  PIN rb_data[349]
    DIRECTION OUTPUT ;
    USE SIGNAL ;
    PORT
      LAYER M4 ;
      RECT 0.00000 16.80000 0.03600 16.82400 ;
    END
  END rb_data[349]
  PIN rb_data[350]
    DIRECTION OUTPUT ;
    USE SIGNAL ;
    PORT
      LAYER M4 ;
      RECT 0.00000 16.84800 0.03600 16.87200 ;
    END
  END rb_data[350]
  PIN rb_data[351]
    DIRECTION OUTPUT ;
    USE SIGNAL ;
    PORT
      LAYER M4 ;
      RECT 0.00000 16.89600 0.03600 16.92000 ;
    END
  END rb_data[351]
  PIN rb_data[352]
    DIRECTION OUTPUT ;
    USE SIGNAL ;
    PORT
      LAYER M4 ;
      RECT 0.00000 16.94400 0.03600 16.96800 ;
    END
  END rb_data[352]
  PIN rb_data[353]
    DIRECTION OUTPUT ;
    USE SIGNAL ;
    PORT
      LAYER M4 ;
      RECT 0.00000 16.99200 0.03600 17.01600 ;
    END
  END rb_data[353]
  PIN rb_data[354]
    DIRECTION OUTPUT ;
    USE SIGNAL ;
    PORT
      LAYER M4 ;
      RECT 0.00000 17.04000 0.03600 17.06400 ;
    END
  END rb_data[354]
  PIN rb_data[355]
    DIRECTION OUTPUT ;
    USE SIGNAL ;
    PORT
      LAYER M4 ;
      RECT 0.00000 17.08800 0.03600 17.11200 ;
    END
  END rb_data[355]
  PIN rb_data[356]
    DIRECTION OUTPUT ;
    USE SIGNAL ;
    PORT
      LAYER M4 ;
      RECT 0.00000 17.13600 0.03600 17.16000 ;
    END
  END rb_data[356]
  PIN rb_data[357]
    DIRECTION OUTPUT ;
    USE SIGNAL ;
    PORT
      LAYER M4 ;
      RECT 0.00000 17.18400 0.03600 17.20800 ;
    END
  END rb_data[357]
  PIN rb_data[358]
    DIRECTION OUTPUT ;
    USE SIGNAL ;
    PORT
      LAYER M4 ;
      RECT 0.00000 17.23200 0.03600 17.25600 ;
    END
  END rb_data[358]
  PIN rb_data[359]
    DIRECTION OUTPUT ;
    USE SIGNAL ;
    PORT
      LAYER M4 ;
      RECT 0.00000 17.28000 0.03600 17.30400 ;
    END
  END rb_data[359]
  PIN rb_data[360]
    DIRECTION OUTPUT ;
    USE SIGNAL ;
    PORT
      LAYER M4 ;
      RECT 0.00000 17.32800 0.03600 17.35200 ;
    END
  END rb_data[360]
  PIN rb_data[361]
    DIRECTION OUTPUT ;
    USE SIGNAL ;
    PORT
      LAYER M4 ;
      RECT 0.00000 17.37600 0.03600 17.40000 ;
    END
  END rb_data[361]
  PIN rb_data[362]
    DIRECTION OUTPUT ;
    USE SIGNAL ;
    PORT
      LAYER M4 ;
      RECT 0.00000 17.42400 0.03600 17.44800 ;
    END
  END rb_data[362]
  PIN rb_data[363]
    DIRECTION OUTPUT ;
    USE SIGNAL ;
    PORT
      LAYER M4 ;
      RECT 0.00000 17.47200 0.03600 17.49600 ;
    END
  END rb_data[363]
  PIN rb_data[364]
    DIRECTION OUTPUT ;
    USE SIGNAL ;
    PORT
      LAYER M4 ;
      RECT 0.00000 17.52000 0.03600 17.54400 ;
    END
  END rb_data[364]
  PIN rb_data[365]
    DIRECTION OUTPUT ;
    USE SIGNAL ;
    PORT
      LAYER M4 ;
      RECT 0.00000 17.56800 0.03600 17.59200 ;
    END
  END rb_data[365]
  PIN rb_data[366]
    DIRECTION OUTPUT ;
    USE SIGNAL ;
    PORT
      LAYER M4 ;
      RECT 0.00000 17.61600 0.03600 17.64000 ;
    END
  END rb_data[366]
  PIN rb_data[367]
    DIRECTION OUTPUT ;
    USE SIGNAL ;
    PORT
      LAYER M4 ;
      RECT 0.00000 17.66400 0.03600 17.68800 ;
    END
  END rb_data[367]
  PIN rb_data[368]
    DIRECTION OUTPUT ;
    USE SIGNAL ;
    PORT
      LAYER M4 ;
      RECT 0.00000 17.71200 0.03600 17.73600 ;
    END
  END rb_data[368]
  PIN rb_data[369]
    DIRECTION OUTPUT ;
    USE SIGNAL ;
    PORT
      LAYER M4 ;
      RECT 0.00000 17.76000 0.03600 17.78400 ;
    END
  END rb_data[369]
  PIN rb_data[370]
    DIRECTION OUTPUT ;
    USE SIGNAL ;
    PORT
      LAYER M4 ;
      RECT 0.00000 17.80800 0.03600 17.83200 ;
    END
  END rb_data[370]
  PIN rb_data[371]
    DIRECTION OUTPUT ;
    USE SIGNAL ;
    PORT
      LAYER M4 ;
      RECT 0.00000 17.85600 0.03600 17.88000 ;
    END
  END rb_data[371]
  PIN rb_data[372]
    DIRECTION OUTPUT ;
    USE SIGNAL ;
    PORT
      LAYER M4 ;
      RECT 0.00000 17.90400 0.03600 17.92800 ;
    END
  END rb_data[372]
  PIN rb_data[373]
    DIRECTION OUTPUT ;
    USE SIGNAL ;
    PORT
      LAYER M4 ;
      RECT 0.00000 17.95200 0.03600 17.97600 ;
    END
  END rb_data[373]
  PIN rb_data[374]
    DIRECTION OUTPUT ;
    USE SIGNAL ;
    PORT
      LAYER M4 ;
      RECT 0.00000 18.00000 0.03600 18.02400 ;
    END
  END rb_data[374]
  PIN rb_data[375]
    DIRECTION OUTPUT ;
    USE SIGNAL ;
    PORT
      LAYER M4 ;
      RECT 0.00000 18.04800 0.03600 18.07200 ;
    END
  END rb_data[375]
  PIN rb_data[376]
    DIRECTION OUTPUT ;
    USE SIGNAL ;
    PORT
      LAYER M4 ;
      RECT 0.00000 18.09600 0.03600 18.12000 ;
    END
  END rb_data[376]
  PIN rb_data[377]
    DIRECTION OUTPUT ;
    USE SIGNAL ;
    PORT
      LAYER M4 ;
      RECT 0.00000 18.14400 0.03600 18.16800 ;
    END
  END rb_data[377]
  PIN rb_data[378]
    DIRECTION OUTPUT ;
    USE SIGNAL ;
    PORT
      LAYER M4 ;
      RECT 0.00000 18.19200 0.03600 18.21600 ;
    END
  END rb_data[378]
  PIN rb_data[379]
    DIRECTION OUTPUT ;
    USE SIGNAL ;
    PORT
      LAYER M4 ;
      RECT 0.00000 18.24000 0.03600 18.26400 ;
    END
  END rb_data[379]
  PIN rb_data[380]
    DIRECTION OUTPUT ;
    USE SIGNAL ;
    PORT
      LAYER M4 ;
      RECT 0.00000 18.28800 0.03600 18.31200 ;
    END
  END rb_data[380]
  PIN rb_data[381]
    DIRECTION OUTPUT ;
    USE SIGNAL ;
    PORT
      LAYER M4 ;
      RECT 0.00000 18.33600 0.03600 18.36000 ;
    END
  END rb_data[381]
  PIN rb_data[382]
    DIRECTION OUTPUT ;
    USE SIGNAL ;
    PORT
      LAYER M4 ;
      RECT 0.00000 18.38400 0.03600 18.40800 ;
    END
  END rb_data[382]
  PIN rb_data[383]
    DIRECTION OUTPUT ;
    USE SIGNAL ;
    PORT
      LAYER M4 ;
      RECT 0.00000 18.43200 0.03600 18.45600 ;
    END
  END rb_data[383]
  PIN rb_data[384]
    DIRECTION OUTPUT ;
    USE SIGNAL ;
    PORT
      LAYER M4 ;
      RECT 0.00000 18.48000 0.03600 18.50400 ;
    END
  END rb_data[384]
  PIN rb_data[385]
    DIRECTION OUTPUT ;
    USE SIGNAL ;
    PORT
      LAYER M4 ;
      RECT 0.00000 18.52800 0.03600 18.55200 ;
    END
  END rb_data[385]
  PIN rb_data[386]
    DIRECTION OUTPUT ;
    USE SIGNAL ;
    PORT
      LAYER M4 ;
      RECT 0.00000 18.57600 0.03600 18.60000 ;
    END
  END rb_data[386]
  PIN rb_data[387]
    DIRECTION OUTPUT ;
    USE SIGNAL ;
    PORT
      LAYER M4 ;
      RECT 0.00000 18.62400 0.03600 18.64800 ;
    END
  END rb_data[387]
  PIN rb_data[388]
    DIRECTION OUTPUT ;
    USE SIGNAL ;
    PORT
      LAYER M4 ;
      RECT 0.00000 18.67200 0.03600 18.69600 ;
    END
  END rb_data[388]
  PIN rb_data[389]
    DIRECTION OUTPUT ;
    USE SIGNAL ;
    PORT
      LAYER M4 ;
      RECT 0.00000 18.72000 0.03600 18.74400 ;
    END
  END rb_data[389]
  PIN rb_data[390]
    DIRECTION OUTPUT ;
    USE SIGNAL ;
    PORT
      LAYER M4 ;
      RECT 0.00000 18.76800 0.03600 18.79200 ;
    END
  END rb_data[390]
  PIN rb_data[391]
    DIRECTION OUTPUT ;
    USE SIGNAL ;
    PORT
      LAYER M4 ;
      RECT 0.00000 18.81600 0.03600 18.84000 ;
    END
  END rb_data[391]
  PIN rb_data[392]
    DIRECTION OUTPUT ;
    USE SIGNAL ;
    PORT
      LAYER M4 ;
      RECT 0.00000 18.86400 0.03600 18.88800 ;
    END
  END rb_data[392]
  PIN rb_data[393]
    DIRECTION OUTPUT ;
    USE SIGNAL ;
    PORT
      LAYER M4 ;
      RECT 0.00000 18.91200 0.03600 18.93600 ;
    END
  END rb_data[393]
  PIN rb_data[394]
    DIRECTION OUTPUT ;
    USE SIGNAL ;
    PORT
      LAYER M4 ;
      RECT 0.00000 18.96000 0.03600 18.98400 ;
    END
  END rb_data[394]
  PIN rb_data[395]
    DIRECTION OUTPUT ;
    USE SIGNAL ;
    PORT
      LAYER M4 ;
      RECT 0.00000 19.00800 0.03600 19.03200 ;
    END
  END rb_data[395]
  PIN rb_data[396]
    DIRECTION OUTPUT ;
    USE SIGNAL ;
    PORT
      LAYER M4 ;
      RECT 0.00000 19.05600 0.03600 19.08000 ;
    END
  END rb_data[396]
  PIN rb_data[397]
    DIRECTION OUTPUT ;
    USE SIGNAL ;
    PORT
      LAYER M4 ;
      RECT 0.00000 19.10400 0.03600 19.12800 ;
    END
  END rb_data[397]
  PIN rb_data[398]
    DIRECTION OUTPUT ;
    USE SIGNAL ;
    PORT
      LAYER M4 ;
      RECT 0.00000 19.15200 0.03600 19.17600 ;
    END
  END rb_data[398]
  PIN rb_data[399]
    DIRECTION OUTPUT ;
    USE SIGNAL ;
    PORT
      LAYER M4 ;
      RECT 0.00000 19.20000 0.03600 19.22400 ;
    END
  END rb_data[399]
  PIN rb_data[400]
    DIRECTION OUTPUT ;
    USE SIGNAL ;
    PORT
      LAYER M4 ;
      RECT 0.00000 19.24800 0.03600 19.27200 ;
    END
  END rb_data[400]
  PIN rb_data[401]
    DIRECTION OUTPUT ;
    USE SIGNAL ;
    PORT
      LAYER M4 ;
      RECT 0.00000 19.29600 0.03600 19.32000 ;
    END
  END rb_data[401]
  PIN rb_data[402]
    DIRECTION OUTPUT ;
    USE SIGNAL ;
    PORT
      LAYER M4 ;
      RECT 0.00000 19.34400 0.03600 19.36800 ;
    END
  END rb_data[402]
  PIN rb_data[403]
    DIRECTION OUTPUT ;
    USE SIGNAL ;
    PORT
      LAYER M4 ;
      RECT 0.00000 19.39200 0.03600 19.41600 ;
    END
  END rb_data[403]
  PIN rb_data[404]
    DIRECTION OUTPUT ;
    USE SIGNAL ;
    PORT
      LAYER M4 ;
      RECT 0.00000 19.44000 0.03600 19.46400 ;
    END
  END rb_data[404]
  PIN rb_data[405]
    DIRECTION OUTPUT ;
    USE SIGNAL ;
    PORT
      LAYER M4 ;
      RECT 0.00000 19.48800 0.03600 19.51200 ;
    END
  END rb_data[405]
  PIN rb_data[406]
    DIRECTION OUTPUT ;
    USE SIGNAL ;
    PORT
      LAYER M4 ;
      RECT 0.00000 19.53600 0.03600 19.56000 ;
    END
  END rb_data[406]
  PIN rb_data[407]
    DIRECTION OUTPUT ;
    USE SIGNAL ;
    PORT
      LAYER M4 ;
      RECT 0.00000 19.58400 0.03600 19.60800 ;
    END
  END rb_data[407]
  PIN rb_data[408]
    DIRECTION OUTPUT ;
    USE SIGNAL ;
    PORT
      LAYER M4 ;
      RECT 0.00000 19.63200 0.03600 19.65600 ;
    END
  END rb_data[408]
  PIN rb_data[409]
    DIRECTION OUTPUT ;
    USE SIGNAL ;
    PORT
      LAYER M4 ;
      RECT 0.00000 19.68000 0.03600 19.70400 ;
    END
  END rb_data[409]
  PIN rb_data[410]
    DIRECTION OUTPUT ;
    USE SIGNAL ;
    PORT
      LAYER M4 ;
      RECT 0.00000 19.72800 0.03600 19.75200 ;
    END
  END rb_data[410]
  PIN rb_data[411]
    DIRECTION OUTPUT ;
    USE SIGNAL ;
    PORT
      LAYER M4 ;
      RECT 0.00000 19.77600 0.03600 19.80000 ;
    END
  END rb_data[411]
  PIN rb_data[412]
    DIRECTION OUTPUT ;
    USE SIGNAL ;
    PORT
      LAYER M4 ;
      RECT 0.00000 19.82400 0.03600 19.84800 ;
    END
  END rb_data[412]
  PIN rb_data[413]
    DIRECTION OUTPUT ;
    USE SIGNAL ;
    PORT
      LAYER M4 ;
      RECT 0.00000 19.87200 0.03600 19.89600 ;
    END
  END rb_data[413]
  PIN rb_data[414]
    DIRECTION OUTPUT ;
    USE SIGNAL ;
    PORT
      LAYER M4 ;
      RECT 0.00000 19.92000 0.03600 19.94400 ;
    END
  END rb_data[414]
  PIN rb_data[415]
    DIRECTION OUTPUT ;
    USE SIGNAL ;
    PORT
      LAYER M4 ;
      RECT 0.00000 19.96800 0.03600 19.99200 ;
    END
  END rb_data[415]
  PIN rb_data[416]
    DIRECTION OUTPUT ;
    USE SIGNAL ;
    PORT
      LAYER M4 ;
      RECT 0.00000 20.01600 0.03600 20.04000 ;
    END
  END rb_data[416]
  PIN rb_data[417]
    DIRECTION OUTPUT ;
    USE SIGNAL ;
    PORT
      LAYER M4 ;
      RECT 0.00000 20.06400 0.03600 20.08800 ;
    END
  END rb_data[417]
  PIN rb_data[418]
    DIRECTION OUTPUT ;
    USE SIGNAL ;
    PORT
      LAYER M4 ;
      RECT 0.00000 20.11200 0.03600 20.13600 ;
    END
  END rb_data[418]
  PIN rb_data[419]
    DIRECTION OUTPUT ;
    USE SIGNAL ;
    PORT
      LAYER M4 ;
      RECT 0.00000 20.16000 0.03600 20.18400 ;
    END
  END rb_data[419]
  PIN rb_data[420]
    DIRECTION OUTPUT ;
    USE SIGNAL ;
    PORT
      LAYER M4 ;
      RECT 0.00000 20.20800 0.03600 20.23200 ;
    END
  END rb_data[420]
  PIN rb_data[421]
    DIRECTION OUTPUT ;
    USE SIGNAL ;
    PORT
      LAYER M4 ;
      RECT 0.00000 20.25600 0.03600 20.28000 ;
    END
  END rb_data[421]
  PIN rb_data[422]
    DIRECTION OUTPUT ;
    USE SIGNAL ;
    PORT
      LAYER M4 ;
      RECT 0.00000 20.30400 0.03600 20.32800 ;
    END
  END rb_data[422]
  PIN rb_data[423]
    DIRECTION OUTPUT ;
    USE SIGNAL ;
    PORT
      LAYER M4 ;
      RECT 0.00000 20.35200 0.03600 20.37600 ;
    END
  END rb_data[423]
  PIN rb_data[424]
    DIRECTION OUTPUT ;
    USE SIGNAL ;
    PORT
      LAYER M4 ;
      RECT 0.00000 20.40000 0.03600 20.42400 ;
    END
  END rb_data[424]
  PIN rb_data[425]
    DIRECTION OUTPUT ;
    USE SIGNAL ;
    PORT
      LAYER M4 ;
      RECT 0.00000 20.44800 0.03600 20.47200 ;
    END
  END rb_data[425]
  PIN rb_data[426]
    DIRECTION OUTPUT ;
    USE SIGNAL ;
    PORT
      LAYER M4 ;
      RECT 0.00000 20.49600 0.03600 20.52000 ;
    END
  END rb_data[426]
  PIN rb_data[427]
    DIRECTION OUTPUT ;
    USE SIGNAL ;
    PORT
      LAYER M4 ;
      RECT 0.00000 20.54400 0.03600 20.56800 ;
    END
  END rb_data[427]
  PIN rb_data[428]
    DIRECTION OUTPUT ;
    USE SIGNAL ;
    PORT
      LAYER M4 ;
      RECT 0.00000 20.59200 0.03600 20.61600 ;
    END
  END rb_data[428]
  PIN rb_data[429]
    DIRECTION OUTPUT ;
    USE SIGNAL ;
    PORT
      LAYER M4 ;
      RECT 0.00000 20.64000 0.03600 20.66400 ;
    END
  END rb_data[429]
  PIN rb_data[430]
    DIRECTION OUTPUT ;
    USE SIGNAL ;
    PORT
      LAYER M4 ;
      RECT 0.00000 20.68800 0.03600 20.71200 ;
    END
  END rb_data[430]
  PIN rb_data[431]
    DIRECTION OUTPUT ;
    USE SIGNAL ;
    PORT
      LAYER M4 ;
      RECT 0.00000 20.73600 0.03600 20.76000 ;
    END
  END rb_data[431]
  PIN rb_data[432]
    DIRECTION OUTPUT ;
    USE SIGNAL ;
    PORT
      LAYER M4 ;
      RECT 0.00000 20.78400 0.03600 20.80800 ;
    END
  END rb_data[432]
  PIN rb_data[433]
    DIRECTION OUTPUT ;
    USE SIGNAL ;
    PORT
      LAYER M4 ;
      RECT 0.00000 20.83200 0.03600 20.85600 ;
    END
  END rb_data[433]
  PIN rb_data[434]
    DIRECTION OUTPUT ;
    USE SIGNAL ;
    PORT
      LAYER M4 ;
      RECT 0.00000 20.88000 0.03600 20.90400 ;
    END
  END rb_data[434]
  PIN rb_data[435]
    DIRECTION OUTPUT ;
    USE SIGNAL ;
    PORT
      LAYER M4 ;
      RECT 0.00000 20.92800 0.03600 20.95200 ;
    END
  END rb_data[435]
  PIN rb_data[436]
    DIRECTION OUTPUT ;
    USE SIGNAL ;
    PORT
      LAYER M4 ;
      RECT 0.00000 20.97600 0.03600 21.00000 ;
    END
  END rb_data[436]
  PIN rb_data[437]
    DIRECTION OUTPUT ;
    USE SIGNAL ;
    PORT
      LAYER M4 ;
      RECT 0.00000 21.02400 0.03600 21.04800 ;
    END
  END rb_data[437]
  PIN rb_data[438]
    DIRECTION OUTPUT ;
    USE SIGNAL ;
    PORT
      LAYER M4 ;
      RECT 0.00000 21.07200 0.03600 21.09600 ;
    END
  END rb_data[438]
  PIN rb_data[439]
    DIRECTION OUTPUT ;
    USE SIGNAL ;
    PORT
      LAYER M4 ;
      RECT 0.00000 21.12000 0.03600 21.14400 ;
    END
  END rb_data[439]
  PIN rb_data[440]
    DIRECTION OUTPUT ;
    USE SIGNAL ;
    PORT
      LAYER M4 ;
      RECT 0.00000 21.16800 0.03600 21.19200 ;
    END
  END rb_data[440]
  PIN rb_data[441]
    DIRECTION OUTPUT ;
    USE SIGNAL ;
    PORT
      LAYER M4 ;
      RECT 0.00000 21.21600 0.03600 21.24000 ;
    END
  END rb_data[441]
  PIN rb_data[442]
    DIRECTION OUTPUT ;
    USE SIGNAL ;
    PORT
      LAYER M4 ;
      RECT 0.00000 21.26400 0.03600 21.28800 ;
    END
  END rb_data[442]
  PIN rb_data[443]
    DIRECTION OUTPUT ;
    USE SIGNAL ;
    PORT
      LAYER M4 ;
      RECT 0.00000 21.31200 0.03600 21.33600 ;
    END
  END rb_data[443]
  PIN rb_data[444]
    DIRECTION OUTPUT ;
    USE SIGNAL ;
    PORT
      LAYER M4 ;
      RECT 0.00000 21.36000 0.03600 21.38400 ;
    END
  END rb_data[444]
  PIN rb_data[445]
    DIRECTION OUTPUT ;
    USE SIGNAL ;
    PORT
      LAYER M4 ;
      RECT 0.00000 21.40800 0.03600 21.43200 ;
    END
  END rb_data[445]
  PIN rb_data[446]
    DIRECTION OUTPUT ;
    USE SIGNAL ;
    PORT
      LAYER M4 ;
      RECT 0.00000 21.45600 0.03600 21.48000 ;
    END
  END rb_data[446]
  PIN rb_data[447]
    DIRECTION OUTPUT ;
    USE SIGNAL ;
    PORT
      LAYER M4 ;
      RECT 0.00000 21.50400 0.03600 21.52800 ;
    END
  END rb_data[447]
  PIN rb_data[448]
    DIRECTION OUTPUT ;
    USE SIGNAL ;
    PORT
      LAYER M4 ;
      RECT 0.00000 21.55200 0.03600 21.57600 ;
    END
  END rb_data[448]
  PIN rb_data[449]
    DIRECTION OUTPUT ;
    USE SIGNAL ;
    PORT
      LAYER M4 ;
      RECT 0.00000 21.60000 0.03600 21.62400 ;
    END
  END rb_data[449]
  PIN rb_data[450]
    DIRECTION OUTPUT ;
    USE SIGNAL ;
    PORT
      LAYER M4 ;
      RECT 0.00000 21.64800 0.03600 21.67200 ;
    END
  END rb_data[450]
  PIN rb_data[451]
    DIRECTION OUTPUT ;
    USE SIGNAL ;
    PORT
      LAYER M4 ;
      RECT 0.00000 21.69600 0.03600 21.72000 ;
    END
  END rb_data[451]
  PIN rb_data[452]
    DIRECTION OUTPUT ;
    USE SIGNAL ;
    PORT
      LAYER M4 ;
      RECT 0.00000 21.74400 0.03600 21.76800 ;
    END
  END rb_data[452]
  PIN rb_data[453]
    DIRECTION OUTPUT ;
    USE SIGNAL ;
    PORT
      LAYER M4 ;
      RECT 0.00000 21.79200 0.03600 21.81600 ;
    END
  END rb_data[453]
  PIN rb_data[454]
    DIRECTION OUTPUT ;
    USE SIGNAL ;
    PORT
      LAYER M4 ;
      RECT 0.00000 21.84000 0.03600 21.86400 ;
    END
  END rb_data[454]
  PIN rb_data[455]
    DIRECTION OUTPUT ;
    USE SIGNAL ;
    PORT
      LAYER M4 ;
      RECT 0.00000 21.88800 0.03600 21.91200 ;
    END
  END rb_data[455]
  PIN rb_data[456]
    DIRECTION OUTPUT ;
    USE SIGNAL ;
    PORT
      LAYER M4 ;
      RECT 0.00000 21.93600 0.03600 21.96000 ;
    END
  END rb_data[456]
  PIN rb_data[457]
    DIRECTION OUTPUT ;
    USE SIGNAL ;
    PORT
      LAYER M4 ;
      RECT 0.00000 21.98400 0.03600 22.00800 ;
    END
  END rb_data[457]
  PIN rb_data[458]
    DIRECTION OUTPUT ;
    USE SIGNAL ;
    PORT
      LAYER M4 ;
      RECT 0.00000 22.03200 0.03600 22.05600 ;
    END
  END rb_data[458]
  PIN rb_data[459]
    DIRECTION OUTPUT ;
    USE SIGNAL ;
    PORT
      LAYER M4 ;
      RECT 0.00000 22.08000 0.03600 22.10400 ;
    END
  END rb_data[459]
  PIN rb_data[460]
    DIRECTION OUTPUT ;
    USE SIGNAL ;
    PORT
      LAYER M4 ;
      RECT 0.00000 22.12800 0.03600 22.15200 ;
    END
  END rb_data[460]
  PIN rb_data[461]
    DIRECTION OUTPUT ;
    USE SIGNAL ;
    PORT
      LAYER M4 ;
      RECT 0.00000 22.17600 0.03600 22.20000 ;
    END
  END rb_data[461]
  PIN rb_data[462]
    DIRECTION OUTPUT ;
    USE SIGNAL ;
    PORT
      LAYER M4 ;
      RECT 0.00000 22.22400 0.03600 22.24800 ;
    END
  END rb_data[462]
  PIN rb_data[463]
    DIRECTION OUTPUT ;
    USE SIGNAL ;
    PORT
      LAYER M4 ;
      RECT 0.00000 22.27200 0.03600 22.29600 ;
    END
  END rb_data[463]
  PIN rb_data[464]
    DIRECTION OUTPUT ;
    USE SIGNAL ;
    PORT
      LAYER M4 ;
      RECT 0.00000 22.32000 0.03600 22.34400 ;
    END
  END rb_data[464]
  PIN rb_data[465]
    DIRECTION OUTPUT ;
    USE SIGNAL ;
    PORT
      LAYER M4 ;
      RECT 0.00000 22.36800 0.03600 22.39200 ;
    END
  END rb_data[465]
  PIN rb_data[466]
    DIRECTION OUTPUT ;
    USE SIGNAL ;
    PORT
      LAYER M4 ;
      RECT 0.00000 22.41600 0.03600 22.44000 ;
    END
  END rb_data[466]
  PIN rb_data[467]
    DIRECTION OUTPUT ;
    USE SIGNAL ;
    PORT
      LAYER M4 ;
      RECT 0.00000 22.46400 0.03600 22.48800 ;
    END
  END rb_data[467]
  PIN rb_data[468]
    DIRECTION OUTPUT ;
    USE SIGNAL ;
    PORT
      LAYER M4 ;
      RECT 0.00000 22.51200 0.03600 22.53600 ;
    END
  END rb_data[468]
  PIN rb_data[469]
    DIRECTION OUTPUT ;
    USE SIGNAL ;
    PORT
      LAYER M4 ;
      RECT 0.00000 22.56000 0.03600 22.58400 ;
    END
  END rb_data[469]
  PIN rb_data[470]
    DIRECTION OUTPUT ;
    USE SIGNAL ;
    PORT
      LAYER M4 ;
      RECT 0.00000 22.60800 0.03600 22.63200 ;
    END
  END rb_data[470]
  PIN rb_data[471]
    DIRECTION OUTPUT ;
    USE SIGNAL ;
    PORT
      LAYER M4 ;
      RECT 0.00000 22.65600 0.03600 22.68000 ;
    END
  END rb_data[471]
  PIN rb_data[472]
    DIRECTION OUTPUT ;
    USE SIGNAL ;
    PORT
      LAYER M4 ;
      RECT 0.00000 22.70400 0.03600 22.72800 ;
    END
  END rb_data[472]
  PIN rb_data[473]
    DIRECTION OUTPUT ;
    USE SIGNAL ;
    PORT
      LAYER M4 ;
      RECT 0.00000 22.75200 0.03600 22.77600 ;
    END
  END rb_data[473]
  PIN rb_data[474]
    DIRECTION OUTPUT ;
    USE SIGNAL ;
    PORT
      LAYER M4 ;
      RECT 0.00000 22.80000 0.03600 22.82400 ;
    END
  END rb_data[474]
  PIN rb_data[475]
    DIRECTION OUTPUT ;
    USE SIGNAL ;
    PORT
      LAYER M4 ;
      RECT 0.00000 22.84800 0.03600 22.87200 ;
    END
  END rb_data[475]
  PIN rb_data[476]
    DIRECTION OUTPUT ;
    USE SIGNAL ;
    PORT
      LAYER M4 ;
      RECT 0.00000 22.89600 0.03600 22.92000 ;
    END
  END rb_data[476]
  PIN rb_data[477]
    DIRECTION OUTPUT ;
    USE SIGNAL ;
    PORT
      LAYER M4 ;
      RECT 0.00000 22.94400 0.03600 22.96800 ;
    END
  END rb_data[477]
  PIN rb_data[478]
    DIRECTION OUTPUT ;
    USE SIGNAL ;
    PORT
      LAYER M4 ;
      RECT 0.00000 22.99200 0.03600 23.01600 ;
    END
  END rb_data[478]
  PIN rb_data[479]
    DIRECTION OUTPUT ;
    USE SIGNAL ;
    PORT
      LAYER M4 ;
      RECT 0.00000 23.04000 0.03600 23.06400 ;
    END
  END rb_data[479]
  PIN rb_data[480]
    DIRECTION OUTPUT ;
    USE SIGNAL ;
    PORT
      LAYER M4 ;
      RECT 0.00000 23.08800 0.03600 23.11200 ;
    END
  END rb_data[480]
  PIN rb_data[481]
    DIRECTION OUTPUT ;
    USE SIGNAL ;
    PORT
      LAYER M4 ;
      RECT 0.00000 23.13600 0.03600 23.16000 ;
    END
  END rb_data[481]
  PIN rb_data[482]
    DIRECTION OUTPUT ;
    USE SIGNAL ;
    PORT
      LAYER M4 ;
      RECT 0.00000 23.18400 0.03600 23.20800 ;
    END
  END rb_data[482]
  PIN rb_data[483]
    DIRECTION OUTPUT ;
    USE SIGNAL ;
    PORT
      LAYER M4 ;
      RECT 0.00000 23.23200 0.03600 23.25600 ;
    END
  END rb_data[483]
  PIN rb_data[484]
    DIRECTION OUTPUT ;
    USE SIGNAL ;
    PORT
      LAYER M4 ;
      RECT 0.00000 23.28000 0.03600 23.30400 ;
    END
  END rb_data[484]
  PIN rb_data[485]
    DIRECTION OUTPUT ;
    USE SIGNAL ;
    PORT
      LAYER M4 ;
      RECT 0.00000 23.32800 0.03600 23.35200 ;
    END
  END rb_data[485]
  PIN rb_data[486]
    DIRECTION OUTPUT ;
    USE SIGNAL ;
    PORT
      LAYER M4 ;
      RECT 0.00000 23.37600 0.03600 23.40000 ;
    END
  END rb_data[486]
  PIN rb_data[487]
    DIRECTION OUTPUT ;
    USE SIGNAL ;
    PORT
      LAYER M4 ;
      RECT 0.00000 23.42400 0.03600 23.44800 ;
    END
  END rb_data[487]
  PIN rb_data[488]
    DIRECTION OUTPUT ;
    USE SIGNAL ;
    PORT
      LAYER M4 ;
      RECT 0.00000 23.47200 0.03600 23.49600 ;
    END
  END rb_data[488]
  PIN rb_data[489]
    DIRECTION OUTPUT ;
    USE SIGNAL ;
    PORT
      LAYER M4 ;
      RECT 0.00000 23.52000 0.03600 23.54400 ;
    END
  END rb_data[489]
  PIN rb_data[490]
    DIRECTION OUTPUT ;
    USE SIGNAL ;
    PORT
      LAYER M4 ;
      RECT 0.00000 23.56800 0.03600 23.59200 ;
    END
  END rb_data[490]
  PIN rb_data[491]
    DIRECTION OUTPUT ;
    USE SIGNAL ;
    PORT
      LAYER M4 ;
      RECT 0.00000 23.61600 0.03600 23.64000 ;
    END
  END rb_data[491]
  PIN rb_data[492]
    DIRECTION OUTPUT ;
    USE SIGNAL ;
    PORT
      LAYER M4 ;
      RECT 0.00000 23.66400 0.03600 23.68800 ;
    END
  END rb_data[492]
  PIN rb_data[493]
    DIRECTION OUTPUT ;
    USE SIGNAL ;
    PORT
      LAYER M4 ;
      RECT 0.00000 23.71200 0.03600 23.73600 ;
    END
  END rb_data[493]
  PIN rb_data[494]
    DIRECTION OUTPUT ;
    USE SIGNAL ;
    PORT
      LAYER M4 ;
      RECT 0.00000 23.76000 0.03600 23.78400 ;
    END
  END rb_data[494]
  PIN rb_data[495]
    DIRECTION OUTPUT ;
    USE SIGNAL ;
    PORT
      LAYER M4 ;
      RECT 0.00000 23.80800 0.03600 23.83200 ;
    END
  END rb_data[495]
  PIN rb_data[496]
    DIRECTION OUTPUT ;
    USE SIGNAL ;
    PORT
      LAYER M4 ;
      RECT 0.00000 23.85600 0.03600 23.88000 ;
    END
  END rb_data[496]
  PIN rb_data[497]
    DIRECTION OUTPUT ;
    USE SIGNAL ;
    PORT
      LAYER M4 ;
      RECT 0.00000 23.90400 0.03600 23.92800 ;
    END
  END rb_data[497]
  PIN rb_data[498]
    DIRECTION OUTPUT ;
    USE SIGNAL ;
    PORT
      LAYER M4 ;
      RECT 0.00000 23.95200 0.03600 23.97600 ;
    END
  END rb_data[498]
  PIN rb_data[499]
    DIRECTION OUTPUT ;
    USE SIGNAL ;
    PORT
      LAYER M4 ;
      RECT 0.00000 24.00000 0.03600 24.02400 ;
    END
  END rb_data[499]
  PIN rb_data[500]
    DIRECTION OUTPUT ;
    USE SIGNAL ;
    PORT
      LAYER M4 ;
      RECT 0.00000 24.04800 0.03600 24.07200 ;
    END
  END rb_data[500]
  PIN rb_data[501]
    DIRECTION OUTPUT ;
    USE SIGNAL ;
    PORT
      LAYER M4 ;
      RECT 0.00000 24.09600 0.03600 24.12000 ;
    END
  END rb_data[501]
  PIN rb_data[502]
    DIRECTION OUTPUT ;
    USE SIGNAL ;
    PORT
      LAYER M4 ;
      RECT 0.00000 24.14400 0.03600 24.16800 ;
    END
  END rb_data[502]
  PIN rb_data[503]
    DIRECTION OUTPUT ;
    USE SIGNAL ;
    PORT
      LAYER M4 ;
      RECT 0.00000 24.19200 0.03600 24.21600 ;
    END
  END rb_data[503]
  PIN rb_data[504]
    DIRECTION OUTPUT ;
    USE SIGNAL ;
    PORT
      LAYER M4 ;
      RECT 0.00000 24.24000 0.03600 24.26400 ;
    END
  END rb_data[504]
  PIN rb_data[505]
    DIRECTION OUTPUT ;
    USE SIGNAL ;
    PORT
      LAYER M4 ;
      RECT 0.00000 24.28800 0.03600 24.31200 ;
    END
  END rb_data[505]
  PIN rb_data[506]
    DIRECTION OUTPUT ;
    USE SIGNAL ;
    PORT
      LAYER M4 ;
      RECT 0.00000 24.33600 0.03600 24.36000 ;
    END
  END rb_data[506]
  PIN rb_data[507]
    DIRECTION OUTPUT ;
    USE SIGNAL ;
    PORT
      LAYER M4 ;
      RECT 0.00000 24.38400 0.03600 24.40800 ;
    END
  END rb_data[507]
  PIN rb_data[508]
    DIRECTION OUTPUT ;
    USE SIGNAL ;
    PORT
      LAYER M4 ;
      RECT 0.00000 24.43200 0.03600 24.45600 ;
    END
  END rb_data[508]
  PIN rb_data[509]
    DIRECTION OUTPUT ;
    USE SIGNAL ;
    PORT
      LAYER M4 ;
      RECT 0.00000 24.48000 0.03600 24.50400 ;
    END
  END rb_data[509]
  PIN rb_data[510]
    DIRECTION OUTPUT ;
    USE SIGNAL ;
    PORT
      LAYER M4 ;
      RECT 0.00000 24.52800 0.03600 24.55200 ;
    END
  END rb_data[510]
  PIN rb_data[511]
    DIRECTION OUTPUT ;
    USE SIGNAL ;
    PORT
      LAYER M4 ;
      RECT 0.00000 24.57600 0.03600 24.60000 ;
    END
  END rb_data[511]
  PIN rb_addr[0]
    DIRECTION INPUT ;
    USE SIGNAL ;
    PORT
      LAYER M4 ;
      RECT 0.00000 72.24000 0.03600 72.26400 ;
    END
  END rb_addr[0]
  PIN rb_addr[1]
    DIRECTION INPUT ;
    USE SIGNAL ;
    PORT
      LAYER M4 ;
      RECT 0.00000 72.28800 0.03600 72.31200 ;
    END
  END rb_addr[1]
  PIN rb_addr[2]
    DIRECTION INPUT ;
    USE SIGNAL ;
    PORT
      LAYER M4 ;
      RECT 0.00000 72.33600 0.03600 72.36000 ;
    END
  END rb_addr[2]
  PIN rb_addr[3]
    DIRECTION INPUT ;
    USE SIGNAL ;
    PORT
      LAYER M4 ;
      RECT 0.00000 72.38400 0.03600 72.40800 ;
    END
  END rb_addr[3]
  PIN rb_addr[4]
    DIRECTION INPUT ;
    USE SIGNAL ;
    PORT
      LAYER M4 ;
      RECT 0.00000 72.43200 0.03600 72.45600 ;
    END
  END rb_addr[4]
  PIN rb_addr[5]
    DIRECTION INPUT ;
    USE SIGNAL ;
    PORT
      LAYER M4 ;
      RECT 0.00000 72.48000 0.03600 72.50400 ;
    END
  END rb_addr[5]
  PIN rb_addr[6]
    DIRECTION INPUT ;
    USE SIGNAL ;
    PORT
      LAYER M4 ;
      RECT 0.00000 72.52800 0.03600 72.55200 ;
    END
  END rb_addr[6]
  PIN rb_addr[7]
    DIRECTION INPUT ;
    USE SIGNAL ;
    PORT
      LAYER M4 ;
      RECT 0.00000 72.57600 0.03600 72.60000 ;
    END
  END rb_addr[7]
  PIN we[0]
    DIRECTION INPUT ;
    USE SIGNAL ;
    PORT
      LAYER M4 ;
      RECT 0.00000 83.80800 0.03600 83.83200 ;
    END
  END we[0]
  PIN we[1]
    DIRECTION INPUT ;
    USE SIGNAL ;
    PORT
      LAYER M4 ;
      RECT 0.00000 83.85600 0.03600 83.88000 ;
    END
  END we[1]
  PIN clk
    DIRECTION INPUT ;
    USE SIGNAL ;
    PORT
      LAYER M4 ;
      RECT 0.00000 83.76000 0.03600 83.78400 ;
    END
  END clk
  PIN rb_en
    DIRECTION INPUT ;
    USE SIGNAL ;
    PORT
      LAYER M4 ;
      RECT 0.00000 83.90400 0.03600 83.92800 ;
    END
  END rb_en
  PIN rb_addr_q[0]
    DIRECTION OUTPUT ;
    USE SIGNAL ;
    PORT
      LAYER M4 ;
      RECT 0.00000 24.62400 0.03600 24.64800 ;
    END
  END rb_addr_q[0]
  PIN rb_addr_q[1]
    DIRECTION OUTPUT ;
    USE SIGNAL ;
    PORT
      LAYER M4 ;
      RECT 0.00000 24.67200 0.03600 24.69600 ;
    END
  END rb_addr_q[1]
  PIN rb_addr_q[2]
    DIRECTION OUTPUT ;
    USE SIGNAL ;
    PORT
      LAYER M4 ;
      RECT 0.00000 24.72000 0.03600 24.74400 ;
    END
  END rb_addr_q[2]
  PIN rb_addr_q[3]
    DIRECTION OUTPUT ;
    USE SIGNAL ;
    PORT
      LAYER M4 ;
      RECT 0.00000 24.76800 0.03600 24.79200 ;
    END
  END rb_addr_q[3]
  PIN rb_addr_q[4]
    DIRECTION OUTPUT ;
    USE SIGNAL ;
    PORT
      LAYER M4 ;
      RECT 0.00000 24.81600 0.03600 24.84000 ;
    END
  END rb_addr_q[4]
  PIN rb_addr_q[5]
    DIRECTION OUTPUT ;
    USE SIGNAL ;
    PORT
      LAYER M4 ;
      RECT 0.00000 24.86400 0.03600 24.88800 ;
    END
  END rb_addr_q[5]
  PIN rb_addr_q[6]
    DIRECTION OUTPUT ;
    USE SIGNAL ;
    PORT
      LAYER M4 ;
      RECT 0.00000 24.91200 0.03600 24.93600 ;
    END
  END rb_addr_q[6]
  PIN rb_addr_q[7]
    DIRECTION OUTPUT ;
    USE SIGNAL ;
    PORT
      LAYER M4 ;
      RECT 0.00000 24.96000 0.03600 24.98400 ;
    END
  END rb_addr_q[7]
  PIN VDD
    DIRECTION INOUT ;
    USE POWER ;
    PORT
      LAYER M4 ;
      RECT 0.09600 0.38400 66.40400 0.48000 ;
      RECT 0.09600 1.15200 66.40400 1.24800 ;
      RECT 0.09600 1.92000 66.40400 2.01600 ;
      RECT 0.09600 2.68800 66.40400 2.78400 ;
      RECT 0.09600 3.45600 66.40400 3.55200 ;
      RECT 0.09600 4.22400 66.40400 4.32000 ;
      RECT 0.09600 4.99200 66.40400 5.08800 ;
      RECT 0.09600 5.76000 66.40400 5.85600 ;
      RECT 0.09600 6.52800 66.40400 6.62400 ;
      RECT 0.09600 7.29600 66.40400 7.39200 ;
      RECT 0.09600 8.06400 66.40400 8.16000 ;
      RECT 0.09600 8.83200 66.40400 8.92800 ;
      RECT 0.09600 9.60000 66.40400 9.69600 ;
      RECT 0.09600 10.36800 66.40400 10.46400 ;
      RECT 0.09600 11.13600 66.40400 11.23200 ;
      RECT 0.09600 11.90400 66.40400 12.00000 ;
      RECT 0.09600 12.67200 66.40400 12.76800 ;
      RECT 0.09600 13.44000 66.40400 13.53600 ;
      RECT 0.09600 14.20800 66.40400 14.30400 ;
      RECT 0.09600 14.97600 66.40400 15.07200 ;
      RECT 0.09600 15.74400 66.40400 15.84000 ;
      RECT 0.09600 16.51200 66.40400 16.60800 ;
      RECT 0.09600 17.28000 66.40400 17.37600 ;
      RECT 0.09600 18.04800 66.40400 18.14400 ;
      RECT 0.09600 18.81600 66.40400 18.91200 ;
      RECT 0.09600 19.58400 66.40400 19.68000 ;
      RECT 0.09600 20.35200 66.40400 20.44800 ;
      RECT 0.09600 21.12000 66.40400 21.21600 ;
      RECT 0.09600 21.88800 66.40400 21.98400 ;
      RECT 0.09600 22.65600 66.40400 22.75200 ;
      RECT 0.09600 23.42400 66.40400 23.52000 ;
      RECT 0.09600 24.19200 66.40400 24.28800 ;
      RECT 0.09600 24.96000 66.40400 25.05600 ;
      RECT 0.09600 25.72800 66.40400 25.82400 ;
      RECT 0.09600 26.49600 66.40400 26.59200 ;
      RECT 0.09600 27.26400 66.40400 27.36000 ;
      RECT 0.09600 28.03200 66.40400 28.12800 ;
      RECT 0.09600 28.80000 66.40400 28.89600 ;
      RECT 0.09600 29.56800 66.40400 29.66400 ;
      RECT 0.09600 30.33600 66.40400 30.43200 ;
      RECT 0.09600 31.10400 66.40400 31.20000 ;
      RECT 0.09600 31.87200 66.40400 31.96800 ;
      RECT 0.09600 32.64000 66.40400 32.73600 ;
      RECT 0.09600 33.40800 66.40400 33.50400 ;
      RECT 0.09600 34.17600 66.40400 34.27200 ;
      RECT 0.09600 34.94400 66.40400 35.04000 ;
      RECT 0.09600 35.71200 66.40400 35.80800 ;
      RECT 0.09600 36.48000 66.40400 36.57600 ;
      RECT 0.09600 37.24800 66.40400 37.34400 ;
      RECT 0.09600 38.01600 66.40400 38.11200 ;
      RECT 0.09600 38.78400 66.40400 38.88000 ;
      RECT 0.09600 39.55200 66.40400 39.64800 ;
      RECT 0.09600 40.32000 66.40400 40.41600 ;
      RECT 0.09600 41.08800 66.40400 41.18400 ;
      RECT 0.09600 41.85600 66.40400 41.95200 ;
      RECT 0.09600 42.62400 66.40400 42.72000 ;
      RECT 0.09600 43.39200 66.40400 43.48800 ;
      RECT 0.09600 44.16000 66.40400 44.25600 ;
      RECT 0.09600 44.92800 66.40400 45.02400 ;
      RECT 0.09600 45.69600 66.40400 45.79200 ;
      RECT 0.09600 46.46400 66.40400 46.56000 ;
      RECT 0.09600 47.23200 66.40400 47.32800 ;
      RECT 0.09600 48.00000 66.40400 48.09600 ;
      RECT 0.09600 48.76800 66.40400 48.86400 ;
      RECT 0.09600 49.53600 66.40400 49.63200 ;
      RECT 0.09600 50.30400 66.40400 50.40000 ;
      RECT 0.09600 51.07200 66.40400 51.16800 ;
      RECT 0.09600 51.84000 66.40400 51.93600 ;
      RECT 0.09600 52.60800 66.40400 52.70400 ;
      RECT 0.09600 53.37600 66.40400 53.47200 ;
      RECT 0.09600 54.14400 66.40400 54.24000 ;
      RECT 0.09600 54.91200 66.40400 55.00800 ;
      RECT 0.09600 55.68000 66.40400 55.77600 ;
      RECT 0.09600 56.44800 66.40400 56.54400 ;
      RECT 0.09600 57.21600 66.40400 57.31200 ;
      RECT 0.09600 57.98400 66.40400 58.08000 ;
      RECT 0.09600 58.75200 66.40400 58.84800 ;
      RECT 0.09600 59.52000 66.40400 59.61600 ;
      RECT 0.09600 60.28800 66.40400 60.38400 ;
      RECT 0.09600 61.05600 66.40400 61.15200 ;
      RECT 0.09600 61.82400 66.40400 61.92000 ;
      RECT 0.09600 62.59200 66.40400 62.68800 ;
      RECT 0.09600 63.36000 66.40400 63.45600 ;
      RECT 0.09600 64.12800 66.40400 64.22400 ;
      RECT 0.09600 64.89600 66.40400 64.99200 ;
      RECT 0.09600 65.66400 66.40400 65.76000 ;
      RECT 0.09600 66.43200 66.40400 66.52800 ;
      RECT 0.09600 67.20000 66.40400 67.29600 ;
      RECT 0.09600 67.96800 66.40400 68.06400 ;
      RECT 0.09600 68.73600 66.40400 68.83200 ;
      RECT 0.09600 69.50400 66.40400 69.60000 ;
      RECT 0.09600 70.27200 66.40400 70.36800 ;
      RECT 0.09600 71.04000 66.40400 71.13600 ;
      RECT 0.09600 71.80800 66.40400 71.90400 ;
      RECT 0.09600 72.57600 66.40400 72.67200 ;
      RECT 0.09600 73.34400 66.40400 73.44000 ;
      RECT 0.09600 74.11200 66.40400 74.20800 ;
      RECT 0.09600 74.88000 66.40400 74.97600 ;
      RECT 0.09600 75.64800 66.40400 75.74400 ;
      RECT 0.09600 76.41600 66.40400 76.51200 ;
      RECT 0.09600 77.18400 66.40400 77.28000 ;
      RECT 0.09600 77.95200 66.40400 78.04800 ;
      RECT 0.09600 78.72000 66.40400 78.81600 ;
      RECT 0.09600 79.48800 66.40400 79.58400 ;
      RECT 0.09600 80.25600 66.40400 80.35200 ;
      RECT 0.09600 81.02400 66.40400 81.12000 ;
      RECT 0.09600 81.79200 66.40400 81.88800 ;
      RECT 0.09600 82.56000 66.40400 82.65600 ;
      RECT 0.09600 83.32800 66.40400 83.42400 ;
    END
  END VDD
  PIN VSS
    DIRECTION INOUT ;
    USE GROUND ;
    PORT
      LAYER M4 ;
      RECT 0.09600 0.00000 66.40400 0.09600 ;
      RECT 0.09600 0.76800 66.40400 0.86400 ;
      RECT 0.09600 1.53600 66.40400 1.63200 ;
      RECT 0.09600 2.30400 66.40400 2.40000 ;
      RECT 0.09600 3.07200 66.40400 3.16800 ;
      RECT 0.09600 3.84000 66.40400 3.93600 ;
      RECT 0.09600 4.60800 66.40400 4.70400 ;
      RECT 0.09600 5.37600 66.40400 5.47200 ;
      RECT 0.09600 6.14400 66.40400 6.24000 ;
      RECT 0.09600 6.91200 66.40400 7.00800 ;
      RECT 0.09600 7.68000 66.40400 7.77600 ;
      RECT 0.09600 8.44800 66.40400 8.54400 ;
      RECT 0.09600 9.21600 66.40400 9.31200 ;
      RECT 0.09600 9.98400 66.40400 10.08000 ;
      RECT 0.09600 10.75200 66.40400 10.84800 ;
      RECT 0.09600 11.52000 66.40400 11.61600 ;
      RECT 0.09600 12.28800 66.40400 12.38400 ;
      RECT 0.09600 13.05600 66.40400 13.15200 ;
      RECT 0.09600 13.82400 66.40400 13.92000 ;
      RECT 0.09600 14.59200 66.40400 14.68800 ;
      RECT 0.09600 15.36000 66.40400 15.45600 ;
      RECT 0.09600 16.12800 66.40400 16.22400 ;
      RECT 0.09600 16.89600 66.40400 16.99200 ;
      RECT 0.09600 17.66400 66.40400 17.76000 ;
      RECT 0.09600 18.43200 66.40400 18.52800 ;
      RECT 0.09600 19.20000 66.40400 19.29600 ;
      RECT 0.09600 19.96800 66.40400 20.06400 ;
      RECT 0.09600 20.73600 66.40400 20.83200 ;
      RECT 0.09600 21.50400 66.40400 21.60000 ;
      RECT 0.09600 22.27200 66.40400 22.36800 ;
      RECT 0.09600 23.04000 66.40400 23.13600 ;
      RECT 0.09600 23.80800 66.40400 23.90400 ;
      RECT 0.09600 24.57600 66.40400 24.67200 ;
      RECT 0.09600 25.34400 66.40400 25.44000 ;
      RECT 0.09600 26.11200 66.40400 26.20800 ;
      RECT 0.09600 26.88000 66.40400 26.97600 ;
      RECT 0.09600 27.64800 66.40400 27.74400 ;
      RECT 0.09600 28.41600 66.40400 28.51200 ;
      RECT 0.09600 29.18400 66.40400 29.28000 ;
      RECT 0.09600 29.95200 66.40400 30.04800 ;
      RECT 0.09600 30.72000 66.40400 30.81600 ;
      RECT 0.09600 31.48800 66.40400 31.58400 ;
      RECT 0.09600 32.25600 66.40400 32.35200 ;
      RECT 0.09600 33.02400 66.40400 33.12000 ;
      RECT 0.09600 33.79200 66.40400 33.88800 ;
      RECT 0.09600 34.56000 66.40400 34.65600 ;
      RECT 0.09600 35.32800 66.40400 35.42400 ;
      RECT 0.09600 36.09600 66.40400 36.19200 ;
      RECT 0.09600 36.86400 66.40400 36.96000 ;
      RECT 0.09600 37.63200 66.40400 37.72800 ;
      RECT 0.09600 38.40000 66.40400 38.49600 ;
      RECT 0.09600 39.16800 66.40400 39.26400 ;
      RECT 0.09600 39.93600 66.40400 40.03200 ;
      RECT 0.09600 40.70400 66.40400 40.80000 ;
      RECT 0.09600 41.47200 66.40400 41.56800 ;
      RECT 0.09600 42.24000 66.40400 42.33600 ;
      RECT 0.09600 43.00800 66.40400 43.10400 ;
      RECT 0.09600 43.77600 66.40400 43.87200 ;
      RECT 0.09600 44.54400 66.40400 44.64000 ;
      RECT 0.09600 45.31200 66.40400 45.40800 ;
      RECT 0.09600 46.08000 66.40400 46.17600 ;
      RECT 0.09600 46.84800 66.40400 46.94400 ;
      RECT 0.09600 47.61600 66.40400 47.71200 ;
      RECT 0.09600 48.38400 66.40400 48.48000 ;
      RECT 0.09600 49.15200 66.40400 49.24800 ;
      RECT 0.09600 49.92000 66.40400 50.01600 ;
      RECT 0.09600 50.68800 66.40400 50.78400 ;
      RECT 0.09600 51.45600 66.40400 51.55200 ;
      RECT 0.09600 52.22400 66.40400 52.32000 ;
      RECT 0.09600 52.99200 66.40400 53.08800 ;
      RECT 0.09600 53.76000 66.40400 53.85600 ;
      RECT 0.09600 54.52800 66.40400 54.62400 ;
      RECT 0.09600 55.29600 66.40400 55.39200 ;
      RECT 0.09600 56.06400 66.40400 56.16000 ;
      RECT 0.09600 56.83200 66.40400 56.92800 ;
      RECT 0.09600 57.60000 66.40400 57.69600 ;
      RECT 0.09600 58.36800 66.40400 58.46400 ;
      RECT 0.09600 59.13600 66.40400 59.23200 ;
      RECT 0.09600 59.90400 66.40400 60.00000 ;
      RECT 0.09600 60.67200 66.40400 60.76800 ;
      RECT 0.09600 61.44000 66.40400 61.53600 ;
      RECT 0.09600 62.20800 66.40400 62.30400 ;
      RECT 0.09600 62.97600 66.40400 63.07200 ;
      RECT 0.09600 63.74400 66.40400 63.84000 ;
      RECT 0.09600 64.51200 66.40400 64.60800 ;
      RECT 0.09600 65.28000 66.40400 65.37600 ;
      RECT 0.09600 66.04800 66.40400 66.14400 ;
      RECT 0.09600 66.81600 66.40400 66.91200 ;
      RECT 0.09600 67.58400 66.40400 67.68000 ;
      RECT 0.09600 68.35200 66.40400 68.44800 ;
      RECT 0.09600 69.12000 66.40400 69.21600 ;
      RECT 0.09600 69.88800 66.40400 69.98400 ;
      RECT 0.09600 70.65600 66.40400 70.75200 ;
      RECT 0.09600 71.42400 66.40400 71.52000 ;
      RECT 0.09600 72.19200 66.40400 72.28800 ;
      RECT 0.09600 72.96000 66.40400 73.05600 ;
      RECT 0.09600 73.72800 66.40400 73.82400 ;
      RECT 0.09600 74.49600 66.40400 74.59200 ;
      RECT 0.09600 75.26400 66.40400 75.36000 ;
      RECT 0.09600 76.03200 66.40400 76.12800 ;
      RECT 0.09600 76.80000 66.40400 76.89600 ;
      RECT 0.09600 77.56800 66.40400 77.66400 ;
      RECT 0.09600 78.33600 66.40400 78.43200 ;
      RECT 0.09600 79.10400 66.40400 79.20000 ;
      RECT 0.09600 79.87200 66.40400 79.96800 ;
      RECT 0.09600 80.64000 66.40400 80.73600 ;
      RECT 0.09600 81.40800 66.40400 81.50400 ;
      RECT 0.09600 82.17600 66.40400 82.27200 ;
      RECT 0.09600 82.94400 66.40400 83.04000 ;
      RECT 0.09600 83.71200 66.40400 83.80800 ;
    END
  END VSS
  OBS
    LAYER M1 ;
    RECT 0 0 66.50000 84.00000 ;
    LAYER M2 ;
    RECT 0 0 66.50000 84.00000 ;
    LAYER M3 ;
    RECT 0 0 66.50000 84.00000 ;
    LAYER M4 ;
    RECT 0 0 66.50000 84.00000 ;
  END
END fakeram7_256x512_g2_1w1r

END LIBRARY
